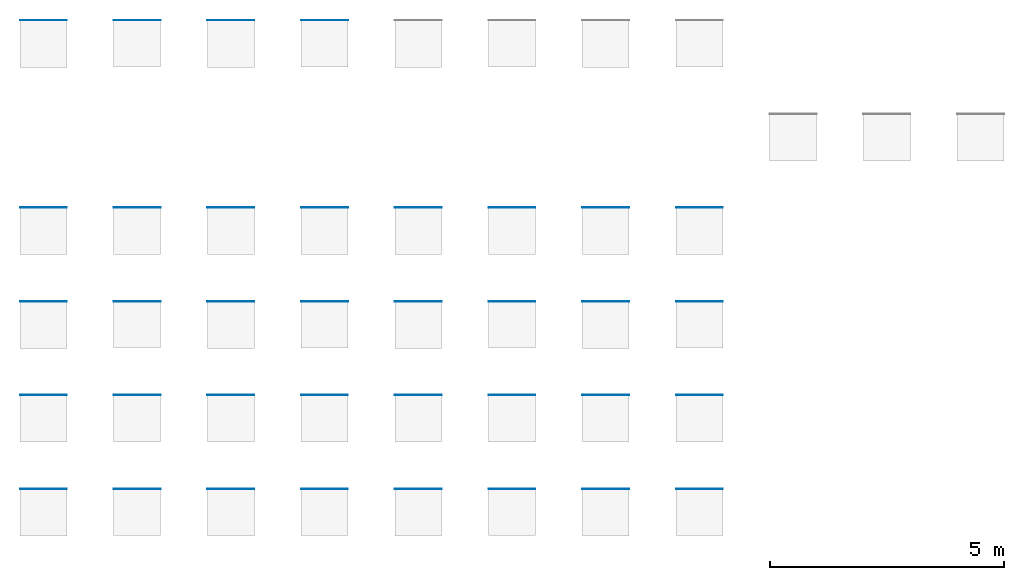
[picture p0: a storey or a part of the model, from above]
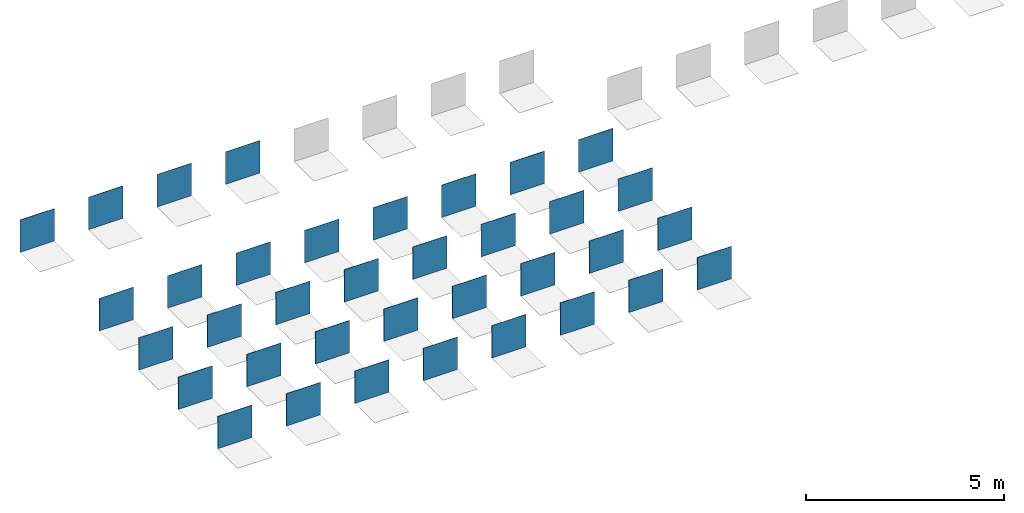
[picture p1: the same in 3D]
Properties of the parts of a building model (IFC2X3), part 1 of 7

# File
Description: ViewDefinition [CoordinationView_V2.0]
Time: 2025-06-20T12:25:42
Written by: The EXPRESS Data Manager Version 5.02.0100.07 : 28 Aug 2013
Made in: 21.1.90.15 - Exporter 21.1.90.15 - Alternate UI 21.1.90.15
Comment: STEP Physical File produced by: The EXPRESS Data Manager Version 5.02.0100.07 : 28 Aug 2013 * Module: EDMstepFileFactory/EDMstandAlone * Creation date: Fri Jun 20 12:25:42 2025 * Host: STB002 * Database: C:\Users\LARISS~1\AppData\Local\Temp\234e31d9-e186-458c-9206-d387dea7a233\df8ae8d7-8933-4d32-850e-2fcda2edac5a\ifc * Database version: 5507 * Database creation date: Fri Jun 20 12:25:40 2025 * Schema: IFC2X3 * Model: DataRepository.ifc * Model creation date: Fri Jun 20 12:25:40 2025 * Header model: DataRepository.ifc_HeaderModel * Header model creation date: Fri Jun 20 12:25:40 2025 * EDMuser: sdai-user * EDMgroup: sdai-group * License ID and type: 5605 : Permanent license. Expiry date: * EDMstepFileFactory options: 020000

# IfcSite, Default
RefLatitude: 42, 24, 53, 508911; RefLongitude: -71, -15, -29, -58837; RefElevation: 0 mm
Pset_ProductRequirements - Category: Project Information

# IfcBuilding
Pset_BuildingCommon - NumberOfStoreys: 1
Pset_ProductRequirements - Category: Project Information

# IfcBuildingStorey: Level:Level 1, Level 1
LongName: Level 1; Elevation: 0 mm
Pset_AirSideSystemInformation - Name: Level 1
Pset_ProductRequirements - Name: Level 1; Category: Levels

# IfcCovering: Floor:REVIGRÉS-LOCUS-BASE-29.5x29.5-SILK-QUILT GREEN (2)
In: Level 1
Type - PredefinedType: CLADDING; Material: REVIGRÉS-LOCUS-BASE-30X30-SILK-QUILT GREEN 8.5 mm
Type - Pset_CoveringCommon - Reference: 312G12V661; Material: Grés porcelânico
Type - Pset_ElementShading - Roughness: 304.8 mm
Type - Pset_ManufacturerTypeInformation - Manufacturer: REVIGRÉS
Type - Pset_ProductRequirements - Category: Floors
Type - Pset_QuantityTakeOff - Reference: 312G12V661
Type - IFC.REVIGRÉS-Dados do fabricante-Floor Covering - FabricanteURL: https://www.revigres.pt/; ReferenciaModelo: Locus; NumeroGlobalDeItemComercial: 312G12V661; Acabamento: SILK; Material: Grés porcelânico; IdentificadorDoOperadorEconomico: 501840856; UrlFabricanteArtigo: https://www.revigres.pt/colecoes/locus; PaisOrigem: Portugal
Type - IFC.REVIGRÉS-Dados de desempenho-Floor Covering - Rectilinearidade: ± 0.2% máx.± 0.8 mm; Ortogonalidade: ± 0.2% máx.± 1.5 mm; PlanaridadeDaSuperficie: ± 0.3% máx. ± 1.8 mm; QualidadeDaSuperficie: Cumpre; AbsorcaoDeAgua: < 0.05%; ModuloDeRuptura: > 45 N/mm²; ResistenciaAFlexao: > 2000 N; ResistenciaAAbrasaoProfunda: < 120 mm³; DilatacaoTermicaLinear: ≤ 8,0x10-6 °C-1; ResistenciaAoChoqueTermico: Resiste; DurabilidadeInterior: Cumpre; DurabilidadeResistenciaAoGeloDegelo: Resiste; ResistenciaAoEscorregamentoDIN51130: R9; ResistenciaAoEscorregamentoDIN51097: A; ResistenciaAoEscorregamentoENV51097: A; ResistenciaAoEscorregamentoENV12633: Class 1; ResistenciaAoEscorregamentoBS7976: -; ResistenciaAoEscorregamentoANSIA1371: ≥0,42; ResistenciaAoDeslizamentoENV12633: Class 1; ResistenciaAoDeslizamentoBS7976: -; ResistenciaAsManchas: Class 5; LibertacaoDeCadmio: 0; LibertacaoDeChumbo: 0
Type - IFC.REVIGRÉS-Dados de especificação-Floor Covering - VariacaoTonalidade: 3; NivelDeTrafego: 5; EPavimento: Sim; ERevestimento: Sim; EExterno: Sim
Type - IFC.REVIGRÉS-Dados geométricos-Floor Covering - AlturaNominal: 8.5 mm; ComprimentoNominal: 29.5 mm; LarguraNominal: 29.5 mm
Type - IFC.REVIGRÉS-Dados de sustentabilidade-Floor Covering - ItemEParcialmenteReciclado: 0; EnergiaTermicaExportada: 0; ItemENovo: Sim; ItemEReciclado: Não; VidaÚtilEsperada: 50; SubstanciasPerigosas: Não; PotencialDeEsgotamentoAbioticoDosRecursosFosseis: 203; PotencialDeEsgotamentoAbioticoDosRecursosNaoFosseisMineraisEMetais: 0.000701; PotencialDeAquecimentoGlobalBiogenico: -0.48; CombustiveisFosseisComPotencialDeAquecimentoGlobal: 13.9; PotencialDeAquecimentoGlobalUsoDoSoloEMudancaDeUsoDoSolo: 0.0246; PotencialDeEutrofizacaoFraccaoDeNutrientesQueAtingemOCompartimentoFinalDeAguaDoce: 0.000189; PotencialDeEutrofizacaoFraccaoDeNutrientesQueAtingemOCompartimentoFinalMarinho: 0.0122; EnergiaRecuperada: 0.00739; ConsumoDeAguaDoce: 0.113; UtilizacaoLiquidaDeAguaDoce: 0.113; ResiduosPerigososEliminados: 0.00221; ResiduosNaoPerigososEliminados: 1.83; MassaTotalDeResiduosRadioactivosEliminados: 0.000394; EnergiaElectricaExportada: 1.55; MateriaisParaRecuperacaoDeEnergia: 0.00739; MateriaisParaReciclagem: 0.0253; UnidadeEPD: 1 m²
Type - IFC.REVIGRÉS-Dados gerais-Floor Covering - Nome: REVIGRÉS-LOCUS-BASE-29.5x29.5-SILK-QUILT GREEN; TipoProduto: Prensado a seco: grupo BIa UGL | Grés porcelânico técnico; NumeroDeRegistoDAP: EPD-REV-20240006-CCC1-EN; ReferenciaDAP: -; UrlDOP: -
Classification: C3010 (Uniformat)
Pset_CoveringCommon - TotalThickness: 8.5 mm
IFC.REVIGRÉS-Dados do fabricante-Floor Covering - Type: Floor: REVIGRÉS-LOCUS-BASE-29.5x29.5-SILK-QUILT GREEN
IFC.REVIGRÉS-Dados de desempenho-Floor Covering - Type: Floor: REVIGRÉS-LOCUS-BASE-29.5x29.5-SILK-QUILT GREEN
IFC.REVIGRÉS-Dados de especificação-Floor Covering - Type: Floor: REVIGRÉS-LOCUS-BASE-29.5x29.5-SILK-QUILT GREEN
IFC.REVIGRÉS-Dados geométricos-Floor Covering - Type: Floor: REVIGRÉS-LOCUS-BASE-29.5x29.5-SILK-QUILT GREEN
IFC.REVIGRÉS-Dados de sustentabilidade-Floor Covering - Type: Floor: REVIGRÉS-LOCUS-BASE-29.5x29.5-SILK-QUILT GREEN
Name (Floor:REVIGRÉS-LOCUS-BASE-29.5x29.5-SILK-QUILT GREEN:...)
40861
40868

# IfcCovering: Floor:REVIGRÉS-LOCUS-BASE-29.5x29.5-SILK-QUILT GRIS, Floor:REVIGRÉS-LOCUS-BASE-29.5x29.5-SILK-QUILT GRIS:40875
In: Level 1
Type - PredefinedType: CLADDING; Material: REVIGRÉS-LOCUS-BASE-30X30-SILK-QUILT GRIS 8.5 mm
Type - Pset_CoveringCommon - Reference: 312G12V651; Material: Grés porcelânico
Type - Pset_ElementShading - Roughness: 304.8 mm
Type - Pset_ManufacturerTypeInformation - Manufacturer: REVIGRÉS
Type - Pset_ProductRequirements - Category: Floors
Type - Pset_QuantityTakeOff - Reference: 312G12V651
Type - IFC.REVIGRÉS-Dados do fabricante-Floor Covering - FabricanteURL: https://www.revigres.pt/; ReferenciaModelo: Locus; NumeroGlobalDeItemComercial: 312G12V651; Acabamento: SILK; Material: Grés porcelânico; IdentificadorDoOperadorEconomico: 501840856; UrlFabricanteArtigo: https://www.revigres.pt/colecoes/locus; PaisOrigem: Portugal
Type - IFC.REVIGRÉS-Dados de desempenho-Floor Covering - Rectilinearidade: ± 0.2% máx.± 0.8 mm; Ortogonalidade: ± 0.2% máx.± 1.5 mm; PlanaridadeDaSuperficie: ± 0.3% máx. ± 1.8 mm; QualidadeDaSuperficie: Cumpre; AbsorcaoDeAgua: < 0.05%; ModuloDeRuptura: > 45 N/mm²; ResistenciaAFlexao: > 2000 N; ResistenciaAAbrasaoProfunda: < 120 mm³; DilatacaoTermicaLinear: ≤ 8,0x10-6 °C-1; ResistenciaAoChoqueTermico: Resiste; DurabilidadeInterior: Cumpre; DurabilidadeResistenciaAoGeloDegelo: Resiste; ResistenciaAoEscorregamentoDIN51130: R9; ResistenciaAoEscorregamentoDIN51097: A; ResistenciaAoEscorregamentoENV51097: A; ResistenciaAoEscorregamentoENV12633: Class 1; ResistenciaAoEscorregamentoBS7976: -; ResistenciaAoEscorregamentoANSIA1371: ≥0,42; ResistenciaAoDeslizamentoENV12633: Class 1; ResistenciaAoDeslizamentoBS7976: -; ResistenciaAsManchas: Class 5; LibertacaoDeCadmio: 0; LibertacaoDeChumbo: 0
Type - IFC.REVIGRÉS-Dados de especificação-Floor Covering - VariacaoTonalidade: 3; NivelDeTrafego: 5; EPavimento: Sim; ERevestimento: Sim; EExterno: Sim
Type - IFC.REVIGRÉS-Dados geométricos-Floor Covering - AlturaNominal: 8.5 mm; ComprimentoNominal: 29.5 mm; LarguraNominal: 29.5 mm
Type - IFC.REVIGRÉS-Dados de sustentabilidade-Floor Covering - EnergiaTermicaExportada: 0; ItemENovo: Sim; ItemEParcialmenteReciclado: 0.23; ItemEReciclado: Sim; VidaÚtilEsperada: 50; SubstanciasPerigosas: Não; PotencialDeEsgotamentoAbioticoDosRecursosFosseis: 203; PotencialDeEsgotamentoAbioticoDosRecursosNaoFosseisMineraisEMetais: 0.000701; PotencialDeAquecimentoGlobalBiogenico: -0.48; CombustiveisFosseisComPotencialDeAquecimentoGlobal: 13.9; PotencialDeAquecimentoGlobalUsoDoSoloEMudancaDeUsoDoSolo: 0.0246; PotencialDeEutrofizacaoFraccaoDeNutrientesQueAtingemOCompartimentoFinalDeAguaDoce: 0.000189; PotencialDeEutrofizacaoFraccaoDeNutrientesQueAtingemOCompartimentoFinalMarinho: 0.0122; EnergiaRecuperada: 0.00739; ConsumoDeAguaDoce: 0.113; UtilizacaoLiquidaDeAguaDoce: 0.113; ResiduosPerigososEliminados: 0.00221; ResiduosNaoPerigososEliminados: 1.83; MassaTotalDeResiduosRadioactivosEliminados: 0.000394; EnergiaElectricaExportada: 1.55; MateriaisParaRecuperacaoDeEnergia: 0.00739; MateriaisParaReciclagem: 0.0253; UnidadeEPD: 1 m²
Type - IFC.REVIGRÉS-Dados gerais-Floor Covering - Nome: REVIGRÉS-LOCUS-BASE-29.5x29.5-SILK-QUILT GRIS; TipoProduto: Prensado a seco: grupo BIa UGL | Grés porcelânico técnico; NumeroDeRegistoDAP: EPD-REV-20240006-CCC1-EN; ReferenciaDAP: -; UrlDOP: -
Classification: C3010 (Uniformat)
Pset_CoveringCommon - TotalThickness: 8.5 mm
IFC.REVIGRÉS-Dados do fabricante-Floor Covering - Type: Floor: REVIGRÉS-LOCUS-BASE-29.5x29.5-SILK-QUILT GRIS
IFC.REVIGRÉS-Dados de desempenho-Floor Covering - Type: Floor: REVIGRÉS-LOCUS-BASE-29.5x29.5-SILK-QUILT GRIS
IFC.REVIGRÉS-Dados de especificação-Floor Covering - Type: Floor: REVIGRÉS-LOCUS-BASE-29.5x29.5-SILK-QUILT GRIS
IFC.REVIGRÉS-Dados geométricos-Floor Covering - Type: Floor: REVIGRÉS-LOCUS-BASE-29.5x29.5-SILK-QUILT GRIS
IFC.REVIGRÉS-Dados de sustentabilidade-Floor Covering - Type: Floor: REVIGRÉS-LOCUS-BASE-29.5x29.5-SILK-QUILT GRIS

# IfcCovering: Floor:REVIGRÉS-LOCUS-BASE-29.5x29.5-SOFT GRIP-QUILT BONE, Floor:REVIGRÉS-LOCUS-BASE-29.5x29.5-SOFT GRIP-QUILT BONE:40825
In: Level 1
Type - PredefinedType: CLADDING; Material: REVIGRÉS-LOCUS-BASE-30X30-SOFT GRIP-QUILT BONE 8.5 mm
Type - Pset_CoveringCommon - Reference: 312F12V641; Material: Grés porcelânico
Type - Pset_ElementShading - Roughness: 304.8 mm
Type - Pset_ManufacturerTypeInformation - Manufacturer: REVIGRÉS
Type - Pset_ProductRequirements - Category: Floors
Type - Pset_QuantityTakeOff - Reference: 312F12V641
Type - IFC.REVIGRÉS-Dados do fabricante-Floor Covering - FabricanteURL: https://www.revigres.pt/; ReferenciaModelo: Locus; NumeroGlobalDeItemComercial: 312F12V641; Acabamento: SOFT; Material: Grés porcelânico; IdentificadorDoOperadorEconomico: 501840856; UrlFabricanteArtigo: https://www.revigres.pt/colecoes/locus; PaisOrigem: Portugal
Type - IFC.REVIGRÉS-Dados de desempenho-Floor Covering - Rectilinearidade: ± 0.2% máx ± 1.0 mm; Ortogonalidade: ± 0.2% máx.± 1.5 mm; PlanaridadeDaSuperficie: ± 0.3% máx. ± 1.8 mm; QualidadeDaSuperficie: Cumpre; AbsorcaoDeAgua: < 0.05%; ModuloDeRuptura: > 45 N/mm²; ResistenciaAFlexao: > 2000 N; ResistenciaAAbrasaoProfunda: < 120 mm³; DilatacaoTermicaLinear: ≤ 8,0x10-6 °C-1; ResistenciaAoChoqueTermico: Resiste; DurabilidadeInterior: Cumpre; DurabilidadeResistenciaAoGeloDegelo: Resiste; ResistenciaAoEscorregamentoDIN51130: R11; ResistenciaAoEscorregamentoDIN51097: A; ResistenciaAoEscorregamentoENV51097: A; ResistenciaAoEscorregamentoENV12633: Class 2; ResistenciaAoEscorregamentoBS7976: > 36; ResistenciaAoEscorregamentoANSIA1371: ≥0,42; ResistenciaAoDeslizamentoENV12633: Class 2; ResistenciaAoDeslizamentoBS7976: > 36; ResistenciaAsManchas: Class 5; LibertacaoDeCadmio: 0; LibertacaoDeChumbo: 0
Type - IFC.REVIGRÉS-Dados de especificação-Floor Covering - VariacaoTonalidade: 3; NivelDeTrafego: 5; EPavimento: Sim; ERevestimento: Sim; EExterno: Sim
Type - IFC.REVIGRÉS-Dados geométricos-Floor Covering - AlturaNominal: 8.5 mm; ComprimentoNominal: 29.5 mm; LarguraNominal: 29.5 mm
Type - IFC.REVIGRÉS-Dados de sustentabilidade-Floor Covering - ItemEParcialmenteReciclado: 0; EnergiaTermicaExportada: 0; ItemENovo: Sim; ItemEReciclado: Não; VidaÚtilEsperada: 50; SubstanciasPerigosas: Não; PotencialDeEsgotamentoAbioticoDosRecursosFosseis: 203; PotencialDeEsgotamentoAbioticoDosRecursosNaoFosseisMineraisEMetais: 0.000701; PotencialDeAquecimentoGlobalBiogenico: -0.48; CombustiveisFosseisComPotencialDeAquecimentoGlobal: 13.9; PotencialDeAquecimentoGlobalUsoDoSoloEMudancaDeUsoDoSolo: 0.0246; PotencialDeEutrofizacaoFraccaoDeNutrientesQueAtingemOCompartimentoFinalDeAguaDoce: 0.000189; PotencialDeEutrofizacaoFraccaoDeNutrientesQueAtingemOCompartimentoFinalMarinho: 0.0122; EnergiaRecuperada: 0.00739; ConsumoDeAguaDoce: 0.113; UtilizacaoLiquidaDeAguaDoce: 0.113; ResiduosPerigososEliminados: 0.00221; ResiduosNaoPerigososEliminados: 1.83; MassaTotalDeResiduosRadioactivosEliminados: 0.000394; EnergiaElectricaExportada: 1.55; MateriaisParaRecuperacaoDeEnergia: 0.00739; MateriaisParaReciclagem: 0.0253; UnidadeEPD: 1 m²
Type - IFC.REVIGRÉS-Dados gerais-Floor Covering - Nome: REVIGRÉS-LOCUS-BASE-29.5x29.5-SOFT GRIP-QUILT BONE; TipoProduto: Prensado a seco: grupo BIa UGL | Grés porcelânico técnico; NumeroDeRegistoDAP: EPD-REV-20240006-CCC1-EN; ReferenciaDAP: -; UrlDOP: -
Classification: C3010 (Uniformat)
Pset_CoveringCommon - TotalThickness: 8.5 mm
IFC.REVIGRÉS-Dados do fabricante-Floor Covering - Type: Floor: REVIGRÉS-LOCUS-BASE-29.5x29.5-SOFT GRIP-QUILT BONE
IFC.REVIGRÉS-Dados de desempenho-Floor Covering - Type: Floor: REVIGRÉS-LOCUS-BASE-29.5x29.5-SOFT GRIP-QUILT BONE
IFC.REVIGRÉS-Dados de especificação-Floor Covering - Type: Floor: REVIGRÉS-LOCUS-BASE-29.5x29.5-SOFT GRIP-QUILT BONE
IFC.REVIGRÉS-Dados geométricos-Floor Covering - Type: Floor: REVIGRÉS-LOCUS-BASE-29.5x29.5-SOFT GRIP-QUILT BONE
IFC.REVIGRÉS-Dados de sustentabilidade-Floor Covering - Type: Floor: REVIGRÉS-LOCUS-BASE-29.5x29.5-SOFT GRIP-QUILT BONE

# IfcCovering: Floor:REVIGRÉS-LOCUS-BASE-29.5x29.5-SOFT GRIP-QUILT GREEN, Floor:REVIGRÉS-LOCUS-BASE-29.5x29.5-SOFT GRIP-QUILT GREEN:40833
In: Level 1
Type - PredefinedType: CLADDING; Material: REVIGRÉS-LOCUS-BASE-30X30-SOFT GRIP-QUILT GREEN 8.5 mm
Type - Pset_CoveringCommon - Reference: 312F12V661; Material: Grés porcelânico
Type - Pset_ElementShading - Roughness: 304.8 mm
Type - Pset_ManufacturerTypeInformation - Manufacturer: REVIGRÉS
Type - Pset_ProductRequirements - Category: Floors
Type - Pset_QuantityTakeOff - Reference: 312F12V661
Type - IFC.REVIGRÉS-Dados do fabricante-Floor Covering - FabricanteURL: https://www.revigres.pt/; ReferenciaModelo: Locus; NumeroGlobalDeItemComercial: 312F12V661; Acabamento: SOFT; Material: Grés porcelânico; IdentificadorDoOperadorEconomico: 501840856; UrlFabricanteArtigo: https://www.revigres.pt/colecoes/locus; PaisOrigem: Portugal
Type - IFC.REVIGRÉS-Dados de desempenho-Floor Covering - Rectilinearidade: ± 0.2% máx ± 1.0 mm; Ortogonalidade: ± 0.2% máx.± 1.5 mm; PlanaridadeDaSuperficie: ± 0.3% máx. ± 1.8 mm; QualidadeDaSuperficie: Cumpre; AbsorcaoDeAgua: < 0.05%; ModuloDeRuptura: > 45 N/mm²; ResistenciaAFlexao: > 2000 N; ResistenciaAAbrasaoProfunda: < 120 mm³; DilatacaoTermicaLinear: ≤ 8,0x10-6 °C-1; ResistenciaAoChoqueTermico: Resiste; DurabilidadeInterior: Cumpre; DurabilidadeResistenciaAoGeloDegelo: Resiste; ResistenciaAoEscorregamentoDIN51130: R11; ResistenciaAoEscorregamentoDIN51097: A; ResistenciaAoEscorregamentoENV51097: A; ResistenciaAoEscorregamentoENV12633: Class 2; ResistenciaAoEscorregamentoBS7976: > 36; ResistenciaAoEscorregamentoANSIA1371: ≥0,42; ResistenciaAoDeslizamentoENV12633: Class 2; ResistenciaAoDeslizamentoBS7976: > 36; ResistenciaAsManchas: Class 5; LibertacaoDeCadmio: 0; LibertacaoDeChumbo: 0
Type - IFC.REVIGRÉS-Dados de especificação-Floor Covering - VariacaoTonalidade: 3; NivelDeTrafego: 5; EPavimento: Sim; ERevestimento: Sim; EExterno: Sim
Type - IFC.REVIGRÉS-Dados geométricos-Floor Covering - AlturaNominal: 8.5 mm; ComprimentoNominal: 29.5 mm; LarguraNominal: 29.5 mm
Type - IFC.REVIGRÉS-Dados de sustentabilidade-Floor Covering - ItemEParcialmenteReciclado: 0; EnergiaTermicaExportada: 0; ItemENovo: Sim; ItemEReciclado: Não; VidaÚtilEsperada: 50; SubstanciasPerigosas: Não; PotencialDeEsgotamentoAbioticoDosRecursosFosseis: 203; PotencialDeEsgotamentoAbioticoDosRecursosNaoFosseisMineraisEMetais: 0.000701; PotencialDeAquecimentoGlobalBiogenico: -0.48; CombustiveisFosseisComPotencialDeAquecimentoGlobal: 13.9; PotencialDeAquecimentoGlobalUsoDoSoloEMudancaDeUsoDoSolo: 0.0246; PotencialDeEutrofizacaoFraccaoDeNutrientesQueAtingemOCompartimentoFinalDeAguaDoce: 0.000189; PotencialDeEutrofizacaoFraccaoDeNutrientesQueAtingemOCompartimentoFinalMarinho: 0.0122; EnergiaRecuperada: 0.00739; ConsumoDeAguaDoce: 0.113; UtilizacaoLiquidaDeAguaDoce: 0.113; ResiduosPerigososEliminados: 0.00221; ResiduosNaoPerigososEliminados: 1.83; MassaTotalDeResiduosRadioactivosEliminados: 0.000394; EnergiaElectricaExportada: 1.55; MateriaisParaRecuperacaoDeEnergia: 0.00739; MateriaisParaReciclagem: 0.0253; UnidadeEPD: 1 m²
Type - IFC.REVIGRÉS-Dados gerais-Floor Covering - Nome: REVIGRÉS-LOCUS-BASE-29.5x29.5-SOFT GRIP-QUILT GREEN; TipoProduto: Prensado a seco: grupo BIa UGL | Grés porcelânico técnico; NumeroDeRegistoDAP: EPD-REV-20240006-CCC1-EN; ReferenciaDAP: -; UrlDOP: -
Classification: C3010 (Uniformat)
Pset_CoveringCommon - TotalThickness: 8.5 mm
IFC.REVIGRÉS-Dados do fabricante-Floor Covering - Type: Floor: REVIGRÉS-LOCUS-BASE-29.5x29.5-SOFT GRIP-QUILT GREEN
IFC.REVIGRÉS-Dados de desempenho-Floor Covering - Type: Floor: REVIGRÉS-LOCUS-BASE-29.5x29.5-SOFT GRIP-QUILT GREEN
IFC.REVIGRÉS-Dados de especificação-Floor Covering - Type: Floor: REVIGRÉS-LOCUS-BASE-29.5x29.5-SOFT GRIP-QUILT GREEN
IFC.REVIGRÉS-Dados geométricos-Floor Covering - Type: Floor: REVIGRÉS-LOCUS-BASE-29.5x29.5-SOFT GRIP-QUILT GREEN
IFC.REVIGRÉS-Dados de sustentabilidade-Floor Covering - Type: Floor: REVIGRÉS-LOCUS-BASE-29.5x29.5-SOFT GRIP-QUILT GREEN

# IfcCovering: Floor:REVIGRÉS-LOCUS-BASE-29.5x29.5-SOFT GRIP-QUILT GRIS, Floor:REVIGRÉS-LOCUS-BASE-29.5x29.5-SOFT GRIP-QUILT GRIS:40841
In: Level 1
Type - PredefinedType: CLADDING; Material: REVIGRÉS-LOCUS-BASE-30X30-SOFT GRIP-QUILT GRIS 8.5 mm
Type - Pset_CoveringCommon - Reference: 312F12V651; Material: Grés porcelânico
Type - Pset_ElementShading - Roughness: 304.8 mm
Type - Pset_ManufacturerTypeInformation - Manufacturer: REVIGRÉS
Type - Pset_ProductRequirements - Category: Floors
Type - Pset_QuantityTakeOff - Reference: 312F12V651
Type - IFC.REVIGRÉS-Dados do fabricante-Floor Covering - FabricanteURL: https://www.revigres.pt/; ReferenciaModelo: Locus; NumeroGlobalDeItemComercial: 312F12V651; Acabamento: SOFT; Material: Grés porcelânico; IdentificadorDoOperadorEconomico: 501840856; UrlFabricanteArtigo: https://www.revigres.pt/colecoes/locus; PaisOrigem: Portugal
Type - IFC.REVIGRÉS-Dados de desempenho-Floor Covering - Rectilinearidade: ± 0.2% máx ± 1.0 mm; Ortogonalidade: ± 0.2% máx.± 1.5 mm; PlanaridadeDaSuperficie: ± 0.3% máx. ± 1.8 mm; QualidadeDaSuperficie: Cumpre; AbsorcaoDeAgua: < 0.05%; ModuloDeRuptura: > 45 N/mm²; ResistenciaAFlexao: > 2000 N; ResistenciaAAbrasaoProfunda: < 120 mm³; DilatacaoTermicaLinear: ≤ 8,0x10-6 °C-1; ResistenciaAoChoqueTermico: Resiste; DurabilidadeInterior: Cumpre; DurabilidadeResistenciaAoGeloDegelo: Resiste; ResistenciaAoEscorregamentoDIN51130: R11; ResistenciaAoEscorregamentoDIN51097: A; ResistenciaAoEscorregamentoENV51097: A; ResistenciaAoEscorregamentoENV12633: Class 2; ResistenciaAoEscorregamentoBS7976: > 36; ResistenciaAoEscorregamentoANSIA1371: ≥0,42; ResistenciaAoDeslizamentoENV12633: Class 2; ResistenciaAoDeslizamentoBS7976: > 36; ResistenciaAsManchas: Class 5; LibertacaoDeCadmio: 0; LibertacaoDeChumbo: 0
Type - IFC.REVIGRÉS-Dados de especificação-Floor Covering - VariacaoTonalidade: 3; NivelDeTrafego: 5; EPavimento: Sim; ERevestimento: Sim; EExterno: Sim
Type - IFC.REVIGRÉS-Dados geométricos-Floor Covering - AlturaNominal: 8.5 mm; ComprimentoNominal: 29.5 mm; LarguraNominal: 29.5 mm
Type - IFC.REVIGRÉS-Dados de sustentabilidade-Floor Covering - EnergiaTermicaExportada: 0; ItemENovo: Sim; ItemEParcialmenteReciclado: 0.23; ItemEReciclado: Sim; VidaÚtilEsperada: 50; SubstanciasPerigosas: Não; PotencialDeEsgotamentoAbioticoDosRecursosFosseis: 203; PotencialDeEsgotamentoAbioticoDosRecursosNaoFosseisMineraisEMetais: 0.000701; PotencialDeAquecimentoGlobalBiogenico: -0.48; CombustiveisFosseisComPotencialDeAquecimentoGlobal: 13.9; PotencialDeAquecimentoGlobalUsoDoSoloEMudancaDeUsoDoSolo: 0.0246; PotencialDeEutrofizacaoFraccaoDeNutrientesQueAtingemOCompartimentoFinalDeAguaDoce: 0.000189; PotencialDeEutrofizacaoFraccaoDeNutrientesQueAtingemOCompartimentoFinalMarinho: 0.0122; EnergiaRecuperada: 0.00739; ConsumoDeAguaDoce: 0.113; UtilizacaoLiquidaDeAguaDoce: 0.113; ResiduosPerigososEliminados: 0.00221; ResiduosNaoPerigososEliminados: 1.83; MassaTotalDeResiduosRadioactivosEliminados: 0.000394; EnergiaElectricaExportada: 1.55; MateriaisParaRecuperacaoDeEnergia: 0.00739; MateriaisParaReciclagem: 0.0253; UnidadeEPD: 1 m²
Type - IFC.REVIGRÉS-Dados gerais-Floor Covering - Nome: REVIGRÉS-LOCUS-BASE-29.5x29.5-SOFT GRIP-QUILT GRIS; TipoProduto: Prensado a seco: grupo BIa UGL | Grés porcelânico técnico; NumeroDeRegistoDAP: EPD-REV-20240006-CCC1-EN; ReferenciaDAP: -; UrlDOP: -
Classification: C3010 (Uniformat)
Pset_CoveringCommon - TotalThickness: 8.5 mm
IFC.REVIGRÉS-Dados do fabricante-Floor Covering - Type: Floor: REVIGRÉS-LOCUS-BASE-29.5x29.5-SOFT GRIP-QUILT GRIS
IFC.REVIGRÉS-Dados de desempenho-Floor Covering - Type: Floor: REVIGRÉS-LOCUS-BASE-29.5x29.5-SOFT GRIP-QUILT GRIS
IFC.REVIGRÉS-Dados de especificação-Floor Covering - Type: Floor: REVIGRÉS-LOCUS-BASE-29.5x29.5-SOFT GRIP-QUILT GRIS
IFC.REVIGRÉS-Dados geométricos-Floor Covering - Type: Floor: REVIGRÉS-LOCUS-BASE-29.5x29.5-SOFT GRIP-QUILT GRIS
IFC.REVIGRÉS-Dados de sustentabilidade-Floor Covering - Type: Floor: REVIGRÉS-LOCUS-BASE-29.5x29.5-SOFT GRIP-QUILT GRIS

# IfcCovering: Floor:REVIGRÉS-LOCUS-BASE-29.5x59.2-SILK-ALLOY, Floor:REVIGRÉS-LOCUS-BASE-29.5x59.2-SILK-ALLOY:36071
In: Level 1
Type - PredefinedType: CLADDING; Material: REVIGRÉS-LOCUS-BASE-30x60-SILK-ALLOY 8.5 mm
Type - Pset_CoveringCommon - Reference: 312G21V671; Material: Grés porcelânico
Type - Pset_ElementShading - Roughness: 304.8 mm
Type - Pset_ManufacturerTypeInformation - Manufacturer: REVIGRÉS
Type - Pset_ProductRequirements - Category: Floors
Type - Pset_QuantityTakeOff - Reference: 312G21V671
Type - IFC.REVIGRÉS-Dados do fabricante-Floor Covering - FabricanteURL: https://www.revigres.pt/; ReferenciaModelo: Locus; NumeroGlobalDeItemComercial: 312G21V691; Acabamento: SILK; Material: Grés porcelânico; IdentificadorDoOperadorEconomico: 501840856; UrlFabricanteArtigo: https://www.revigres.pt/colecoes/locus; PaisOrigem: Portugal
Type - IFC.REVIGRÉS-Dados de desempenho-Floor Covering - Rectilinearidade: ± 0.2% máx.± 0.8 mm; Ortogonalidade: ± 0.2% máx.± 1.5 mm; PlanaridadeDaSuperficie: ± 0.3% máx. ± 1.8 mm; QualidadeDaSuperficie: Cumpre; AbsorcaoDeAgua: < 0.05%; ModuloDeRuptura: > 45 N/mm²; ResistenciaAFlexao: > 2000 N; ResistenciaAAbrasaoProfunda: < 120 mm³; DilatacaoTermicaLinear: ≤ 8,0x10-6 °C-1; ResistenciaAoChoqueTermico: Resiste; DurabilidadeInterior: Cumpre; DurabilidadeResistenciaAoGeloDegelo: Resiste; ResistenciaAoEscorregamentoDIN51130: R9; ResistenciaAoEscorregamentoDIN51097: A; ResistenciaAoEscorregamentoENV51097: A; ResistenciaAoEscorregamentoENV12633: Class 1; ResistenciaAoEscorregamentoBS7976: -; ResistenciaAoEscorregamentoANSIA1371: ≥0,42; ResistenciaAoDeslizamentoENV12633: Class 1; ResistenciaAoDeslizamentoBS7976: -; ResistenciaAsManchas: Class 5; LibertacaoDeCadmio: 0; LibertacaoDeChumbo: 0
Type - IFC.REVIGRÉS-Dados de especificação-Floor Covering - VariacaoTonalidade: 3; NivelDeTrafego: 5; EPavimento: Sim; ERevestimento: Sim; EExterno: Sim
Type - IFC.REVIGRÉS-Dados geométricos-Floor Covering - AlturaNominal: 8.5 mm; ComprimentoNominal: 29.5 mm; LarguraNominal: 59.2 mm
Type - IFC.REVIGRÉS-Dados de sustentabilidade-Floor Covering - EnergiaTermicaExportada: 0; ItemENovo: Sim; ItemEParcialmenteReciclado: 0.23; ItemEReciclado: Sim; VidaÚtilEsperada: 50; SubstanciasPerigosas: Não; PotencialDeEsgotamentoAbioticoDosRecursosFosseis: 203; PotencialDeEsgotamentoAbioticoDosRecursosNaoFosseisMineraisEMetais: 0.000701; PotencialDeAquecimentoGlobalBiogenico: -0.48; CombustiveisFosseisComPotencialDeAquecimentoGlobal: 13.9; PotencialDeAquecimentoGlobalUsoDoSoloEMudancaDeUsoDoSolo: 0.0246; PotencialDeEutrofizacaoFraccaoDeNutrientesQueAtingemOCompartimentoFinalDeAguaDoce: 0.000189; PotencialDeEutrofizacaoFraccaoDeNutrientesQueAtingemOCompartimentoFinalMarinho: 0.0122; EnergiaRecuperada: 0.00739; ConsumoDeAguaDoce: 0.113; UtilizacaoLiquidaDeAguaDoce: 0.113; ResiduosPerigososEliminados: 0.00221; ResiduosNaoPerigososEliminados: 1.83; MassaTotalDeResiduosRadioactivosEliminados: 0.000394; EnergiaElectricaExportada: 1.55; MateriaisParaRecuperacaoDeEnergia: 0.00739; MateriaisParaReciclagem: 0.0253; UnidadeEPD: 1 m²
Type - IFC.REVIGRÉS-Dados gerais-Floor Covering - Nome: REVIGRÉS-LOCUS-BASE-29.5x59.2-SILK-GRIS; TipoProduto: Prensado a seco: grupo BIa UGL | Grés porcelânico técnico; NumeroDeRegistoDAP: EPD-REV-20240006-CCC1-EN; ReferenciaDAP: -; UrlDOP: -
Classification: C3010 (Uniformat)
Pset_CoveringCommon - TotalThickness: 8.5 mm
IFC.REVIGRÉS-Dados do fabricante-Floor Covering - Type: Floor: REVIGRÉS-LOCUS-BASE-29.5x59.2-SILK-ALLOY
IFC.REVIGRÉS-Dados de desempenho-Floor Covering - Type: Floor: REVIGRÉS-LOCUS-BASE-29.5x59.2-SILK-ALLOY
IFC.REVIGRÉS-Dados de especificação-Floor Covering - Type: Floor: REVIGRÉS-LOCUS-BASE-29.5x59.2-SILK-ALLOY
IFC.REVIGRÉS-Dados geométricos-Floor Covering - Type: Floor: REVIGRÉS-LOCUS-BASE-29.5x59.2-SILK-ALLOY
IFC.REVIGRÉS-Dados de sustentabilidade-Floor Covering - Type: Floor: REVIGRÉS-LOCUS-BASE-29.5x59.2-SILK-ALLOY

# IfcCovering: Floor:REVIGRÉS-LOCUS-BASE-29.5x59.2-SILK-BONE, Floor:REVIGRÉS-LOCUS-BASE-29.5x59.2-SILK-BONE:36651
In: Level 1
Type - PredefinedType: CLADDING; Material: REVIGRÉS-LOCUS-BASE-30x60-SILK-BONE 8.5 mm
Type - Pset_CoveringCommon - Reference: 312G21V681; Material: Grés porcelânico
Type - Pset_ElementShading - Roughness: 304.8 mm
Type - Pset_ManufacturerTypeInformation - Manufacturer: REVIGRÉS
Type - Pset_ProductRequirements - Category: Floors
Type - Pset_QuantityTakeOff - Reference: 312G21V681
Type - IFC.REVIGRÉS-Dados do fabricante-Floor Covering - FabricanteURL: https://www.revigres.pt/; ReferenciaModelo: Locus; NumeroGlobalDeItemComercial: 312G21V701; Acabamento: SILK; Material: Grés porcelânico; IdentificadorDoOperadorEconomico: 501840856; UrlFabricanteArtigo: https://www.revigres.pt/colecoes/locus; PaisOrigem: Portugal
Type - IFC.REVIGRÉS-Dados de desempenho-Floor Covering - Rectilinearidade: ± 0.2% máx.± 0.8 mm; Ortogonalidade: ± 0.2% máx.± 1.5 mm; PlanaridadeDaSuperficie: ± 0.3% máx. ± 1.8 mm; QualidadeDaSuperficie: Cumpre; AbsorcaoDeAgua: < 0.05%; ModuloDeRuptura: > 45 N/mm²; ResistenciaAFlexao: > 2000 N; ResistenciaAAbrasaoProfunda: < 120 mm³; DilatacaoTermicaLinear: ≤ 8,0x10-6 °C-1; ResistenciaAoChoqueTermico: Resiste; DurabilidadeInterior: Cumpre; DurabilidadeResistenciaAoGeloDegelo: Resiste; ResistenciaAoEscorregamentoDIN51130: R9; ResistenciaAoEscorregamentoDIN51097: A; ResistenciaAoEscorregamentoENV51097: A; ResistenciaAoEscorregamentoENV12633: Class 1; ResistenciaAoEscorregamentoBS7976: -; ResistenciaAoEscorregamentoANSIA1371: ≥0,42; ResistenciaAoDeslizamentoENV12633: Class 1; ResistenciaAoDeslizamentoBS7976: -; ResistenciaAsManchas: Class 5; LibertacaoDeCadmio: 0; LibertacaoDeChumbo: 0
Type - IFC.REVIGRÉS-Dados de especificação-Floor Covering - VariacaoTonalidade: 3; NivelDeTrafego: 5; EPavimento: Sim; ERevestimento: Sim; EExterno: Sim
Type - IFC.REVIGRÉS-Dados geométricos-Floor Covering - AlturaNominal: 8.5 mm; ComprimentoNominal: 29.5 mm; LarguraNominal: 59.2 mm
Type - IFC.REVIGRÉS-Dados de sustentabilidade-Floor Covering - EnergiaTermicaExportada: 0; ItemENovo: Sim; ItemEParcialmenteReciclado: 0.29; ItemEReciclado: Sim; VidaÚtilEsperada: 50; SubstanciasPerigosas: Não; PotencialDeEsgotamentoAbioticoDosRecursosFosseis: 203; PotencialDeEsgotamentoAbioticoDosRecursosNaoFosseisMineraisEMetais: 0.000701; PotencialDeAquecimentoGlobalBiogenico: -0.48; CombustiveisFosseisComPotencialDeAquecimentoGlobal: 13.9; PotencialDeAquecimentoGlobalUsoDoSoloEMudancaDeUsoDoSolo: 0.0246; PotencialDeEutrofizacaoFraccaoDeNutrientesQueAtingemOCompartimentoFinalDeAguaDoce: 0.000189; PotencialDeEutrofizacaoFraccaoDeNutrientesQueAtingemOCompartimentoFinalMarinho: 0.0122; EnergiaRecuperada: 0.00739; ConsumoDeAguaDoce: 0.113; UtilizacaoLiquidaDeAguaDoce: 0.113; ResiduosPerigososEliminados: 0.00221; ResiduosNaoPerigososEliminados: 1.83; MassaTotalDeResiduosRadioactivosEliminados: 0.000394; EnergiaElectricaExportada: 1.55; MateriaisParaRecuperacaoDeEnergia: 0.00739; MateriaisParaReciclagem: 0.0253; UnidadeEPD: 1 m²
Type - IFC.REVIGRÉS-Dados gerais-Floor Covering - Nome: REVIGRÉS-LOCUS-BASE-29.5x59.2-SILK-SMOG; TipoProduto: Prensado a seco: grupo BIa UGL | Grés porcelânico técnico; NumeroDeRegistoDAP: EPD-REV-20240006-CCC1-EN; ReferenciaDAP: -; UrlDOP: -
Classification: C3010 (Uniformat)
Pset_CoveringCommon - TotalThickness: 8.5 mm
IFC.REVIGRÉS-Dados do fabricante-Floor Covering - Type: Floor: REVIGRÉS-LOCUS-BASE-29.5x59.2-SILK-BONE
IFC.REVIGRÉS-Dados de desempenho-Floor Covering - Type: Floor: REVIGRÉS-LOCUS-BASE-29.5x59.2-SILK-BONE
IFC.REVIGRÉS-Dados de especificação-Floor Covering - Type: Floor: REVIGRÉS-LOCUS-BASE-29.5x59.2-SILK-BONE
IFC.REVIGRÉS-Dados geométricos-Floor Covering - Type: Floor: REVIGRÉS-LOCUS-BASE-29.5x59.2-SILK-BONE
IFC.REVIGRÉS-Dados de sustentabilidade-Floor Covering - Type: Floor: REVIGRÉS-LOCUS-BASE-29.5x59.2-SILK-BONE

# IfcCovering: Floor:REVIGRÉS-LOCUS-BASE-29.5x59.2-SILK-GRIS, Floor:REVIGRÉS-LOCUS-BASE-29.5x59.2-SILK-GRIS:37324
In: Level 1
Type - PredefinedType: CLADDING; Material: REVIGRÉS-LOCUS-BASE-30x60-SILK-GRIS 8.5 mm
Type - Pset_CoveringCommon - Reference: 312G21V691; Material: Grés porcelânico
Type - Pset_ElementShading - Roughness: 304.8 mm
Type - Pset_ManufacturerTypeInformation - Manufacturer: REVIGRÉS
Type - Pset_ProductRequirements - Category: Floors
Type - Pset_QuantityTakeOff - Reference: 312G21V691
Type - IFC.REVIGRÉS-Dados do fabricante-Floor Covering - FabricanteURL: https://www.revigres.pt/; ReferenciaModelo: Locus; NumeroGlobalDeItemComercial: 312F21V671; Acabamento: SOFT; Material: Grés porcelânico; IdentificadorDoOperadorEconomico: 501840856; UrlFabricanteArtigo: https://www.revigres.pt/colecoes/locus; PaisOrigem: Portugal
Type - IFC.REVIGRÉS-Dados de desempenho-Floor Covering - Rectilinearidade: ± 0.2% máx ± 1.0 mm; Ortogonalidade: ± 0.2% máx.± 1.5 mm; PlanaridadeDaSuperficie: ± 0.3% máx. ± 1.8 mm; QualidadeDaSuperficie: Cumpre; AbsorcaoDeAgua: < 0.05%; ModuloDeRuptura: > 45 N/mm²; ResistenciaAFlexao: > 2000 N; ResistenciaAAbrasaoProfunda: < 120 mm³; DilatacaoTermicaLinear: ≤ 8,0x10-6 °C-1; ResistenciaAoChoqueTermico: Resiste; DurabilidadeInterior: Cumpre; DurabilidadeResistenciaAoGeloDegelo: Resiste; ResistenciaAoEscorregamentoDIN51130: R11; ResistenciaAoEscorregamentoDIN51097: A; ResistenciaAoEscorregamentoENV51097: A; ResistenciaAoEscorregamentoENV12633: Class 2; ResistenciaAoEscorregamentoBS7976: > 36; ResistenciaAoEscorregamentoANSIA1371: ≥0,42; ResistenciaAoDeslizamentoENV12633: Class 2; ResistenciaAoDeslizamentoBS7976: > 36; ResistenciaAsManchas: Class 5; LibertacaoDeCadmio: 0; LibertacaoDeChumbo: 0
Type - IFC.REVIGRÉS-Dados de especificação-Floor Covering - VariacaoTonalidade: 3; NivelDeTrafego: 5; EPavimento: Sim; ERevestimento: Sim; EExterno: Sim
Type - IFC.REVIGRÉS-Dados geométricos-Floor Covering - AlturaNominal: 8.5 mm; ComprimentoNominal: 29.5 mm; LarguraNominal: 59.2 mm
Type - IFC.REVIGRÉS-Dados de sustentabilidade-Floor Covering - ItemEParcialmenteReciclado: 0; EnergiaTermicaExportada: 0; ItemENovo: Sim; ItemEReciclado: Não; VidaÚtilEsperada: 50; SubstanciasPerigosas: Não; PotencialDeEsgotamentoAbioticoDosRecursosFosseis: 203; PotencialDeEsgotamentoAbioticoDosRecursosNaoFosseisMineraisEMetais: 0.000701; PotencialDeAquecimentoGlobalBiogenico: -0.48; CombustiveisFosseisComPotencialDeAquecimentoGlobal: 13.9; PotencialDeAquecimentoGlobalUsoDoSoloEMudancaDeUsoDoSolo: 0.0246; PotencialDeEutrofizacaoFraccaoDeNutrientesQueAtingemOCompartimentoFinalDeAguaDoce: 0.000189; PotencialDeEutrofizacaoFraccaoDeNutrientesQueAtingemOCompartimentoFinalMarinho: 0.0122; EnergiaRecuperada: 0.00739; ConsumoDeAguaDoce: 0.113; UtilizacaoLiquidaDeAguaDoce: 0.113; ResiduosPerigososEliminados: 0.00221; ResiduosNaoPerigososEliminados: 1.83; MassaTotalDeResiduosRadioactivosEliminados: 0.000394; EnergiaElectricaExportada: 1.55; MateriaisParaRecuperacaoDeEnergia: 0.00739; MateriaisParaReciclagem: 0.0253; UnidadeEPD: 1 m²
Type - IFC.REVIGRÉS-Dados gerais-Floor Covering - Nome: REVIGRÉS-LOCUS-BASE-29.5x59.2-SOFT GRIP-ALLOY; TipoProduto: Prensado a seco: grupo BIa UGL | Grés porcelânico técnico; NumeroDeRegistoDAP: EPD-REV-20240006-CCC1-EN; ReferenciaDAP: -; UrlDOP: -
Classification: C3010 (Uniformat)
Pset_CoveringCommon - TotalThickness: 8.5 mm
IFC.REVIGRÉS-Dados do fabricante-Floor Covering - Type: Floor: REVIGRÉS-LOCUS-BASE-29.5x59.2-SILK-GRIS
IFC.REVIGRÉS-Dados de desempenho-Floor Covering - Type: Floor: REVIGRÉS-LOCUS-BASE-29.5x59.2-SILK-GRIS
IFC.REVIGRÉS-Dados de especificação-Floor Covering - Type: Floor: REVIGRÉS-LOCUS-BASE-29.5x59.2-SILK-GRIS
IFC.REVIGRÉS-Dados geométricos-Floor Covering - Type: Floor: REVIGRÉS-LOCUS-BASE-29.5x59.2-SILK-GRIS
IFC.REVIGRÉS-Dados de sustentabilidade-Floor Covering - Type: Floor: REVIGRÉS-LOCUS-BASE-29.5x59.2-SILK-GRIS

# IfcCovering: Floor:REVIGRÉS-LOCUS-BASE-29.5x59.2-SILK-SMOG, Floor:REVIGRÉS-LOCUS-BASE-29.5x59.2-SILK-SMOG:37839
In: Level 1
Type - PredefinedType: CLADDING; Material: REVIGRÉS-LOCUS-BASE-30x60-SILK-SMOG 8.5 mm
Type - Pset_CoveringCommon - Reference: 312G21V701; Material: Grés porcelânico
Type - Pset_ElementShading - Roughness: 304.8 mm
Type - Pset_ManufacturerTypeInformation - Manufacturer: REVIGRÉS
Type - Pset_ProductRequirements - Category: Floors
Type - Pset_QuantityTakeOff - Reference: 312G21V701
Type - IFC.REVIGRÉS-Dados do fabricante-Floor Covering - FabricanteURL: https://www.revigres.pt/; ReferenciaModelo: Locus; NumeroGlobalDeItemComercial: 312F21V681; Acabamento: SOFT; Material: Grés porcelânico; IdentificadorDoOperadorEconomico: 501840856; UrlFabricanteArtigo: https://www.revigres.pt/colecoes/locus; PaisOrigem: Portugal
Type - IFC.REVIGRÉS-Dados de desempenho-Floor Covering - Rectilinearidade: ± 0.2% máx ± 1.0 mm; Ortogonalidade: ± 0.2% máx.± 1.5 mm; PlanaridadeDaSuperficie: ± 0.3% máx. ± 1.8 mm; QualidadeDaSuperficie: Cumpre; AbsorcaoDeAgua: < 0.05%; ModuloDeRuptura: > 45 N/mm²; ResistenciaAFlexao: > 2000 N; ResistenciaAAbrasaoProfunda: < 120 mm³; DilatacaoTermicaLinear: ≤ 8,0x10-6 °C-1; ResistenciaAoChoqueTermico: Resiste; DurabilidadeInterior: Cumpre; DurabilidadeResistenciaAoGeloDegelo: Resiste; ResistenciaAoEscorregamentoDIN51130: R11; ResistenciaAoEscorregamentoDIN51097: A; ResistenciaAoEscorregamentoENV51097: A; ResistenciaAoEscorregamentoENV12633: Class 2; ResistenciaAoEscorregamentoBS7976: > 36; ResistenciaAoEscorregamentoANSIA1371: ≥0,42; ResistenciaAoDeslizamentoENV12633: Class 2; ResistenciaAoDeslizamentoBS7976: > 36; ResistenciaAsManchas: Class 5; LibertacaoDeCadmio: 0; LibertacaoDeChumbo: 0
Type - IFC.REVIGRÉS-Dados de especificação-Floor Covering - VariacaoTonalidade: 3; NivelDeTrafego: 5; EPavimento: Sim; ERevestimento: Sim; EExterno: Sim
Type - IFC.REVIGRÉS-Dados geométricos-Floor Covering - AlturaNominal: 8.5 mm; ComprimentoNominal: 29.5 mm; LarguraNominal: 59.2 mm
Type - IFC.REVIGRÉS-Dados de sustentabilidade-Floor Covering - ItemEParcialmenteReciclado: 0; EnergiaTermicaExportada: 0; ItemENovo: Sim; ItemEReciclado: Não; VidaÚtilEsperada: 50; SubstanciasPerigosas: Não; PotencialDeEsgotamentoAbioticoDosRecursosFosseis: 203; PotencialDeEsgotamentoAbioticoDosRecursosNaoFosseisMineraisEMetais: 0.000701; PotencialDeAquecimentoGlobalBiogenico: -0.48; CombustiveisFosseisComPotencialDeAquecimentoGlobal: 13.9; PotencialDeAquecimentoGlobalUsoDoSoloEMudancaDeUsoDoSolo: 0.0246; PotencialDeEutrofizacaoFraccaoDeNutrientesQueAtingemOCompartimentoFinalDeAguaDoce: 0.000189; PotencialDeEutrofizacaoFraccaoDeNutrientesQueAtingemOCompartimentoFinalMarinho: 0.0122; EnergiaRecuperada: 0.00739; ConsumoDeAguaDoce: 0.113; UtilizacaoLiquidaDeAguaDoce: 0.113; ResiduosPerigososEliminados: 0.00221; ResiduosNaoPerigososEliminados: 1.83; MassaTotalDeResiduosRadioactivosEliminados: 0.000394; EnergiaElectricaExportada: 1.55; MateriaisParaRecuperacaoDeEnergia: 0.00739; MateriaisParaReciclagem: 0.0253; UnidadeEPD: 1 m²
Type - IFC.REVIGRÉS-Dados gerais-Floor Covering - Nome: REVIGRÉS-LOCUS-BASE-29.5x59.2-SOFT GRIP-BONE; TipoProduto: Prensado a seco: grupo BIa UGL | Grés porcelânico técnico; NumeroDeRegistoDAP: EPD-REV-20240006-CCC1-EN; ReferenciaDAP: -; UrlDOP: -
Classification: C3010 (Uniformat)
Pset_CoveringCommon - TotalThickness: 8.5 mm
IFC.REVIGRÉS-Dados do fabricante-Floor Covering - Type: Floor: REVIGRÉS-LOCUS-BASE-29.5x59.2-SILK-SMOG
IFC.REVIGRÉS-Dados de desempenho-Floor Covering - Type: Floor: REVIGRÉS-LOCUS-BASE-29.5x59.2-SILK-SMOG
IFC.REVIGRÉS-Dados de especificação-Floor Covering - Type: Floor: REVIGRÉS-LOCUS-BASE-29.5x59.2-SILK-SMOG
IFC.REVIGRÉS-Dados geométricos-Floor Covering - Type: Floor: REVIGRÉS-LOCUS-BASE-29.5x59.2-SILK-SMOG
IFC.REVIGRÉS-Dados de sustentabilidade-Floor Covering - Type: Floor: REVIGRÉS-LOCUS-BASE-29.5x59.2-SILK-SMOG

# IfcCovering: Floor:REVIGRÉS-LOCUS-BASE-29.5x59.2-SOFT GRIP-ALLOY, Floor:REVIGRÉS-LOCUS-BASE-29.5x59.2-SOFT GRIP-ALLOY:36062
In: Level 1
Type - PredefinedType: CLADDING; Material: REVIGRÉS-LOCUS-BASE-30x60-SOFT GRIP-ALLOY 8.5 mm
Type - Pset_CoveringCommon - Reference: 312F21V671; Material: Grés porcelânico
Type - Pset_ElementShading - Roughness: 304.8 mm
Type - Pset_ManufacturerTypeInformation - Manufacturer: REVIGRÉS
Type - Pset_ProductRequirements - Category: Floors
Type - Pset_QuantityTakeOff - Reference: 312F21V671
Type - IFC.REVIGRÉS-Dados do fabricante-Floor Covering - FabricanteURL: https://www.revigres.pt/; ReferenciaModelo: Locus; NumeroGlobalDeItemComercial: 312F21V691; Acabamento: SOFT; Material: Grés porcelânico; IdentificadorDoOperadorEconomico: 501840856; UrlFabricanteArtigo: https://www.revigres.pt/colecoes/locus; PaisOrigem: Portugal
Type - IFC.REVIGRÉS-Dados de desempenho-Floor Covering - Rectilinearidade: ± 0.2% máx ± 1.0 mm; Ortogonalidade: ± 0.2% máx.± 1.5 mm; PlanaridadeDaSuperficie: ± 0.3% máx. ± 1.8 mm; QualidadeDaSuperficie: Cumpre; AbsorcaoDeAgua: < 0.05%; ModuloDeRuptura: > 45 N/mm²; ResistenciaAFlexao: > 2000 N; ResistenciaAAbrasaoProfunda: < 120 mm³; DilatacaoTermicaLinear: ≤ 8,0x10-6 °C-1; ResistenciaAoChoqueTermico: Resiste; DurabilidadeInterior: Cumpre; DurabilidadeResistenciaAoGeloDegelo: Resiste; ResistenciaAoEscorregamentoDIN51130: R11; ResistenciaAoEscorregamentoDIN51097: A; ResistenciaAoEscorregamentoENV51097: A; ResistenciaAoEscorregamentoENV12633: Class 2; ResistenciaAoEscorregamentoBS7976: > 36; ResistenciaAoEscorregamentoANSIA1371: ≥0,42; ResistenciaAoDeslizamentoENV12633: Class 2; ResistenciaAoDeslizamentoBS7976: > 36; ResistenciaAsManchas: Class 5; LibertacaoDeCadmio: 0; LibertacaoDeChumbo: 0
Type - IFC.REVIGRÉS-Dados de especificação-Floor Covering - VariacaoTonalidade: 3; NivelDeTrafego: 5; EPavimento: Sim; ERevestimento: Sim; EExterno: Sim
Type - IFC.REVIGRÉS-Dados geométricos-Floor Covering - AlturaNominal: 8.5 mm; ComprimentoNominal: 29.5 mm; LarguraNominal: 59.2 mm
Type - IFC.REVIGRÉS-Dados de sustentabilidade-Floor Covering - EnergiaTermicaExportada: 0; ItemENovo: Sim; ItemEParcialmenteReciclado: 0.23; ItemEReciclado: Sim; VidaÚtilEsperada: 50; SubstanciasPerigosas: Não; PotencialDeEsgotamentoAbioticoDosRecursosFosseis: 203; PotencialDeEsgotamentoAbioticoDosRecursosNaoFosseisMineraisEMetais: 0.000701; PotencialDeAquecimentoGlobalBiogenico: -0.48; CombustiveisFosseisComPotencialDeAquecimentoGlobal: 13.9; PotencialDeAquecimentoGlobalUsoDoSoloEMudancaDeUsoDoSolo: 0.0246; PotencialDeEutrofizacaoFraccaoDeNutrientesQueAtingemOCompartimentoFinalDeAguaDoce: 0.000189; PotencialDeEutrofizacaoFraccaoDeNutrientesQueAtingemOCompartimentoFinalMarinho: 0.0122; EnergiaRecuperada: 0.00739; ConsumoDeAguaDoce: 0.113; UtilizacaoLiquidaDeAguaDoce: 0.113; ResiduosPerigososEliminados: 0.00221; ResiduosNaoPerigososEliminados: 1.83; MassaTotalDeResiduosRadioactivosEliminados: 0.000394; EnergiaElectricaExportada: 1.55; MateriaisParaRecuperacaoDeEnergia: 0.00739; MateriaisParaReciclagem: 0.0253; UnidadeEPD: 1 m²
Type - IFC.REVIGRÉS-Dados gerais-Floor Covering - Nome: REVIGRÉS-LOCUS-BASE-29.5x59.2-SOFT GRIP-GRIS; TipoProduto: Prensado a seco: grupo BIa UGL | Grés porcelânico técnico; NumeroDeRegistoDAP: EPD-REV-20240006-CCC1-EN; ReferenciaDAP: -; UrlDOP: -
Classification: C3010 (Uniformat)
Pset_CoveringCommon - TotalThickness: 8.5 mm
IFC.REVIGRÉS-Dados do fabricante-Floor Covering - Type: Floor: REVIGRÉS-LOCUS-BASE-29.5x59.2-SOFT GRIP-ALLOY
IFC.REVIGRÉS-Dados de desempenho-Floor Covering - Type: Floor: REVIGRÉS-LOCUS-BASE-29.5x59.2-SOFT GRIP-ALLOY
IFC.REVIGRÉS-Dados de especificação-Floor Covering - Type: Floor: REVIGRÉS-LOCUS-BASE-29.5x59.2-SOFT GRIP-ALLOY
IFC.REVIGRÉS-Dados geométricos-Floor Covering - Type: Floor: REVIGRÉS-LOCUS-BASE-29.5x59.2-SOFT GRIP-ALLOY
IFC.REVIGRÉS-Dados de sustentabilidade-Floor Covering - Type: Floor: REVIGRÉS-LOCUS-BASE-29.5x59.2-SOFT GRIP-ALLOY

# IfcCovering: Floor:REVIGRÉS-LOCUS-BASE-29.5x59.2-SOFT GRIP-SMOG, Floor:REVIGRÉS-LOCUS-BASE-29.5x59.2-SOFT GRIP-SMOG:37831
In: Level 1
Type - PredefinedType: CLADDING; Material: REVIGRÉS-LOCUS-BASE-30x60-SOFT GRIP-SMOG 8.5 mm
Type - Pset_CoveringCommon - Reference: 312F21V701; Material: Grés porcelânico
Type - Pset_ElementShading - Roughness: 304.8 mm
Type - Pset_ManufacturerTypeInformation - Manufacturer: REVIGRÉS
Type - Pset_ProductRequirements - Category: Floors
Type - Pset_QuantityTakeOff - Reference: 312F21V701
Type - IFC.REVIGRÉS-Dados do fabricante-Floor Covering - FabricanteURL: https://www.revigres.pt/; ReferenciaModelo: Locus; NumeroGlobalDeItemComercial: 312F21V701; Acabamento: SOFT; Material: Grés porcelânico; IdentificadorDoOperadorEconomico: 501840856; UrlFabricanteArtigo: https://www.revigres.pt/colecoes/locus; PaisOrigem: Portugal
Type - IFC.REVIGRÉS-Dados de desempenho-Floor Covering - Rectilinearidade: ± 0.2% máx ± 1.0 mm; Ortogonalidade: ± 0.2% máx.± 1.5 mm; PlanaridadeDaSuperficie: ± 0.3% máx. ± 1.8 mm; QualidadeDaSuperficie: Cumpre; AbsorcaoDeAgua: < 0.05%; ModuloDeRuptura: > 45 N/mm²; ResistenciaAFlexao: > 2000 N; ResistenciaAAbrasaoProfunda: < 120 mm³; DilatacaoTermicaLinear: ≤ 8,0x10-6 °C-1; ResistenciaAoChoqueTermico: Resiste; DurabilidadeInterior: Cumpre; DurabilidadeResistenciaAoGeloDegelo: Resiste; ResistenciaAoEscorregamentoDIN51130: R11; ResistenciaAoEscorregamentoDIN51097: A; ResistenciaAoEscorregamentoENV51097: A; ResistenciaAoEscorregamentoENV12633: Class 2; ResistenciaAoEscorregamentoBS7976: > 36; ResistenciaAoEscorregamentoANSIA1371: ≥0,42; ResistenciaAoDeslizamentoENV12633: Class 2; ResistenciaAoDeslizamentoBS7976: > 36; ResistenciaAsManchas: Class 5; LibertacaoDeCadmio: 0; LibertacaoDeChumbo: 0
Type - IFC.REVIGRÉS-Dados de especificação-Floor Covering - VariacaoTonalidade: 3; NivelDeTrafego: 5; EPavimento: Sim; ERevestimento: Sim; EExterno: Sim
Type - IFC.REVIGRÉS-Dados geométricos-Floor Covering - AlturaNominal: 8.5 mm; ComprimentoNominal: 29.5 mm; LarguraNominal: 59.2 mm
Type - IFC.REVIGRÉS-Dados de sustentabilidade-Floor Covering - EnergiaTermicaExportada: 0; ItemENovo: Sim; ItemEParcialmenteReciclado: 0.29; ItemEReciclado: Sim; VidaÚtilEsperada: 50; SubstanciasPerigosas: Não; PotencialDeEsgotamentoAbioticoDosRecursosFosseis: 203; PotencialDeEsgotamentoAbioticoDosRecursosNaoFosseisMineraisEMetais: 0.000701; PotencialDeAquecimentoGlobalBiogenico: -0.48; CombustiveisFosseisComPotencialDeAquecimentoGlobal: 13.9; PotencialDeAquecimentoGlobalUsoDoSoloEMudancaDeUsoDoSolo: 0.0246; PotencialDeEutrofizacaoFraccaoDeNutrientesQueAtingemOCompartimentoFinalDeAguaDoce: 0.000189; PotencialDeEutrofizacaoFraccaoDeNutrientesQueAtingemOCompartimentoFinalMarinho: 0.0122; EnergiaRecuperada: 0.00739; ConsumoDeAguaDoce: 0.113; UtilizacaoLiquidaDeAguaDoce: 0.113; ResiduosPerigososEliminados: 0.00221; ResiduosNaoPerigososEliminados: 1.83; MassaTotalDeResiduosRadioactivosEliminados: 0.000394; EnergiaElectricaExportada: 1.55; MateriaisParaRecuperacaoDeEnergia: 0.00739; MateriaisParaReciclagem: 0.0253; UnidadeEPD: 1 m²
Type - IFC.REVIGRÉS-Dados gerais-Floor Covering - Nome: REVIGRÉS-LOCUS-BASE-29.5x59.2-SOFT GRIP-SMOG; TipoProduto: Prensado a seco: grupo BIa UGL | Grés porcelânico técnico; NumeroDeRegistoDAP: EPD-REV-20240006-CCC1-EN; ReferenciaDAP: -; UrlDOP: -
Classification: C3010 (Uniformat)
Pset_CoveringCommon - TotalThickness: 8.5 mm
IFC.REVIGRÉS-Dados do fabricante-Floor Covering - Type: Floor: REVIGRÉS-LOCUS-BASE-29.5x59.2-SOFT GRIP-SMOG
IFC.REVIGRÉS-Dados de desempenho-Floor Covering - Type: Floor: REVIGRÉS-LOCUS-BASE-29.5x59.2-SOFT GRIP-SMOG
IFC.REVIGRÉS-Dados de especificação-Floor Covering - Type: Floor: REVIGRÉS-LOCUS-BASE-29.5x59.2-SOFT GRIP-SMOG
IFC.REVIGRÉS-Dados geométricos-Floor Covering - Type: Floor: REVIGRÉS-LOCUS-BASE-29.5x59.2-SOFT GRIP-SMOG
IFC.REVIGRÉS-Dados de sustentabilidade-Floor Covering - Type: Floor: REVIGRÉS-LOCUS-BASE-29.5x59.2-SOFT GRIP-SMOG

# IfcCovering: Floor:REVIGRÉS-LOCUS-BASE-29.5x59.20-SOFT GRIP-BONE, Floor:REVIGRÉS-LOCUS-BASE-29.5x59.20-SOFT GRIP-BONE:36643
In: Level 1
Type - PredefinedType: CLADDING; Material: REVIGRÉS-LOCUS-BASE-30x60-SOFT GRIP-BONE 8.5 mm
Type - Pset_CoveringCommon - Reference: 312F21V681; Material: Grés porcelânico
Type - Pset_ElementShading - Roughness: 304.8 mm
Type - Pset_ManufacturerTypeInformation - Manufacturer: REVIGRÉS
Type - Pset_ProductRequirements - Category: Floors
Type - Pset_QuantityTakeOff - Reference: 312F21V681
Type - IFC.REVIGRÉS-Dados do fabricante-Floor Covering - FabricanteURL: https://www.revigres.pt/; ReferenciaModelo: Locus; NumeroGlobalDeItemComercial: 312G21V671; Acabamento: SILK; Material: Grés porcelânico; IdentificadorDoOperadorEconomico: 501840856; UrlFabricanteArtigo: https://www.revigres.pt/colecoes/locus; PaisOrigem: Portugal
Type - IFC.REVIGRÉS-Dados de desempenho-Floor Covering - Rectilinearidade: ± 0.2% máx.± 0.8 mm; Ortogonalidade: ± 0.2% máx.± 1.5 mm; PlanaridadeDaSuperficie: ± 0.3% máx. ± 1.8 mm; QualidadeDaSuperficie: Cumpre; AbsorcaoDeAgua: < 0.05%; ModuloDeRuptura: > 45 N/mm²; ResistenciaAFlexao: > 2000 N; ResistenciaAAbrasaoProfunda: < 120 mm³; DilatacaoTermicaLinear: ≤ 8,0x10-6 °C-1; ResistenciaAoChoqueTermico: Resiste; DurabilidadeInterior: Cumpre; DurabilidadeResistenciaAoGeloDegelo: Resiste; ResistenciaAoEscorregamentoDIN51130: R9; ResistenciaAoEscorregamentoDIN51097: A; ResistenciaAoEscorregamentoENV51097: A; ResistenciaAoEscorregamentoENV12633: Class 1; ResistenciaAoEscorregamentoBS7976: -; ResistenciaAoEscorregamentoANSIA1371: ≥0,42; ResistenciaAoDeslizamentoENV12633: Class 1; ResistenciaAoDeslizamentoBS7976: -; ResistenciaAsManchas: Class 5; LibertacaoDeCadmio: 0; LibertacaoDeChumbo: 0
Type - IFC.REVIGRÉS-Dados de especificação-Floor Covering - VariacaoTonalidade: 3; NivelDeTrafego: 5; EPavimento: Sim; ERevestimento: Sim; EExterno: Sim
Type - IFC.REVIGRÉS-Dados geométricos-Floor Covering - AlturaNominal: 8.5 mm; ComprimentoNominal: 29.5 mm; LarguraNominal: 59.2 mm
Type - IFC.REVIGRÉS-Dados de sustentabilidade-Floor Covering - ItemEParcialmenteReciclado: 0; EnergiaTermicaExportada: 0; ItemENovo: Sim; ItemEReciclado: Não; VidaÚtilEsperada: 50; SubstanciasPerigosas: Não; PotencialDeEsgotamentoAbioticoDosRecursosFosseis: 203; PotencialDeEsgotamentoAbioticoDosRecursosNaoFosseisMineraisEMetais: 0.000701; PotencialDeAquecimentoGlobalBiogenico: -0.48; CombustiveisFosseisComPotencialDeAquecimentoGlobal: 13.9; PotencialDeAquecimentoGlobalUsoDoSoloEMudancaDeUsoDoSolo: 0.0246; PotencialDeEutrofizacaoFraccaoDeNutrientesQueAtingemOCompartimentoFinalDeAguaDoce: 0.000189; PotencialDeEutrofizacaoFraccaoDeNutrientesQueAtingemOCompartimentoFinalMarinho: 0.0122; EnergiaRecuperada: 0.00739; ConsumoDeAguaDoce: 0.113; UtilizacaoLiquidaDeAguaDoce: 0.113; ResiduosPerigososEliminados: 0.00221; ResiduosNaoPerigososEliminados: 1.83; MassaTotalDeResiduosRadioactivosEliminados: 0.000394; EnergiaElectricaExportada: 1.55; MateriaisParaRecuperacaoDeEnergia: 0.00739; MateriaisParaReciclagem: 0.0253; UnidadeEPD: 1 m²
Type - IFC.REVIGRÉS-Dados gerais-Floor Covering - Nome: REVIGRÉS-LOCUS-BASE-29.5x59.2-SILK-ALLOY; TipoProduto: Prensado a seco: grupo BIa UGL | Grés porcelânico técnico; NumeroDeRegistoDAP: EPD-REV-20240006-CCC1-EN; ReferenciaDAP: -; UrlDOP: -
Classification: C3010 (Uniformat)
Pset_CoveringCommon - TotalThickness: 8.5 mm
IFC.REVIGRÉS-Dados do fabricante-Floor Covering - Type: Floor: REVIGRÉS-LOCUS-BASE-29.5x59.20-SOFT GRIP-BONE
IFC.REVIGRÉS-Dados de desempenho-Floor Covering - Type: Floor: REVIGRÉS-LOCUS-BASE-29.5x59.20-SOFT GRIP-BONE
IFC.REVIGRÉS-Dados de especificação-Floor Covering - Type: Floor: REVIGRÉS-LOCUS-BASE-29.5x59.20-SOFT GRIP-BONE
IFC.REVIGRÉS-Dados geométricos-Floor Covering - Type: Floor: REVIGRÉS-LOCUS-BASE-29.5x59.20-SOFT GRIP-BONE
IFC.REVIGRÉS-Dados de sustentabilidade-Floor Covering - Type: Floor: REVIGRÉS-LOCUS-BASE-29.5x59.20-SOFT GRIP-BONE

# IfcCovering: Floor:REVIGRÉS-LOCUS-BASE-29.5x59.20-SOFT GRIP-GRIS, Floor:REVIGRÉS-LOCUS-BASE-29.5x59.20-SOFT GRIP-GRIS:37316
In: Level 1
Type - PredefinedType: CLADDING; Material: REVIGRÉS-LOCUS-BASE-30x60-SOFT GRIP-GRIS 8.5 mm
Type - Pset_CoveringCommon - Reference: 312F21V691; Material: Grés porcelânico
Type - Pset_ElementShading - Roughness: 304.8 mm
Type - Pset_ManufacturerTypeInformation - Manufacturer: REVIGRÉS
Type - Pset_ProductRequirements - Category: Floors
Type - Pset_QuantityTakeOff - Reference: 312F21V691
Type - IFC.REVIGRÉS-Dados do fabricante-Floor Covering - FabricanteURL: https://www.revigres.pt/; ReferenciaModelo: Locus; NumeroGlobalDeItemComercial: 312G21V681; Acabamento: SILK; Material: Grés porcelânico; IdentificadorDoOperadorEconomico: 501840856; UrlFabricanteArtigo: https://www.revigres.pt/colecoes/locus; PaisOrigem: Portugal
Type - IFC.REVIGRÉS-Dados de desempenho-Floor Covering - Rectilinearidade: ± 0.2% máx.± 0.8 mm; Ortogonalidade: ± 0.2% máx.± 1.5 mm; PlanaridadeDaSuperficie: ± 0.3% máx. ± 1.8 mm; QualidadeDaSuperficie: Cumpre; AbsorcaoDeAgua: < 0.05%; ModuloDeRuptura: > 45 N/mm²; ResistenciaAFlexao: > 2000 N; ResistenciaAAbrasaoProfunda: < 120 mm³; DilatacaoTermicaLinear: ≤ 8,0x10-6 °C-1; ResistenciaAoChoqueTermico: Resiste; DurabilidadeInterior: Cumpre; DurabilidadeResistenciaAoGeloDegelo: Resiste; ResistenciaAoEscorregamentoDIN51130: R9; ResistenciaAoEscorregamentoDIN51097: A; ResistenciaAoEscorregamentoENV51097: A; ResistenciaAoEscorregamentoENV12633: Class 1; ResistenciaAoEscorregamentoBS7976: -; ResistenciaAoEscorregamentoANSIA1371: ≥0,42; ResistenciaAoDeslizamentoENV12633: Class 1; ResistenciaAoDeslizamentoBS7976: -; ResistenciaAsManchas: Class 5; LibertacaoDeCadmio: 0; LibertacaoDeChumbo: 0
Type - IFC.REVIGRÉS-Dados de especificação-Floor Covering - VariacaoTonalidade: 3; NivelDeTrafego: 5; EPavimento: Sim; ERevestimento: Sim; EExterno: Sim
Type - IFC.REVIGRÉS-Dados geométricos-Floor Covering - AlturaNominal: 8.5 mm; ComprimentoNominal: 29.5 mm; LarguraNominal: 59.2 mm
Type - IFC.REVIGRÉS-Dados de sustentabilidade-Floor Covering - ItemEParcialmenteReciclado: 0; EnergiaTermicaExportada: 0; ItemENovo: Sim; ItemEReciclado: Não; VidaÚtilEsperada: 50; SubstanciasPerigosas: Não; PotencialDeEsgotamentoAbioticoDosRecursosFosseis: 203; PotencialDeEsgotamentoAbioticoDosRecursosNaoFosseisMineraisEMetais: 0.000701; PotencialDeAquecimentoGlobalBiogenico: -0.48; CombustiveisFosseisComPotencialDeAquecimentoGlobal: 13.9; PotencialDeAquecimentoGlobalUsoDoSoloEMudancaDeUsoDoSolo: 0.0246; PotencialDeEutrofizacaoFraccaoDeNutrientesQueAtingemOCompartimentoFinalDeAguaDoce: 0.000189; PotencialDeEutrofizacaoFraccaoDeNutrientesQueAtingemOCompartimentoFinalMarinho: 0.0122; EnergiaRecuperada: 0.00739; ConsumoDeAguaDoce: 0.113; UtilizacaoLiquidaDeAguaDoce: 0.113; ResiduosPerigososEliminados: 0.00221; ResiduosNaoPerigososEliminados: 1.83; MassaTotalDeResiduosRadioactivosEliminados: 0.000394; EnergiaElectricaExportada: 1.55; MateriaisParaRecuperacaoDeEnergia: 0.00739; MateriaisParaReciclagem: 0.0253; UnidadeEPD: 1 m²
Type - IFC.REVIGRÉS-Dados gerais-Floor Covering - Nome: REVIGRÉS-LOCUS-BASE-29.5x59.2-SILK-BONE; TipoProduto: Prensado a seco: grupo BIa UGL | Grés porcelânico técnico; NumeroDeRegistoDAP: EPD-REV-20240006-CCC1-EN; ReferenciaDAP: -; UrlDOP: -
Classification: C3010 (Uniformat)
Pset_CoveringCommon - TotalThickness: 8.5 mm
IFC.REVIGRÉS-Dados do fabricante-Floor Covering - Type: Floor: REVIGRÉS-LOCUS-BASE-29.5x59.20-SOFT GRIP-GRIS
IFC.REVIGRÉS-Dados de desempenho-Floor Covering - Type: Floor: REVIGRÉS-LOCUS-BASE-29.5x59.20-SOFT GRIP-GRIS
IFC.REVIGRÉS-Dados de especificação-Floor Covering - Type: Floor: REVIGRÉS-LOCUS-BASE-29.5x59.20-SOFT GRIP-GRIS
IFC.REVIGRÉS-Dados geométricos-Floor Covering - Type: Floor: REVIGRÉS-LOCUS-BASE-29.5x59.20-SOFT GRIP-GRIS
IFC.REVIGRÉS-Dados de sustentabilidade-Floor Covering - Type: Floor: REVIGRÉS-LOCUS-BASE-29.5x59.20-SOFT GRIP-GRIS

# IfcCovering: Floor:REVIGRÉS-LOCUS-BASE-44.35x88.9-SILK-ALLOY, Floor:REVIGRÉS-LOCUS-BASE-44.35x88.9-SILK-ALLOY:36377
In: Level 1
Type - PredefinedType: CLADDING; Material: REVIGRÉS-LOCUS-BASE-45X90-SILK-ALLOY 10.5 mm
Type - Pset_CoveringCommon - Reference: 312GH8V671; Material: Grés porcelânico
Type - Pset_ElementShading - Roughness: 304.8 mm
Type - Pset_ManufacturerTypeInformation - Manufacturer: REVIGRÉS
Type - Pset_ProductRequirements - Category: Floors
Type - Pset_QuantityTakeOff - Reference: 312GH8V671
Type - IFC.REVIGRÉS-Dados do fabricante-Floor Covering - FabricanteURL: https://www.revigres.pt/; ReferenciaModelo: Locus; NumeroGlobalDeItemComercial: 312GH8V671; Acabamento: SILK; Material: Grés porcelânico; IdentificadorDoOperadorEconomico: 501840856; UrlFabricanteArtigo: https://www.revigres.pt/colecoes/locus; PaisOrigem: Portugal
Type - IFC.REVIGRÉS-Dados de desempenho-Floor Covering - Rectilinearidade: ± 0.2% máx.± 0.8 mm; Ortogonalidade: ± 0.2% máx.± 1.5 mm; PlanaridadeDaSuperficie: ± 0.3% máx. ± 1.8 mm; QualidadeDaSuperficie: Cumpre; AbsorcaoDeAgua: < 0.05%; ModuloDeRuptura: > 45 N/mm²; ResistenciaAFlexao: > 2000 N; ResistenciaAAbrasaoProfunda: < 120 mm³; DilatacaoTermicaLinear: ≤ 8,0x10-6 °C-1; ResistenciaAoChoqueTermico: Resiste; DurabilidadeInterior: Cumpre; DurabilidadeResistenciaAoGeloDegelo: Resiste; ResistenciaAoEscorregamentoDIN51130: R9; ResistenciaAoEscorregamentoDIN51097: A; ResistenciaAoEscorregamentoENV51097: A; ResistenciaAoEscorregamentoENV12633: Class 1; ResistenciaAoEscorregamentoBS7976: -; ResistenciaAoEscorregamentoANSIA1371: ≥0,42; ResistenciaAoDeslizamentoENV12633: Class 1; ResistenciaAoDeslizamentoBS7976: -; ResistenciaAsManchas: Class 5; LibertacaoDeCadmio: 0; LibertacaoDeChumbo: 0
Type - IFC.REVIGRÉS-Dados de especificação-Floor Covering - VariacaoTonalidade: 3; NivelDeTrafego: 5; EPavimento: Sim; ERevestimento: Sim; EExterno: Sim
Type - IFC.REVIGRÉS-Dados geométricos-Floor Covering - AlturaNominal: 10.5 mm; ComprimentoNominal: 44.35 mm; LarguraNominal: 88.9 mm
Type - IFC.REVIGRÉS-Dados de sustentabilidade-Floor Covering - ItemEParcialmenteReciclado: 0; EnergiaTermicaExportada: 0; ItemENovo: Sim; ItemEReciclado: Não; VidaÚtilEsperada: 50; SubstanciasPerigosas: Não; PotencialDeEsgotamentoAbioticoDosRecursosFosseis: 203; PotencialDeEsgotamentoAbioticoDosRecursosNaoFosseisMineraisEMetais: 0.000701; PotencialDeAquecimentoGlobalBiogenico: -0.48; CombustiveisFosseisComPotencialDeAquecimentoGlobal: 13.9; PotencialDeAquecimentoGlobalUsoDoSoloEMudancaDeUsoDoSolo: 0.0246; PotencialDeEutrofizacaoFraccaoDeNutrientesQueAtingemOCompartimentoFinalDeAguaDoce: 0.000189; PotencialDeEutrofizacaoFraccaoDeNutrientesQueAtingemOCompartimentoFinalMarinho: 0.0122; EnergiaRecuperada: 0.00739; ConsumoDeAguaDoce: 0.113; UtilizacaoLiquidaDeAguaDoce: 0.113; ResiduosPerigososEliminados: 0.00221; ResiduosNaoPerigososEliminados: 1.83; MassaTotalDeResiduosRadioactivosEliminados: 0.000394; EnergiaElectricaExportada: 1.55; MateriaisParaRecuperacaoDeEnergia: 0.00739; MateriaisParaReciclagem: 0.0253; UnidadeEPD: 1 m²
Type - IFC.REVIGRÉS-Dados gerais-Floor Covering - Nome: REVIGRÉS-LOCUS-BASE-44.35x88.9-SILK-ALLOY; TipoProduto: Prensado a seco: grupo BIa UGL | Grés porcelânico técnico; NumeroDeRegistoDAP: EPD-REV-20240006-CCC1-EN; ReferenciaDAP: -; UrlDOP: -
Classification: C3010 (Uniformat)
Pset_CoveringCommon - TotalThickness: 10.5 mm
IFC.REVIGRÉS-Dados do fabricante-Floor Covering - Type: Floor: REVIGRÉS-LOCUS-BASE-44.35x88.9-SILK-ALLOY
IFC.REVIGRÉS-Dados de desempenho-Floor Covering - Type: Floor: REVIGRÉS-LOCUS-BASE-44.35x88.9-SILK-ALLOY
IFC.REVIGRÉS-Dados de especificação-Floor Covering - Type: Floor: REVIGRÉS-LOCUS-BASE-44.35x88.9-SILK-ALLOY
IFC.REVIGRÉS-Dados geométricos-Floor Covering - Type: Floor: REVIGRÉS-LOCUS-BASE-44.35x88.9-SILK-ALLOY
IFC.REVIGRÉS-Dados de sustentabilidade-Floor Covering - Type: Floor: REVIGRÉS-LOCUS-BASE-44.35x88.9-SILK-ALLOY

# IfcCovering: Floor:REVIGRÉS-LOCUS-BASE-44.35x88.9-SILK-BONE, Floor:REVIGRÉS-LOCUS-BASE-44.35x88.9-SILK-BONE:36705
In: Level 1
Type - PredefinedType: CLADDING; Material: REVIGRÉS-LOCUS-BASE-45X90-SILK-BONE 10.5 mm
Type - Pset_CoveringCommon - Reference: 312GH8V681; Material: Grés porcelânico
Type - Pset_ElementShading - Roughness: 304.8 mm
Type - Pset_ManufacturerTypeInformation - Manufacturer: REVIGRÉS
Type - Pset_ProductRequirements - Category: Floors
Type - Pset_QuantityTakeOff - Reference: 312GH8V681
Type - IFC.REVIGRÉS-Dados do fabricante-Floor Covering - FabricanteURL: https://www.revigres.pt/; ReferenciaModelo: Locus; NumeroGlobalDeItemComercial: 312GH8V681; Acabamento: SILK; Material: Grés porcelânico; IdentificadorDoOperadorEconomico: 501840856; UrlFabricanteArtigo: https://www.revigres.pt/colecoes/locus; PaisOrigem: Portugal
Type - IFC.REVIGRÉS-Dados de desempenho-Floor Covering - Rectilinearidade: ± 0.2% máx.± 0.8 mm; Ortogonalidade: ± 0.2% máx.± 1.5 mm; PlanaridadeDaSuperficie: ± 0.3% máx. ± 1.8 mm; QualidadeDaSuperficie: Cumpre; AbsorcaoDeAgua: < 0.05%; ModuloDeRuptura: > 45 N/mm²; ResistenciaAFlexao: > 2000 N; ResistenciaAAbrasaoProfunda: < 120 mm³; DilatacaoTermicaLinear: ≤ 8,0x10-6 °C-1; ResistenciaAoChoqueTermico: Resiste; DurabilidadeInterior: Cumpre; DurabilidadeResistenciaAoGeloDegelo: Resiste; ResistenciaAoEscorregamentoDIN51130: R9; ResistenciaAoEscorregamentoDIN51097: A; ResistenciaAoEscorregamentoENV51097: A; ResistenciaAoEscorregamentoENV12633: Class 1; ResistenciaAoEscorregamentoBS7976: -; ResistenciaAoEscorregamentoANSIA1371: ≥0,42; ResistenciaAoDeslizamentoENV12633: Class 1; ResistenciaAoDeslizamentoBS7976: -; ResistenciaAsManchas: Class 5; LibertacaoDeCadmio: 0; LibertacaoDeChumbo: 0
Type - IFC.REVIGRÉS-Dados de especificação-Floor Covering - VariacaoTonalidade: 3; NivelDeTrafego: 5; EPavimento: Sim; ERevestimento: Sim; EExterno: Sim
Type - IFC.REVIGRÉS-Dados geométricos-Floor Covering - AlturaNominal: 10.5 mm; ComprimentoNominal: 44.35 mm; LarguraNominal: 88.9 mm
Type - IFC.REVIGRÉS-Dados de sustentabilidade-Floor Covering - ItemEParcialmenteReciclado: 0; EnergiaTermicaExportada: 0; ItemENovo: Sim; ItemEReciclado: Não; VidaÚtilEsperada: 50; SubstanciasPerigosas: Não; PotencialDeEsgotamentoAbioticoDosRecursosFosseis: 203; PotencialDeEsgotamentoAbioticoDosRecursosNaoFosseisMineraisEMetais: 0.000701; PotencialDeAquecimentoGlobalBiogenico: -0.48; CombustiveisFosseisComPotencialDeAquecimentoGlobal: 13.9; PotencialDeAquecimentoGlobalUsoDoSoloEMudancaDeUsoDoSolo: 0.0246; PotencialDeEutrofizacaoFraccaoDeNutrientesQueAtingemOCompartimentoFinalDeAguaDoce: 0.000189; PotencialDeEutrofizacaoFraccaoDeNutrientesQueAtingemOCompartimentoFinalMarinho: 0.0122; EnergiaRecuperada: 0.00739; ConsumoDeAguaDoce: 0.113; UtilizacaoLiquidaDeAguaDoce: 0.113; ResiduosPerigososEliminados: 0.00221; ResiduosNaoPerigososEliminados: 1.83; MassaTotalDeResiduosRadioactivosEliminados: 0.000394; EnergiaElectricaExportada: 1.55; MateriaisParaRecuperacaoDeEnergia: 0.00739; MateriaisParaReciclagem: 0.0253; UnidadeEPD: 1 m²
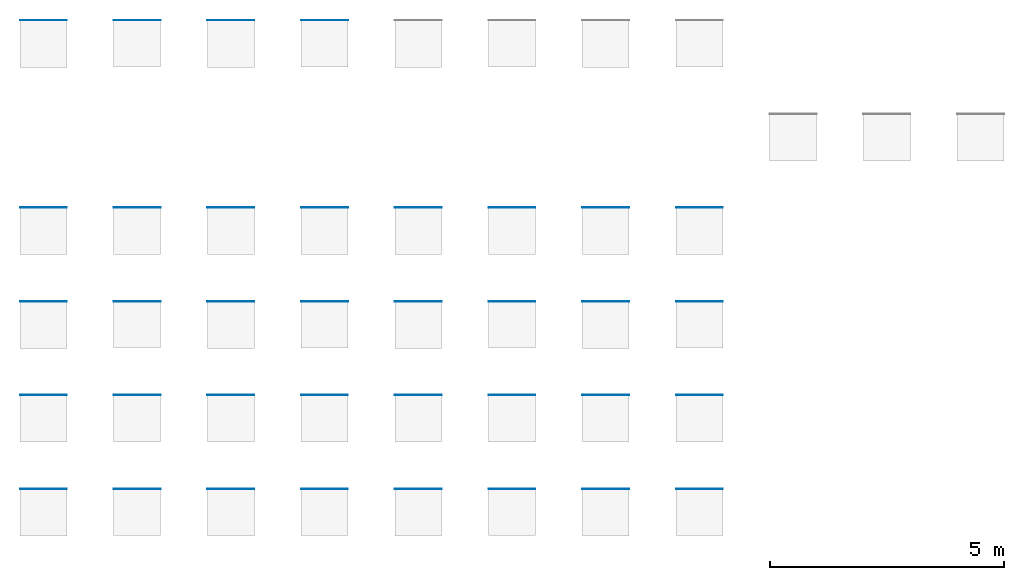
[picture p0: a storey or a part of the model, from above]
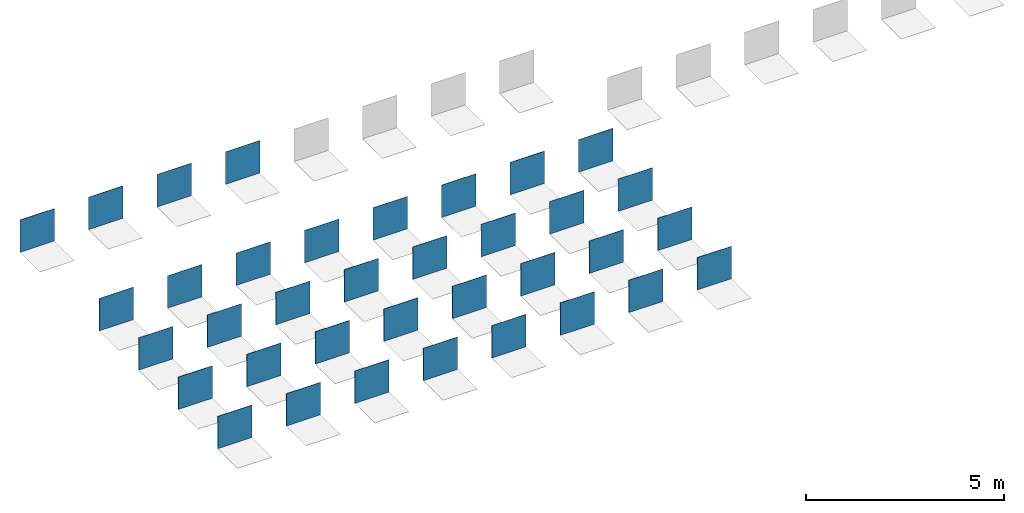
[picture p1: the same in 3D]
Properties of the parts of a building model (IFC2X3), part 2 of 7

# IfcCovering: Floor:REVIGRÉS-LOCUS-BASE-44.35x88.9-SILK-BONE, Floor:REVIGRÉS-LOCUS-BASE-44.35x88.9-SILK-BONE:36705
Type - IFC.REVIGRÉS-Dados gerais-Floor Covering - Nome: REVIGRÉS-LOCUS-BASE-44.35x88.9-SILK-BONE; TipoProduto: Prensado a seco: grupo BIa UGL | Grés porcelânico técnico; NumeroDeRegistoDAP: EPD-REV-20240006-CCC1-EN; ReferenciaDAP: -; UrlDOP: -
Classification: C3010 (Uniformat)
Pset_CoveringCommon - TotalThickness: 10.5 mm
IFC.REVIGRÉS-Dados do fabricante-Floor Covering - Type: Floor: REVIGRÉS-LOCUS-BASE-44.35x88.9-SILK-BONE
IFC.REVIGRÉS-Dados de desempenho-Floor Covering - Type: Floor: REVIGRÉS-LOCUS-BASE-44.35x88.9-SILK-BONE
IFC.REVIGRÉS-Dados de especificação-Floor Covering - Type: Floor: REVIGRÉS-LOCUS-BASE-44.35x88.9-SILK-BONE
IFC.REVIGRÉS-Dados geométricos-Floor Covering - Type: Floor: REVIGRÉS-LOCUS-BASE-44.35x88.9-SILK-BONE
IFC.REVIGRÉS-Dados de sustentabilidade-Floor Covering - Type: Floor: REVIGRÉS-LOCUS-BASE-44.35x88.9-SILK-BONE

# IfcCovering: Floor:REVIGRÉS-LOCUS-BASE-44.35x88.9-SILK-GRIS, Floor:REVIGRÉS-LOCUS-BASE-44.35x88.9-SILK-GRIS:37372
In: Level 1
Type - PredefinedType: CLADDING; Material: REVIGRÉS-LOCUS-BASE-45X90-SILK-GRIS 10.5 mm
Type - Pset_CoveringCommon - Reference: 312GH8V691; Material: Grés porcelânico
Type - Pset_ElementShading - Roughness: 304.8 mm
Type - Pset_ManufacturerTypeInformation - Manufacturer: REVIGRÉS
Type - Pset_ProductRequirements - Category: Floors
Type - Pset_QuantityTakeOff - Reference: 312GH8V691
Type - IFC.REVIGRÉS-Dados do fabricante-Floor Covering - FabricanteURL: https://www.revigres.pt/; ReferenciaModelo: Locus; NumeroGlobalDeItemComercial: 312GH8V691; Acabamento: SILK; Material: Grés porcelânico; IdentificadorDoOperadorEconomico: 501840856; UrlFabricanteArtigo: https://www.revigres.pt/colecoes/locus; PaisOrigem: Portugal
Type - IFC.REVIGRÉS-Dados de desempenho-Floor Covering - Rectilinearidade: ± 0.2% máx.± 0.8 mm; Ortogonalidade: ± 0.2% máx.± 1.5 mm; PlanaridadeDaSuperficie: ± 0.3% máx. ± 1.8 mm; QualidadeDaSuperficie: Cumpre; AbsorcaoDeAgua: < 0.05%; ModuloDeRuptura: > 45 N/mm²; ResistenciaAFlexao: > 2000 N; ResistenciaAAbrasaoProfunda: < 120 mm³; DilatacaoTermicaLinear: ≤ 8,0x10-6 °C-1; ResistenciaAoChoqueTermico: Resiste; DurabilidadeInterior: Cumpre; DurabilidadeResistenciaAoGeloDegelo: Resiste; ResistenciaAoEscorregamentoDIN51130: R9; ResistenciaAoEscorregamentoDIN51097: A; ResistenciaAoEscorregamentoENV51097: A; ResistenciaAoEscorregamentoENV12633: Class 1; ResistenciaAoEscorregamentoBS7976: -; ResistenciaAoEscorregamentoANSIA1371: ≥0,42; ResistenciaAoDeslizamentoENV12633: Class 1; ResistenciaAoDeslizamentoBS7976: -; ResistenciaAsManchas: Class 5; LibertacaoDeCadmio: 0; LibertacaoDeChumbo: 0
Type - IFC.REVIGRÉS-Dados de especificação-Floor Covering - VariacaoTonalidade: 3; NivelDeTrafego: 5; EPavimento: Sim; ERevestimento: Sim; EExterno: Sim
Type - IFC.REVIGRÉS-Dados geométricos-Floor Covering - AlturaNominal: 10.5 mm; ComprimentoNominal: 44.35 mm; LarguraNominal: 88.9 mm
Type - IFC.REVIGRÉS-Dados de sustentabilidade-Floor Covering - EnergiaTermicaExportada: 0; ItemENovo: Sim; ItemEParcialmenteReciclado: 0.23; ItemEReciclado: Sim; VidaÚtilEsperada: 50; SubstanciasPerigosas: Não; PotencialDeEsgotamentoAbioticoDosRecursosFosseis: 203; PotencialDeEsgotamentoAbioticoDosRecursosNaoFosseisMineraisEMetais: 0.000701; PotencialDeAquecimentoGlobalBiogenico: -0.48; CombustiveisFosseisComPotencialDeAquecimentoGlobal: 13.9; PotencialDeAquecimentoGlobalUsoDoSoloEMudancaDeUsoDoSolo: 0.0246; PotencialDeEutrofizacaoFraccaoDeNutrientesQueAtingemOCompartimentoFinalDeAguaDoce: 0.000189; PotencialDeEutrofizacaoFraccaoDeNutrientesQueAtingemOCompartimentoFinalMarinho: 0.0122; EnergiaRecuperada: 0.00739; ConsumoDeAguaDoce: 0.113; UtilizacaoLiquidaDeAguaDoce: 0.113; ResiduosPerigososEliminados: 0.00221; ResiduosNaoPerigososEliminados: 1.83; MassaTotalDeResiduosRadioactivosEliminados: 0.000394; EnergiaElectricaExportada: 1.55; MateriaisParaRecuperacaoDeEnergia: 0.00739; MateriaisParaReciclagem: 0.0253; UnidadeEPD: 1 m²
Type - IFC.REVIGRÉS-Dados gerais-Floor Covering - Nome: REVIGRÉS-LOCUS-BASE-44.35x88.9-SILK-GRIS; TipoProduto: Prensado a seco: grupo BIa UGL | Grés porcelânico técnico; NumeroDeRegistoDAP: EPD-REV-20240006-CCC1-EN; ReferenciaDAP: -; UrlDOP: -
Classification: C3010 (Uniformat)
Pset_CoveringCommon - TotalThickness: 10.5 mm
IFC.REVIGRÉS-Dados do fabricante-Floor Covering - Type: Floor: REVIGRÉS-LOCUS-BASE-44.35x88.9-SILK-GRIS
IFC.REVIGRÉS-Dados de desempenho-Floor Covering - Type: Floor: REVIGRÉS-LOCUS-BASE-44.35x88.9-SILK-GRIS
IFC.REVIGRÉS-Dados de especificação-Floor Covering - Type: Floor: REVIGRÉS-LOCUS-BASE-44.35x88.9-SILK-GRIS
IFC.REVIGRÉS-Dados geométricos-Floor Covering - Type: Floor: REVIGRÉS-LOCUS-BASE-44.35x88.9-SILK-GRIS
IFC.REVIGRÉS-Dados de sustentabilidade-Floor Covering - Type: Floor: REVIGRÉS-LOCUS-BASE-44.35x88.9-SILK-GRIS

# IfcCovering: Floor:REVIGRÉS-LOCUS-BASE-44.35x88.9-SILK-SMOG, Floor:REVIGRÉS-LOCUS-BASE-44.35x88.9-SILK-SMOG:37887
In: Level 1
Type - PredefinedType: CLADDING; Material: REVIGRÉS-LOCUS-BASE-45X90-SILK-SMOG 10.5 mm
Type - Pset_CoveringCommon - Reference: 312GH8V701; Material: Grés porcelânico
Type - Pset_ElementShading - Roughness: 304.8 mm
Type - Pset_ManufacturerTypeInformation - Manufacturer: REVIGRÉS
Type - Pset_ProductRequirements - Category: Floors
Type - Pset_QuantityTakeOff - Reference: 312GH8V701
Type - IFC.REVIGRÉS-Dados do fabricante-Floor Covering - FabricanteURL: https://www.revigres.pt/; ReferenciaModelo: Locus; NumeroGlobalDeItemComercial: 312GH8V701; Acabamento: SILK; Material: Grés porcelânico; IdentificadorDoOperadorEconomico: 501840856; UrlFabricanteArtigo: https://www.revigres.pt/colecoes/locus; PaisOrigem: Portugal
Type - IFC.REVIGRÉS-Dados de desempenho-Floor Covering - Rectilinearidade: ± 0.2% máx.± 0.8 mm; Ortogonalidade: ± 0.2% máx.± 1.5 mm; PlanaridadeDaSuperficie: ± 0.3% máx. ± 1.8 mm; QualidadeDaSuperficie: Cumpre; AbsorcaoDeAgua: < 0.05%; ModuloDeRuptura: > 45 N/mm²; ResistenciaAFlexao: > 2000 N; ResistenciaAAbrasaoProfunda: < 120 mm³; DilatacaoTermicaLinear: ≤ 8,0x10-6 °C-1; ResistenciaAoChoqueTermico: Resiste; DurabilidadeInterior: Cumpre; DurabilidadeResistenciaAoGeloDegelo: Resiste; ResistenciaAoEscorregamentoDIN51130: R9; ResistenciaAoEscorregamentoDIN51097: A; ResistenciaAoEscorregamentoENV51097: A; ResistenciaAoEscorregamentoENV12633: Class 1; ResistenciaAoEscorregamentoBS7976: -; ResistenciaAoEscorregamentoANSIA1371: ≥0,42; ResistenciaAoDeslizamentoENV12633: Class 1; ResistenciaAoDeslizamentoBS7976: -; ResistenciaAsManchas: Class 5; LibertacaoDeCadmio: 0; LibertacaoDeChumbo: 0
Type - IFC.REVIGRÉS-Dados de especificação-Floor Covering - VariacaoTonalidade: 3; NivelDeTrafego: 5; EPavimento: Sim; ERevestimento: Sim; EExterno: Sim
Type - IFC.REVIGRÉS-Dados geométricos-Floor Covering - AlturaNominal: 10.5 mm; ComprimentoNominal: 44.35 mm; LarguraNominal: 88.9 mm
Type - IFC.REVIGRÉS-Dados de sustentabilidade-Floor Covering - EnergiaTermicaExportada: 0; ItemENovo: Sim; ItemEParcialmenteReciclado: 0.29; ItemEReciclado: Sim; VidaÚtilEsperada: 50; SubstanciasPerigosas: Não; PotencialDeEsgotamentoAbioticoDosRecursosFosseis: 203; PotencialDeEsgotamentoAbioticoDosRecursosNaoFosseisMineraisEMetais: 0.000701; PotencialDeAquecimentoGlobalBiogenico: -0.48; CombustiveisFosseisComPotencialDeAquecimentoGlobal: 13.9; PotencialDeAquecimentoGlobalUsoDoSoloEMudancaDeUsoDoSolo: 0.0246; PotencialDeEutrofizacaoFraccaoDeNutrientesQueAtingemOCompartimentoFinalDeAguaDoce: 0.000189; PotencialDeEutrofizacaoFraccaoDeNutrientesQueAtingemOCompartimentoFinalMarinho: 0.0122; EnergiaRecuperada: 0.00739; ConsumoDeAguaDoce: 0.113; UtilizacaoLiquidaDeAguaDoce: 0.113; ResiduosPerigososEliminados: 0.00221; ResiduosNaoPerigososEliminados: 1.83; MassaTotalDeResiduosRadioactivosEliminados: 0.000394; EnergiaElectricaExportada: 1.55; MateriaisParaRecuperacaoDeEnergia: 0.00739; MateriaisParaReciclagem: 0.0253; UnidadeEPD: 1 m²
Type - IFC.REVIGRÉS-Dados gerais-Floor Covering - Nome: REVIGRÉS-LOCUS-BASE-44.35x88.9-SILK-SMOG; TipoProduto: Prensado a seco: grupo BIa UGL | Grés porcelânico técnico; NumeroDeRegistoDAP: EPD-REV-20240006-CCC1-EN; ReferenciaDAP: -; UrlDOP: -
Classification: C3010 (Uniformat)
Pset_CoveringCommon - TotalThickness: 10.5 mm
IFC.REVIGRÉS-Dados do fabricante-Floor Covering - Type: Floor: REVIGRÉS-LOCUS-BASE-44.35x88.9-SILK-SMOG
IFC.REVIGRÉS-Dados de desempenho-Floor Covering - Type: Floor: REVIGRÉS-LOCUS-BASE-44.35x88.9-SILK-SMOG
IFC.REVIGRÉS-Dados de especificação-Floor Covering - Type: Floor: REVIGRÉS-LOCUS-BASE-44.35x88.9-SILK-SMOG
IFC.REVIGRÉS-Dados geométricos-Floor Covering - Type: Floor: REVIGRÉS-LOCUS-BASE-44.35x88.9-SILK-SMOG
IFC.REVIGRÉS-Dados de sustentabilidade-Floor Covering - Type: Floor: REVIGRÉS-LOCUS-BASE-44.35x88.9-SILK-SMOG

# IfcCovering: Floor:REVIGRÉS-LOCUS-BASE-44.35x88.9-SOFT GRIP-ALLOY, Floor:REVIGRÉS-LOCUS-BASE-44.35x88.9-SOFT GRIP-ALLOY:36369
In: Level 1
Type - PredefinedType: CLADDING; Material: REVIGRÉS-LOCUS-BASE-45X90-SOFT GRIP-ALLOY 10.5 mm
Type - Pset_CoveringCommon - Reference: 312FH8V671; Material: Grés porcelânico
Type - Pset_ElementShading - Roughness: 304.8 mm
Type - Pset_ManufacturerTypeInformation - Manufacturer: REVIGRÉS
Type - Pset_ProductRequirements - Category: Floors
Type - Pset_QuantityTakeOff - Reference: 312FH8V671
Type - IFC.REVIGRÉS-Dados do fabricante-Floor Covering - FabricanteURL: https://www.revigres.pt/; ReferenciaModelo: Locus; NumeroGlobalDeItemComercial: 312FH8V671; Acabamento: SOFT; Material: Grés porcelânico; IdentificadorDoOperadorEconomico: 501840856; UrlFabricanteArtigo: https://www.revigres.pt/colecoes/locus; PaisOrigem: Portugal
Type - IFC.REVIGRÉS-Dados de desempenho-Floor Covering - Rectilinearidade: ± 0.2% máx ± 1.0 mm; Ortogonalidade: ± 0.2% máx.± 1.5 mm; PlanaridadeDaSuperficie: ± 0.3% máx. ± 1.8 mm; QualidadeDaSuperficie: Cumpre; AbsorcaoDeAgua: < 0.05%; ModuloDeRuptura: > 45 N/mm²; ResistenciaAFlexao: > 3500 N; ResistenciaAAbrasaoProfunda: < 120 mm³; DilatacaoTermicaLinear: ≤ 8,0x10-6 °C-1; ResistenciaAoChoqueTermico: Resiste; DurabilidadeInterior: Cumpre; DurabilidadeResistenciaAoGeloDegelo: Resiste; ResistenciaAoEscorregamentoDIN51130: R11; ResistenciaAoEscorregamentoDIN51097: A; ResistenciaAoEscorregamentoENV51097: A; ResistenciaAoEscorregamentoENV12633: Class 2; ResistenciaAoEscorregamentoBS7976: > 36; ResistenciaAoEscorregamentoANSIA1371: ≥0,42; ResistenciaAoDeslizamentoENV12633: Class 2; ResistenciaAoDeslizamentoBS7976: > 36; ResistenciaAsManchas: Class 5; LibertacaoDeCadmio: 0; LibertacaoDeChumbo: 0
Type - IFC.REVIGRÉS-Dados de especificação-Floor Covering - VariacaoTonalidade: 3; NivelDeTrafego: 5; EPavimento: Sim; ERevestimento: Sim; EExterno: Sim
Type - IFC.REVIGRÉS-Dados geométricos-Floor Covering - AlturaNominal: 10.5 mm; ComprimentoNominal: 44.35 mm; LarguraNominal: 88.9 mm
Type - IFC.REVIGRÉS-Dados de sustentabilidade-Floor Covering - ItemEParcialmenteReciclado: 0; EnergiaTermicaExportada: 0; ItemENovo: Sim; ItemEReciclado: Não; VidaÚtilEsperada: 50; SubstanciasPerigosas: Não; PotencialDeEsgotamentoAbioticoDosRecursosFosseis: 203; PotencialDeEsgotamentoAbioticoDosRecursosNaoFosseisMineraisEMetais: 0.000701; PotencialDeAquecimentoGlobalBiogenico: -0.48; CombustiveisFosseisComPotencialDeAquecimentoGlobal: 13.9; PotencialDeAquecimentoGlobalUsoDoSoloEMudancaDeUsoDoSolo: 0.0246; PotencialDeEutrofizacaoFraccaoDeNutrientesQueAtingemOCompartimentoFinalDeAguaDoce: 0.000189; PotencialDeEutrofizacaoFraccaoDeNutrientesQueAtingemOCompartimentoFinalMarinho: 0.0122; EnergiaRecuperada: 0.00739; ConsumoDeAguaDoce: 0.113; UtilizacaoLiquidaDeAguaDoce: 0.113; ResiduosPerigososEliminados: 0.00221; ResiduosNaoPerigososEliminados: 1.83; MassaTotalDeResiduosRadioactivosEliminados: 0.000394; EnergiaElectricaExportada: 1.55; MateriaisParaRecuperacaoDeEnergia: 0.00739; MateriaisParaReciclagem: 0.0253; UnidadeEPD: 1 m²
Type - IFC.REVIGRÉS-Dados gerais-Floor Covering - Nome: REVIGRÉS-LOCUS-BASE-44.35x88.9-SOFT GRIP-ALLOY; TipoProduto: Prensado a seco: grupo BIa UGL | Grés porcelânico técnico; NumeroDeRegistoDAP: EPD-REV-20240006-CCC1-EN; ReferenciaDAP: -; UrlDOP: -
Classification: C3010 (Uniformat)
Pset_CoveringCommon - TotalThickness: 10.5 mm
IFC.REVIGRÉS-Dados do fabricante-Floor Covering - Type: Floor: REVIGRÉS-LOCUS-BASE-44.35x88.9-SOFT GRIP-ALLOY
IFC.REVIGRÉS-Dados de desempenho-Floor Covering - Type: Floor: REVIGRÉS-LOCUS-BASE-44.35x88.9-SOFT GRIP-ALLOY
IFC.REVIGRÉS-Dados de especificação-Floor Covering - Type: Floor: REVIGRÉS-LOCUS-BASE-44.35x88.9-SOFT GRIP-ALLOY
IFC.REVIGRÉS-Dados geométricos-Floor Covering - Type: Floor: REVIGRÉS-LOCUS-BASE-44.35x88.9-SOFT GRIP-ALLOY
IFC.REVIGRÉS-Dados de sustentabilidade-Floor Covering - Type: Floor: REVIGRÉS-LOCUS-BASE-44.35x88.9-SOFT GRIP-ALLOY

# IfcCovering: Floor:REVIGRÉS-LOCUS-BASE-44.35x88.9-SOFT GRIP-BONE, Floor:REVIGRÉS-LOCUS-BASE-44.35x88.9-SOFT GRIP-BONE:36697
In: Level 1
Type - PredefinedType: CLADDING; Material: REVIGRÉS-LOCUS-BASE-45X90-SOFT GRIP-BONE 10.5 mm
Type - Pset_CoveringCommon - Reference: 312FH8V681; Material: Grés porcelânico
Type - Pset_ElementShading - Roughness: 304.8 mm
Type - Pset_ManufacturerTypeInformation - Manufacturer: REVIGRÉS
Type - Pset_ProductRequirements - Category: Floors
Type - Pset_QuantityTakeOff - Reference: 312FH8V681
Type - IFC.REVIGRÉS-Dados do fabricante-Floor Covering - FabricanteURL: https://www.revigres.pt/; ReferenciaModelo: Locus; NumeroGlobalDeItemComercial: 312FH8V681; Acabamento: SOFT; Material: Grés porcelânico; IdentificadorDoOperadorEconomico: 501840856; UrlFabricanteArtigo: https://www.revigres.pt/colecoes/locus; PaisOrigem: Portugal
Type - IFC.REVIGRÉS-Dados de desempenho-Floor Covering - Rectilinearidade: ± 0.2% máx ± 1.0 mm; Ortogonalidade: ± 0.2% máx.± 1.5 mm; PlanaridadeDaSuperficie: ± 0.3% máx. ± 1.8 mm; QualidadeDaSuperficie: Cumpre; AbsorcaoDeAgua: < 0.05%; ModuloDeRuptura: > 45 N/mm²; ResistenciaAFlexao: > 3500 N; ResistenciaAAbrasaoProfunda: < 120 mm³; DilatacaoTermicaLinear: ≤ 8,0x10-6 °C-1; ResistenciaAoChoqueTermico: Resiste; DurabilidadeInterior: Cumpre; DurabilidadeResistenciaAoGeloDegelo: Resiste; ResistenciaAoEscorregamentoDIN51130: R11; ResistenciaAoEscorregamentoDIN51097: A; ResistenciaAoEscorregamentoENV51097: A; ResistenciaAoEscorregamentoENV12633: Class 2; ResistenciaAoEscorregamentoBS7976: > 36; ResistenciaAoEscorregamentoANSIA1371: ≥0,42; ResistenciaAoDeslizamentoENV12633: Class 2; ResistenciaAoDeslizamentoBS7976: > 36; ResistenciaAsManchas: Class 5; LibertacaoDeCadmio: 0; LibertacaoDeChumbo: 0
Type - IFC.REVIGRÉS-Dados de especificação-Floor Covering - VariacaoTonalidade: 3; NivelDeTrafego: 5; EPavimento: Sim; ERevestimento: Sim; EExterno: Sim
Type - IFC.REVIGRÉS-Dados geométricos-Floor Covering - AlturaNominal: 10.5 mm; ComprimentoNominal: 44.35 mm; LarguraNominal: 88.9 mm
Type - IFC.REVIGRÉS-Dados de sustentabilidade-Floor Covering - ItemEParcialmenteReciclado: 0; EnergiaTermicaExportada: 0; ItemENovo: Sim; ItemEReciclado: Não; VidaÚtilEsperada: 50; SubstanciasPerigosas: Não; PotencialDeEsgotamentoAbioticoDosRecursosFosseis: 203; PotencialDeEsgotamentoAbioticoDosRecursosNaoFosseisMineraisEMetais: 0.000701; PotencialDeAquecimentoGlobalBiogenico: -0.48; CombustiveisFosseisComPotencialDeAquecimentoGlobal: 13.9; PotencialDeAquecimentoGlobalUsoDoSoloEMudancaDeUsoDoSolo: 0.0246; PotencialDeEutrofizacaoFraccaoDeNutrientesQueAtingemOCompartimentoFinalDeAguaDoce: 0.000189; PotencialDeEutrofizacaoFraccaoDeNutrientesQueAtingemOCompartimentoFinalMarinho: 0.0122; EnergiaRecuperada: 0.00739; ConsumoDeAguaDoce: 0.113; UtilizacaoLiquidaDeAguaDoce: 0.113; ResiduosPerigososEliminados: 0.00221; ResiduosNaoPerigososEliminados: 1.83; MassaTotalDeResiduosRadioactivosEliminados: 0.000394; EnergiaElectricaExportada: 1.55; MateriaisParaRecuperacaoDeEnergia: 0.00739; MateriaisParaReciclagem: 0.0253; UnidadeEPD: 1 m²
Type - IFC.REVIGRÉS-Dados gerais-Floor Covering - Nome: REVIGRÉS-LOCUS-BASE-44.35x88.9-SOFT GRIP-BONE; TipoProduto: Prensado a seco: grupo BIa UGL | Grés porcelânico técnico; NumeroDeRegistoDAP: EPD-REV-20240006-CCC1-EN; ReferenciaDAP: -; UrlDOP: -
Classification: C3010 (Uniformat)
Pset_CoveringCommon - TotalThickness: 10.5 mm
IFC.REVIGRÉS-Dados do fabricante-Floor Covering - Type: Floor: REVIGRÉS-LOCUS-BASE-44.35x88.9-SOFT GRIP-BONE
IFC.REVIGRÉS-Dados de desempenho-Floor Covering - Type: Floor: REVIGRÉS-LOCUS-BASE-44.35x88.9-SOFT GRIP-BONE
IFC.REVIGRÉS-Dados de especificação-Floor Covering - Type: Floor: REVIGRÉS-LOCUS-BASE-44.35x88.9-SOFT GRIP-BONE
IFC.REVIGRÉS-Dados geométricos-Floor Covering - Type: Floor: REVIGRÉS-LOCUS-BASE-44.35x88.9-SOFT GRIP-BONE
IFC.REVIGRÉS-Dados de sustentabilidade-Floor Covering - Type: Floor: REVIGRÉS-LOCUS-BASE-44.35x88.9-SOFT GRIP-BONE

# IfcCovering: Floor:REVIGRÉS-LOCUS-BASE-44.35x88.9-SOFT GRIP-GRIS, Floor:REVIGRÉS-LOCUS-BASE-44.35x88.9-SOFT GRIP-GRIS:37364
In: Level 1
Type - PredefinedType: CLADDING; Material: REVIGRÉS-LOCUS-BASE-45X90-SOFT GRIP-GRIS 10.5 mm
Type - Pset_CoveringCommon - Reference: 312FH8V691; Material: Grés porcelânico
Type - Pset_ElementShading - Roughness: 304.8 mm
Type - Pset_ManufacturerTypeInformation - Manufacturer: REVIGRÉS
Type - Pset_ProductRequirements - Category: Floors
Type - Pset_QuantityTakeOff - Reference: 312FH8V691
Type - IFC.REVIGRÉS-Dados do fabricante-Floor Covering - FabricanteURL: https://www.revigres.pt/; ReferenciaModelo: Locus; NumeroGlobalDeItemComercial: 312FH8V691; Acabamento: SOFT; Material: Grés porcelânico; IdentificadorDoOperadorEconomico: 501840856; UrlFabricanteArtigo: https://www.revigres.pt/colecoes/locus; PaisOrigem: Portugal
Type - IFC.REVIGRÉS-Dados de desempenho-Floor Covering - Rectilinearidade: ± 0.2% máx ± 1.0 mm; Ortogonalidade: ± 0.2% máx.± 1.5 mm; PlanaridadeDaSuperficie: ± 0.3% máx. ± 1.8 mm; QualidadeDaSuperficie: Cumpre; AbsorcaoDeAgua: < 0.05%; ModuloDeRuptura: > 45 N/mm²; ResistenciaAFlexao: > 3500 N; ResistenciaAAbrasaoProfunda: < 120 mm³; DilatacaoTermicaLinear: ≤ 8,0x10-6 °C-1; ResistenciaAoChoqueTermico: Resiste; DurabilidadeInterior: Cumpre; DurabilidadeResistenciaAoGeloDegelo: Resiste; ResistenciaAoEscorregamentoDIN51130: R11; ResistenciaAoEscorregamentoDIN51097: A; ResistenciaAoEscorregamentoENV51097: A; ResistenciaAoEscorregamentoENV12633: Class 2; ResistenciaAoEscorregamentoBS7976: > 36; ResistenciaAoEscorregamentoANSIA1371: ≥0,42; ResistenciaAoDeslizamentoENV12633: Class 2; ResistenciaAoDeslizamentoBS7976: > 36; ResistenciaAsManchas: Class 5; LibertacaoDeCadmio: 0; LibertacaoDeChumbo: 0
Type - IFC.REVIGRÉS-Dados de especificação-Floor Covering - VariacaoTonalidade: 3; NivelDeTrafego: 5; EPavimento: Sim; ERevestimento: Sim; EExterno: Sim
Type - IFC.REVIGRÉS-Dados geométricos-Floor Covering - AlturaNominal: 10.5 mm; ComprimentoNominal: 44.35 mm; LarguraNominal: 88.9 mm
Type - IFC.REVIGRÉS-Dados de sustentabilidade-Floor Covering - EnergiaTermicaExportada: 0; ItemENovo: Sim; ItemEParcialmenteReciclado: 0.23; ItemEReciclado: Sim; VidaÚtilEsperada: 50; SubstanciasPerigosas: Não; PotencialDeEsgotamentoAbioticoDosRecursosFosseis: 203; PotencialDeEsgotamentoAbioticoDosRecursosNaoFosseisMineraisEMetais: 0.000701; PotencialDeAquecimentoGlobalBiogenico: -0.48; CombustiveisFosseisComPotencialDeAquecimentoGlobal: 13.9; PotencialDeAquecimentoGlobalUsoDoSoloEMudancaDeUsoDoSolo: 0.0246; PotencialDeEutrofizacaoFraccaoDeNutrientesQueAtingemOCompartimentoFinalDeAguaDoce: 0.000189; PotencialDeEutrofizacaoFraccaoDeNutrientesQueAtingemOCompartimentoFinalMarinho: 0.0122; EnergiaRecuperada: 0.00739; ConsumoDeAguaDoce: 0.113; UtilizacaoLiquidaDeAguaDoce: 0.113; ResiduosPerigososEliminados: 0.00221; ResiduosNaoPerigososEliminados: 1.83; MassaTotalDeResiduosRadioactivosEliminados: 0.000394; EnergiaElectricaExportada: 1.55; MateriaisParaRecuperacaoDeEnergia: 0.00739; MateriaisParaReciclagem: 0.0253; UnidadeEPD: 1 m²
Type - IFC.REVIGRÉS-Dados gerais-Floor Covering - Nome: REVIGRÉS-LOCUS-BASE-44.35x88.9-SOFT GRIP-GRIS; TipoProduto: Prensado a seco: grupo BIa UGL | Grés porcelânico técnico; NumeroDeRegistoDAP: EPD-REV-20240006-CCC1-EN; ReferenciaDAP: -; UrlDOP: -
Classification: C3010 (Uniformat)
Pset_CoveringCommon - TotalThickness: 10.5 mm
IFC.REVIGRÉS-Dados do fabricante-Floor Covering - Type: Floor: REVIGRÉS-LOCUS-BASE-44.35x88.9-SOFT GRIP-GRIS
IFC.REVIGRÉS-Dados de desempenho-Floor Covering - Type: Floor: REVIGRÉS-LOCUS-BASE-44.35x88.9-SOFT GRIP-GRIS
IFC.REVIGRÉS-Dados de especificação-Floor Covering - Type: Floor: REVIGRÉS-LOCUS-BASE-44.35x88.9-SOFT GRIP-GRIS
IFC.REVIGRÉS-Dados geométricos-Floor Covering - Type: Floor: REVIGRÉS-LOCUS-BASE-44.35x88.9-SOFT GRIP-GRIS
IFC.REVIGRÉS-Dados de sustentabilidade-Floor Covering - Type: Floor: REVIGRÉS-LOCUS-BASE-44.35x88.9-SOFT GRIP-GRIS

# IfcCovering: Floor:REVIGRÉS-LOCUS-BASE-44.35x88.9-SOFT GRIP-SMOG, Floor:REVIGRÉS-LOCUS-BASE-44.35x88.9-SOFT GRIP-SMOG:37879
In: Level 1
Type - PredefinedType: CLADDING; Material: REVIGRÉS-LOCUS-BASE-45X90-SOFT GRIP-SMOG 10.5 mm
Type - Pset_CoveringCommon - Reference: 312FH8V701; Material: Grés porcelânico
Type - Pset_ElementShading - Roughness: 304.8 mm
Type - Pset_ManufacturerTypeInformation - Manufacturer: REVIGRÉS
Type - Pset_ProductRequirements - Category: Floors
Type - Pset_QuantityTakeOff - Reference: 312FH8V701
Type - IFC.REVIGRÉS-Dados do fabricante-Floor Covering - FabricanteURL: https://www.revigres.pt/; ReferenciaModelo: Locus; NumeroGlobalDeItemComercial: 312FH8V701; Acabamento: SOFT; Material: Grés porcelânico; IdentificadorDoOperadorEconomico: 501840856; UrlFabricanteArtigo: https://www.revigres.pt/colecoes/locus; PaisOrigem: Portugal
Type - IFC.REVIGRÉS-Dados de desempenho-Floor Covering - Rectilinearidade: ± 0.2% máx ± 1.0 mm; Ortogonalidade: ± 0.2% máx.± 1.5 mm; PlanaridadeDaSuperficie: ± 0.3% máx. ± 1.8 mm; QualidadeDaSuperficie: Cumpre; AbsorcaoDeAgua: < 0.05%; ModuloDeRuptura: > 45 N/mm²; ResistenciaAFlexao: > 3500 N; ResistenciaAAbrasaoProfunda: < 120 mm³; DilatacaoTermicaLinear: ≤ 8,0x10-6 °C-1; ResistenciaAoChoqueTermico: Resiste; DurabilidadeInterior: Cumpre; DurabilidadeResistenciaAoGeloDegelo: Resiste; ResistenciaAoEscorregamentoDIN51130: R11; ResistenciaAoEscorregamentoDIN51097: A; ResistenciaAoEscorregamentoENV51097: A; ResistenciaAoEscorregamentoENV12633: Class 2; ResistenciaAoEscorregamentoBS7976: > 36; ResistenciaAoEscorregamentoANSIA1371: ≥0,42; ResistenciaAoDeslizamentoENV12633: Class 2; ResistenciaAoDeslizamentoBS7976: > 36; ResistenciaAsManchas: Class 5; LibertacaoDeCadmio: 0; LibertacaoDeChumbo: 0
Type - IFC.REVIGRÉS-Dados de especificação-Floor Covering - VariacaoTonalidade: 3; NivelDeTrafego: 5; EPavimento: Sim; ERevestimento: Sim; EExterno: Sim
Type - IFC.REVIGRÉS-Dados geométricos-Floor Covering - AlturaNominal: 10.5 mm; ComprimentoNominal: 44.35 mm; LarguraNominal: 88.9 mm
Type - IFC.REVIGRÉS-Dados de sustentabilidade-Floor Covering - EnergiaTermicaExportada: 0; ItemENovo: Sim; ItemEParcialmenteReciclado: 0.29; ItemEReciclado: Sim; VidaÚtilEsperada: 50; SubstanciasPerigosas: Não; PotencialDeEsgotamentoAbioticoDosRecursosFosseis: 203; PotencialDeEsgotamentoAbioticoDosRecursosNaoFosseisMineraisEMetais: 0.000701; PotencialDeAquecimentoGlobalBiogenico: -0.48; CombustiveisFosseisComPotencialDeAquecimentoGlobal: 13.9; PotencialDeAquecimentoGlobalUsoDoSoloEMudancaDeUsoDoSolo: 0.0246; PotencialDeEutrofizacaoFraccaoDeNutrientesQueAtingemOCompartimentoFinalDeAguaDoce: 0.000189; PotencialDeEutrofizacaoFraccaoDeNutrientesQueAtingemOCompartimentoFinalMarinho: 0.0122; EnergiaRecuperada: 0.00739; ConsumoDeAguaDoce: 0.113; UtilizacaoLiquidaDeAguaDoce: 0.113; ResiduosPerigososEliminados: 0.00221; ResiduosNaoPerigososEliminados: 1.83; MassaTotalDeResiduosRadioactivosEliminados: 0.000394; EnergiaElectricaExportada: 1.55; MateriaisParaRecuperacaoDeEnergia: 0.00739; MateriaisParaReciclagem: 0.0253; UnidadeEPD: 1 m²
Type - IFC.REVIGRÉS-Dados gerais-Floor Covering - Nome: REVIGRÉS-LOCUS-BASE-44.35x88.9-SOFT GRIP-SMOG; TipoProduto: Prensado a seco: grupo BIa UGL | Grés porcelânico técnico; NumeroDeRegistoDAP: EPD-REV-20240006-CCC1-EN; ReferenciaDAP: -; UrlDOP: -
Classification: C3010 (Uniformat)
Pset_CoveringCommon - TotalThickness: 10.5 mm
IFC.REVIGRÉS-Dados do fabricante-Floor Covering - Type: Floor: REVIGRÉS-LOCUS-BASE-44.35x88.9-SOFT GRIP-SMOG
IFC.REVIGRÉS-Dados de desempenho-Floor Covering - Type: Floor: REVIGRÉS-LOCUS-BASE-44.35x88.9-SOFT GRIP-SMOG
IFC.REVIGRÉS-Dados de especificação-Floor Covering - Type: Floor: REVIGRÉS-LOCUS-BASE-44.35x88.9-SOFT GRIP-SMOG
IFC.REVIGRÉS-Dados geométricos-Floor Covering - Type: Floor: REVIGRÉS-LOCUS-BASE-44.35x88.9-SOFT GRIP-SMOG
IFC.REVIGRÉS-Dados de sustentabilidade-Floor Covering - Type: Floor: REVIGRÉS-LOCUS-BASE-44.35x88.9-SOFT GRIP-SMOG

# IfcCovering: Floor:REVIGRÉS-LOCUS-BASE-59.2x59.2-SILK-ALLOY, Floor:REVIGRÉS-LOCUS-BASE-59.2x59.2-SILK-ALLOY:36226
In: Level 1
Type - PredefinedType: CLADDING; Material: REVIGRÉS-LOCUS-BASE-60x60-SILK-ALLOY 8.5 mm
Type - Pset_CoveringCommon - Reference: 312G13V671; Material: Grés porcelânico
Type - Pset_ElementShading - Roughness: 304.8 mm
Type - Pset_ManufacturerTypeInformation - Manufacturer: REVIGRÉS
Type - Pset_ProductRequirements - Category: Floors
Type - Pset_QuantityTakeOff - Reference: 312G13V671
Type - IFC.REVIGRÉS-Dados do fabricante-Floor Covering - FabricanteURL: https://www.revigres.pt/; ReferenciaModelo: Locus; NumeroGlobalDeItemComercial: 312G13V671; Acabamento: SILK; Material: Grés porcelânico; IdentificadorDoOperadorEconomico: 501840856; UrlFabricanteArtigo: https://www.revigres.pt/colecoes/locus; PaisOrigem: Portugal
Type - IFC.REVIGRÉS-Dados de desempenho-Floor Covering - Rectilinearidade: ± 0.2% máx.± 0.8 mm; Ortogonalidade: ± 0.2% máx.± 1.5 mm; PlanaridadeDaSuperficie: ± 0.3% máx. ± 1.8 mm; QualidadeDaSuperficie: Cumpre; AbsorcaoDeAgua: < 0.05%; ModuloDeRuptura: > 45 N/mm²; ResistenciaAFlexao: > 2000 N; ResistenciaAAbrasaoProfunda: < 120 mm³; DilatacaoTermicaLinear: ≤ 8,0x10-6 °C-1; ResistenciaAoChoqueTermico: Resiste; DurabilidadeInterior: Cumpre; DurabilidadeResistenciaAoGeloDegelo: Resiste; ResistenciaAoEscorregamentoDIN51130: R9; ResistenciaAoEscorregamentoDIN51097: A; ResistenciaAoEscorregamentoENV51097: A; ResistenciaAoEscorregamentoENV12633: Class 1; ResistenciaAoEscorregamentoBS7976: -; ResistenciaAoEscorregamentoANSIA1371: ≥0,42; ResistenciaAoDeslizamentoENV12633: Class 1; ResistenciaAoDeslizamentoBS7976: -; ResistenciaAsManchas: Class 5; LibertacaoDeCadmio: 0; LibertacaoDeChumbo: 0
Type - IFC.REVIGRÉS-Dados de especificação-Floor Covering - VariacaoTonalidade: 3; NivelDeTrafego: 5; EPavimento: Sim; ERevestimento: Sim; EExterno: Sim
Type - IFC.REVIGRÉS-Dados geométricos-Floor Covering - AlturaNominal: 8.5 mm; ComprimentoNominal: 59.2 mm; LarguraNominal: 59.2 mm
Type - IFC.REVIGRÉS-Dados de sustentabilidade-Floor Covering - ItemEParcialmenteReciclado: 0; EnergiaTermicaExportada: 0; ItemENovo: Sim; ItemEReciclado: Não; VidaÚtilEsperada: 50; SubstanciasPerigosas: Não; PotencialDeEsgotamentoAbioticoDosRecursosFosseis: 203; PotencialDeEsgotamentoAbioticoDosRecursosNaoFosseisMineraisEMetais: 0.000701; PotencialDeAquecimentoGlobalBiogenico: -0.48; CombustiveisFosseisComPotencialDeAquecimentoGlobal: 13.9; PotencialDeAquecimentoGlobalUsoDoSoloEMudancaDeUsoDoSolo: 0.0246; PotencialDeEutrofizacaoFraccaoDeNutrientesQueAtingemOCompartimentoFinalDeAguaDoce: 0.000189; PotencialDeEutrofizacaoFraccaoDeNutrientesQueAtingemOCompartimentoFinalMarinho: 0.0122; EnergiaRecuperada: 0.00739; ConsumoDeAguaDoce: 0.113; UtilizacaoLiquidaDeAguaDoce: 0.113; ResiduosPerigososEliminados: 0.00221; ResiduosNaoPerigososEliminados: 1.83; MassaTotalDeResiduosRadioactivosEliminados: 0.000394; EnergiaElectricaExportada: 1.55; MateriaisParaRecuperacaoDeEnergia: 0.00739; MateriaisParaReciclagem: 0.0253; UnidadeEPD: 1 m²
Type - IFC.REVIGRÉS-Dados gerais-Floor Covering - Nome: REVIGRÉS-LOCUS-BASE-59.2x59.2-SILK-ALLOY; TipoProduto: Prensado a seco: grupo BIa UGL | Grés porcelânico técnico; NumeroDeRegistoDAP: EPD-REV-20240006-CCC1-EN; ReferenciaDAP: -; UrlDOP: -
Classification: C3010 (Uniformat)
Pset_CoveringCommon - TotalThickness: 8.5 mm
IFC.REVIGRÉS-Dados do fabricante-Floor Covering - Type: Floor: REVIGRÉS-LOCUS-BASE-59.2x59.2-SILK-ALLOY
IFC.REVIGRÉS-Dados de desempenho-Floor Covering - Type: Floor: REVIGRÉS-LOCUS-BASE-59.2x59.2-SILK-ALLOY
IFC.REVIGRÉS-Dados de especificação-Floor Covering - Type: Floor: REVIGRÉS-LOCUS-BASE-59.2x59.2-SILK-ALLOY
IFC.REVIGRÉS-Dados geométricos-Floor Covering - Type: Floor: REVIGRÉS-LOCUS-BASE-59.2x59.2-SILK-ALLOY
IFC.REVIGRÉS-Dados de sustentabilidade-Floor Covering - Type: Floor: REVIGRÉS-LOCUS-BASE-59.2x59.2-SILK-ALLOY

# IfcCovering: Floor:REVIGRÉS-LOCUS-BASE-59.2x59.2-SILK-BONE, Floor:REVIGRÉS-LOCUS-BASE-59.2x59.2-SILK-BONE:36678
In: Level 1
Type - PredefinedType: CLADDING; Material: REVIGRÉS-LOCUS-BASE-60x60-SILK-BONE 8.5 mm
Type - Pset_CoveringCommon - Reference: 312G13V681; Material: Grés porcelânico
Type - Pset_ElementShading - Roughness: 304.8 mm
Type - Pset_ManufacturerTypeInformation - Manufacturer: REVIGRÉS
Type - Pset_ProductRequirements - Category: Floors
Type - Pset_QuantityTakeOff - Reference: 312G13V681
Type - IFC.REVIGRÉS-Dados do fabricante-Floor Covering - FabricanteURL: https://www.revigres.pt/; ReferenciaModelo: Locus; NumeroGlobalDeItemComercial: 312G13V681; Acabamento: SILK; Material: Grés porcelânico; IdentificadorDoOperadorEconomico: 501840856; UrlFabricanteArtigo: https://www.revigres.pt/colecoes/locus; PaisOrigem: Portugal
Type - IFC.REVIGRÉS-Dados de desempenho-Floor Covering - Rectilinearidade: ± 0.2% máx.± 0.8 mm; Ortogonalidade: ± 0.2% máx.± 1.5 mm; PlanaridadeDaSuperficie: ± 0.3% máx. ± 1.8 mm; QualidadeDaSuperficie: Cumpre; AbsorcaoDeAgua: < 0.05%; ModuloDeRuptura: > 45 N/mm²; ResistenciaAFlexao: > 2000 N; ResistenciaAAbrasaoProfunda: < 120 mm³; DilatacaoTermicaLinear: ≤ 8,0x10-6 °C-1; ResistenciaAoChoqueTermico: Resiste; DurabilidadeInterior: Cumpre; DurabilidadeResistenciaAoGeloDegelo: Resiste; ResistenciaAoEscorregamentoDIN51130: R9; ResistenciaAoEscorregamentoDIN51097: A; ResistenciaAoEscorregamentoENV51097: A; ResistenciaAoEscorregamentoENV12633: Class 1; ResistenciaAoEscorregamentoBS7976: -; ResistenciaAoEscorregamentoANSIA1371: ≥0,42; ResistenciaAoDeslizamentoENV12633: Class 1; ResistenciaAoDeslizamentoBS7976: -; ResistenciaAsManchas: Class 5; LibertacaoDeCadmio: 0; LibertacaoDeChumbo: 0
Type - IFC.REVIGRÉS-Dados de especificação-Floor Covering - VariacaoTonalidade: 3; NivelDeTrafego: 5; EPavimento: Sim; ERevestimento: Sim; EExterno: Sim
Type - IFC.REVIGRÉS-Dados geométricos-Floor Covering - AlturaNominal: 8.5 mm; ComprimentoNominal: 59.2 mm; LarguraNominal: 59.2 mm
Type - IFC.REVIGRÉS-Dados de sustentabilidade-Floor Covering - ItemEParcialmenteReciclado: 0; EnergiaTermicaExportada: 0; ItemENovo: Sim; ItemEReciclado: Não; VidaÚtilEsperada: 50; SubstanciasPerigosas: Não; PotencialDeEsgotamentoAbioticoDosRecursosFosseis: 203; PotencialDeEsgotamentoAbioticoDosRecursosNaoFosseisMineraisEMetais: 0.000701; PotencialDeAquecimentoGlobalBiogenico: -0.48; CombustiveisFosseisComPotencialDeAquecimentoGlobal: 13.9; PotencialDeAquecimentoGlobalUsoDoSoloEMudancaDeUsoDoSolo: 0.0246; PotencialDeEutrofizacaoFraccaoDeNutrientesQueAtingemOCompartimentoFinalDeAguaDoce: 0.000189; PotencialDeEutrofizacaoFraccaoDeNutrientesQueAtingemOCompartimentoFinalMarinho: 0.0122; EnergiaRecuperada: 0.00739; ConsumoDeAguaDoce: 0.113; UtilizacaoLiquidaDeAguaDoce: 0.113; ResiduosPerigososEliminados: 0.00221; ResiduosNaoPerigososEliminados: 1.83; MassaTotalDeResiduosRadioactivosEliminados: 0.000394; EnergiaElectricaExportada: 1.55; MateriaisParaRecuperacaoDeEnergia: 0.00739; MateriaisParaReciclagem: 0.0253; UnidadeEPD: 1 m²
Type - IFC.REVIGRÉS-Dados gerais-Floor Covering - Nome: REVIGRÉS-LOCUS-BASE-59.2x59.2-SILK-BONE; TipoProduto: Prensado a seco: grupo BIa UGL | Grés porcelânico técnico; NumeroDeRegistoDAP: EPD-REV-20240006-CCC1-EN; ReferenciaDAP: -; UrlDOP: -
Classification: C3010 (Uniformat)
Pset_CoveringCommon - TotalThickness: 8.5 mm
IFC.REVIGRÉS-Dados do fabricante-Floor Covering - Type: Floor: REVIGRÉS-LOCUS-BASE-59.2x59.2-SILK-BONE
IFC.REVIGRÉS-Dados de desempenho-Floor Covering - Type: Floor: REVIGRÉS-LOCUS-BASE-59.2x59.2-SILK-BONE
IFC.REVIGRÉS-Dados de especificação-Floor Covering - Type: Floor: REVIGRÉS-LOCUS-BASE-59.2x59.2-SILK-BONE
IFC.REVIGRÉS-Dados geométricos-Floor Covering - Type: Floor: REVIGRÉS-LOCUS-BASE-59.2x59.2-SILK-BONE
IFC.REVIGRÉS-Dados de sustentabilidade-Floor Covering - Type: Floor: REVIGRÉS-LOCUS-BASE-59.2x59.2-SILK-BONE

# IfcCovering: Floor:REVIGRÉS-LOCUS-BASE-59.2x59.2-SILK-GRIS, Floor:REVIGRÉS-LOCUS-BASE-59.2x59.2-SILK-GRIS:37348
In: Level 1
Type - PredefinedType: CLADDING; Material: REVIGRÉS-LOCUS-BASE-60x60-SILK-GRIS 8.5 mm
Type - Pset_CoveringCommon - Reference: 312G13V691; Material: Grés porcelânico
Type - Pset_ElementShading - Roughness: 304.8 mm
Type - Pset_ManufacturerTypeInformation - Manufacturer: REVIGRÉS
Type - Pset_ProductRequirements - Category: Floors
Type - Pset_QuantityTakeOff - Reference: 312G13V691
Type - IFC.REVIGRÉS-Dados do fabricante-Floor Covering - FabricanteURL: https://www.revigres.pt/; ReferenciaModelo: Locus; NumeroGlobalDeItemComercial: 312G13V691; Acabamento: SILK; Material: Grés porcelânico; IdentificadorDoOperadorEconomico: 501840856; UrlFabricanteArtigo: https://www.revigres.pt/colecoes/locus; PaisOrigem: Portugal
Type - IFC.REVIGRÉS-Dados de desempenho-Floor Covering - Rectilinearidade: ± 0.2% máx.± 0.8 mm; Ortogonalidade: ± 0.2% máx.± 1.5 mm; PlanaridadeDaSuperficie: ± 0.3% máx. ± 1.8 mm; QualidadeDaSuperficie: Cumpre; AbsorcaoDeAgua: < 0.05%; ModuloDeRuptura: > 45 N/mm²; ResistenciaAFlexao: > 2000 N; ResistenciaAAbrasaoProfunda: < 120 mm³; DilatacaoTermicaLinear: ≤ 8,0x10-6 °C-1; ResistenciaAoChoqueTermico: Resiste; DurabilidadeInterior: Cumpre; DurabilidadeResistenciaAoGeloDegelo: Resiste; ResistenciaAoEscorregamentoDIN51130: R9; ResistenciaAoEscorregamentoDIN51097: A; ResistenciaAoEscorregamentoENV51097: A; ResistenciaAoEscorregamentoENV12633: Class 1; ResistenciaAoEscorregamentoBS7976: -; ResistenciaAoEscorregamentoANSIA1371: ≥0,42; ResistenciaAoDeslizamentoENV12633: Class 1; ResistenciaAoDeslizamentoBS7976: -; ResistenciaAsManchas: Class 5; LibertacaoDeCadmio: 0; LibertacaoDeChumbo: 0
Type - IFC.REVIGRÉS-Dados de especificação-Floor Covering - VariacaoTonalidade: 3; NivelDeTrafego: 5; EPavimento: Sim; ERevestimento: Sim; EExterno: Sim
Type - IFC.REVIGRÉS-Dados geométricos-Floor Covering - AlturaNominal: 8.5 mm; ComprimentoNominal: 59.2 mm; LarguraNominal: 59.2 mm
Type - IFC.REVIGRÉS-Dados de sustentabilidade-Floor Covering - EnergiaTermicaExportada: 0; ItemENovo: Sim; ItemEParcialmenteReciclado: 0.23; ItemEReciclado: Sim; VidaÚtilEsperada: 50; SubstanciasPerigosas: Não; PotencialDeEsgotamentoAbioticoDosRecursosFosseis: 203; PotencialDeEsgotamentoAbioticoDosRecursosNaoFosseisMineraisEMetais: 0.000701; PotencialDeAquecimentoGlobalBiogenico: -0.48; CombustiveisFosseisComPotencialDeAquecimentoGlobal: 13.9; PotencialDeAquecimentoGlobalUsoDoSoloEMudancaDeUsoDoSolo: 0.0246; PotencialDeEutrofizacaoFraccaoDeNutrientesQueAtingemOCompartimentoFinalDeAguaDoce: 0.000189; PotencialDeEutrofizacaoFraccaoDeNutrientesQueAtingemOCompartimentoFinalMarinho: 0.0122; EnergiaRecuperada: 0.00739; ConsumoDeAguaDoce: 0.113; UtilizacaoLiquidaDeAguaDoce: 0.113; ResiduosPerigososEliminados: 0.00221; ResiduosNaoPerigososEliminados: 1.83; MassaTotalDeResiduosRadioactivosEliminados: 0.000394; EnergiaElectricaExportada: 1.55; MateriaisParaRecuperacaoDeEnergia: 0.00739; MateriaisParaReciclagem: 0.0253; UnidadeEPD: 1 m²
Type - IFC.REVIGRÉS-Dados gerais-Floor Covering - Nome: REVIGRÉS-LOCUS-BASE-59.2x59.2-SILK-GRIS; TipoProduto: Prensado a seco: grupo BIa UGL | Grés porcelânico técnico; NumeroDeRegistoDAP: EPD-REV-20240006-CCC1-EN; ReferenciaDAP: -; UrlDOP: -
Classification: C3010 (Uniformat)
Pset_CoveringCommon - TotalThickness: 8.5 mm
IFC.REVIGRÉS-Dados do fabricante-Floor Covering - Type: Floor: REVIGRÉS-LOCUS-BASE-59.2x59.2-SILK-GRIS
IFC.REVIGRÉS-Dados de desempenho-Floor Covering - Type: Floor: REVIGRÉS-LOCUS-BASE-59.2x59.2-SILK-GRIS
IFC.REVIGRÉS-Dados de especificação-Floor Covering - Type: Floor: REVIGRÉS-LOCUS-BASE-59.2x59.2-SILK-GRIS
IFC.REVIGRÉS-Dados geométricos-Floor Covering - Type: Floor: REVIGRÉS-LOCUS-BASE-59.2x59.2-SILK-GRIS
IFC.REVIGRÉS-Dados de sustentabilidade-Floor Covering - Type: Floor: REVIGRÉS-LOCUS-BASE-59.2x59.2-SILK-GRIS

# IfcCovering: Floor:REVIGRÉS-LOCUS-BASE-59.2x59.2-SILK-SMOG, Floor:REVIGRÉS-LOCUS-BASE-59.2x59.2-SILK-SMOG:37863
In: Level 1
Type - PredefinedType: CLADDING; Material: REVIGRÉS-LOCUS-BASE-60x60-SILK-SMOG 8.5 mm
Type - Pset_CoveringCommon - Reference: 312G13V701; Material: Grés porcelânico
Type - Pset_ElementShading - Roughness: 304.8 mm
Type - Pset_ManufacturerTypeInformation - Manufacturer: REVIGRÉS
Type - Pset_ProductRequirements - Category: Floors
Type - Pset_QuantityTakeOff - Reference: 312G13V701
Type - IFC.REVIGRÉS-Dados do fabricante-Floor Covering - FabricanteURL: https://www.revigres.pt/; ReferenciaModelo: Locus; NumeroGlobalDeItemComercial: 312G13V701; Acabamento: SILK; Material: Grés porcelânico; IdentificadorDoOperadorEconomico: 501840856; UrlFabricanteArtigo: https://www.revigres.pt/colecoes/locus; PaisOrigem: Portugal
Type - IFC.REVIGRÉS-Dados de desempenho-Floor Covering - Rectilinearidade: ± 0.2% máx.± 0.8 mm; Ortogonalidade: ± 0.2% máx.± 1.5 mm; PlanaridadeDaSuperficie: ± 0.3% máx. ± 1.8 mm; QualidadeDaSuperficie: Cumpre; AbsorcaoDeAgua: < 0.05%; ModuloDeRuptura: > 45 N/mm²; ResistenciaAFlexao: > 2000 N; ResistenciaAAbrasaoProfunda: < 120 mm³; DilatacaoTermicaLinear: ≤ 8,0x10-6 °C-1; ResistenciaAoChoqueTermico: Resiste; DurabilidadeInterior: Cumpre; DurabilidadeResistenciaAoGeloDegelo: Resiste; ResistenciaAoEscorregamentoDIN51130: R9; ResistenciaAoEscorregamentoDIN51097: A; ResistenciaAoEscorregamentoENV51097: A; ResistenciaAoEscorregamentoENV12633: Class 1; ResistenciaAoEscorregamentoBS7976: -; ResistenciaAoEscorregamentoANSIA1371: ≥0,42; ResistenciaAoDeslizamentoENV12633: Class 1; ResistenciaAoDeslizamentoBS7976: -; ResistenciaAsManchas: Class 5; LibertacaoDeCadmio: 0; LibertacaoDeChumbo: 0
Type - IFC.REVIGRÉS-Dados de especificação-Floor Covering - VariacaoTonalidade: 3; NivelDeTrafego: 5; EPavimento: Sim; ERevestimento: Sim; EExterno: Sim
Type - IFC.REVIGRÉS-Dados geométricos-Floor Covering - AlturaNominal: 8.5 mm; ComprimentoNominal: 59.2 mm; LarguraNominal: 59.2 mm
Type - IFC.REVIGRÉS-Dados de sustentabilidade-Floor Covering - EnergiaTermicaExportada: 0; ItemENovo: Sim; ItemEParcialmenteReciclado: 0.29; ItemEReciclado: Sim; VidaÚtilEsperada: 50; SubstanciasPerigosas: Não; PotencialDeEsgotamentoAbioticoDosRecursosFosseis: 203; PotencialDeEsgotamentoAbioticoDosRecursosNaoFosseisMineraisEMetais: 0.000701; PotencialDeAquecimentoGlobalBiogenico: -0.48; CombustiveisFosseisComPotencialDeAquecimentoGlobal: 13.9; PotencialDeAquecimentoGlobalUsoDoSoloEMudancaDeUsoDoSolo: 0.0246; PotencialDeEutrofizacaoFraccaoDeNutrientesQueAtingemOCompartimentoFinalDeAguaDoce: 0.000189; PotencialDeEutrofizacaoFraccaoDeNutrientesQueAtingemOCompartimentoFinalMarinho: 0.0122; EnergiaRecuperada: 0.00739; ConsumoDeAguaDoce: 0.113; UtilizacaoLiquidaDeAguaDoce: 0.113; ResiduosPerigososEliminados: 0.00221; ResiduosNaoPerigososEliminados: 1.83; MassaTotalDeResiduosRadioactivosEliminados: 0.000394; EnergiaElectricaExportada: 1.55; MateriaisParaRecuperacaoDeEnergia: 0.00739; MateriaisParaReciclagem: 0.0253; UnidadeEPD: 1 m²
Type - IFC.REVIGRÉS-Dados gerais-Floor Covering - Nome: REVIGRÉS-LOCUS-BASE-59.2x59.2-SILK-SMOG; TipoProduto: Prensado a seco: grupo BIa UGL | Grés porcelânico técnico; NumeroDeRegistoDAP: EPD-REV-20240006-CCC1-EN; ReferenciaDAP: -; UrlDOP: -
Classification: C3010 (Uniformat)
Pset_CoveringCommon - TotalThickness: 8.5 mm
IFC.REVIGRÉS-Dados do fabricante-Floor Covering - Type: Floor: REVIGRÉS-LOCUS-BASE-59.2x59.2-SILK-SMOG
IFC.REVIGRÉS-Dados de desempenho-Floor Covering - Type: Floor: REVIGRÉS-LOCUS-BASE-59.2x59.2-SILK-SMOG
IFC.REVIGRÉS-Dados de especificação-Floor Covering - Type: Floor: REVIGRÉS-LOCUS-BASE-59.2x59.2-SILK-SMOG
IFC.REVIGRÉS-Dados geométricos-Floor Covering - Type: Floor: REVIGRÉS-LOCUS-BASE-59.2x59.2-SILK-SMOG
IFC.REVIGRÉS-Dados de sustentabilidade-Floor Covering - Type: Floor: REVIGRÉS-LOCUS-BASE-59.2x59.2-SILK-SMOG

# IfcCovering: Floor:REVIGRÉS-LOCUS-BASE-59.2x59.2-SOFT GRIP-ALLOY, Floor:REVIGRÉS-LOCUS-BASE-59.2x59.2-SOFT GRIP-ALLOY:36218
In: Level 1
Type - PredefinedType: CLADDING; Material: REVIGRÉS-LOCUS-BASE-60x60-SOFT GRIP-ALLOY 8.5 mm
Type - Pset_CoveringCommon - Reference: 312F13V671; Material: Grés porcelânico
Type - Pset_ElementShading - Roughness: 304.8 mm
Type - Pset_ManufacturerTypeInformation - Manufacturer: REVIGRÉS
Type - Pset_ProductRequirements - Category: Floors
Type - Pset_QuantityTakeOff - Reference: 312F13V671
Type - IFC.REVIGRÉS-Dados do fabricante-Floor Covering - FabricanteURL: https://www.revigres.pt/; ReferenciaModelo: Locus; NumeroGlobalDeItemComercial: 312F13V671; Acabamento: SOFT; Material: Grés porcelânico; IdentificadorDoOperadorEconomico: 501840856; UrlFabricanteArtigo: https://www.revigres.pt/colecoes/locus; PaisOrigem: Portugal
Type - IFC.REVIGRÉS-Dados de desempenho-Floor Covering - Rectilinearidade: ± 0.2% máx ± 1.0 mm; Ortogonalidade: ± 0.2% máx.± 1.5 mm; PlanaridadeDaSuperficie: ± 0.3% máx. ± 1.8 mm; QualidadeDaSuperficie: Cumpre; AbsorcaoDeAgua: < 0.05%; ModuloDeRuptura: > 45 N/mm²; ResistenciaAFlexao: > 2000 N; ResistenciaAAbrasaoProfunda: < 120 mm³; DilatacaoTermicaLinear: ≤ 8,0x10-6 °C-1; ResistenciaAoChoqueTermico: Resiste; DurabilidadeInterior: Cumpre; DurabilidadeResistenciaAoGeloDegelo: Resiste; ResistenciaAoEscorregamentoDIN51130: R11; ResistenciaAoEscorregamentoDIN51097: A; ResistenciaAoEscorregamentoENV51097: A; ResistenciaAoEscorregamentoENV12633: Class 2; ResistenciaAoEscorregamentoBS7976: > 36; ResistenciaAoEscorregamentoANSIA1371: ≥0,42; ResistenciaAoDeslizamentoENV12633: Class 2; ResistenciaAoDeslizamentoBS7976: > 36; ResistenciaAsManchas: Class 5; LibertacaoDeCadmio: 0; LibertacaoDeChumbo: 0
Type - IFC.REVIGRÉS-Dados de especificação-Floor Covering - VariacaoTonalidade: 3; NivelDeTrafego: 5; EPavimento: Sim; ERevestimento: Sim; EExterno: Sim
Type - IFC.REVIGRÉS-Dados geométricos-Floor Covering - AlturaNominal: 8.5 mm; ComprimentoNominal: 59.2 mm; LarguraNominal: 59.2 mm
Type - IFC.REVIGRÉS-Dados de sustentabilidade-Floor Covering - ItemEParcialmenteReciclado: 0; EnergiaTermicaExportada: 0; ItemENovo: Sim; ItemEReciclado: Não; VidaÚtilEsperada: 50; SubstanciasPerigosas: Não; PotencialDeEsgotamentoAbioticoDosRecursosFosseis: 203; PotencialDeEsgotamentoAbioticoDosRecursosNaoFosseisMineraisEMetais: 0.000701; PotencialDeAquecimentoGlobalBiogenico: -0.48; CombustiveisFosseisComPotencialDeAquecimentoGlobal: 13.9; PotencialDeAquecimentoGlobalUsoDoSoloEMudancaDeUsoDoSolo: 0.0246; PotencialDeEutrofizacaoFraccaoDeNutrientesQueAtingemOCompartimentoFinalDeAguaDoce: 0.000189; PotencialDeEutrofizacaoFraccaoDeNutrientesQueAtingemOCompartimentoFinalMarinho: 0.0122; EnergiaRecuperada: 0.00739; ConsumoDeAguaDoce: 0.113; UtilizacaoLiquidaDeAguaDoce: 0.113; ResiduosPerigososEliminados: 0.00221; ResiduosNaoPerigososEliminados: 1.83; MassaTotalDeResiduosRadioactivosEliminados: 0.000394; EnergiaElectricaExportada: 1.55; MateriaisParaRecuperacaoDeEnergia: 0.00739; MateriaisParaReciclagem: 0.0253; UnidadeEPD: 1 m²
Type - IFC.REVIGRÉS-Dados gerais-Floor Covering - Nome: REVIGRÉS-LOCUS-BASE-59.2x59.2-SOFT GRIP-ALLOY; TipoProduto: Prensado a seco: grupo BIa UGL | Grés porcelânico técnico; NumeroDeRegistoDAP: EPD-REV-20240006-CCC1-EN; ReferenciaDAP: -; UrlDOP: -
Classification: C3010 (Uniformat)
Pset_CoveringCommon - TotalThickness: 8.5 mm
IFC.REVIGRÉS-Dados do fabricante-Floor Covering - Type: Floor: REVIGRÉS-LOCUS-BASE-59.2x59.2-SOFT GRIP-ALLOY
IFC.REVIGRÉS-Dados de desempenho-Floor Covering - Type: Floor: REVIGRÉS-LOCUS-BASE-59.2x59.2-SOFT GRIP-ALLOY
IFC.REVIGRÉS-Dados de especificação-Floor Covering - Type: Floor: REVIGRÉS-LOCUS-BASE-59.2x59.2-SOFT GRIP-ALLOY
IFC.REVIGRÉS-Dados geométricos-Floor Covering - Type: Floor: REVIGRÉS-LOCUS-BASE-59.2x59.2-SOFT GRIP-ALLOY
IFC.REVIGRÉS-Dados de sustentabilidade-Floor Covering - Type: Floor: REVIGRÉS-LOCUS-BASE-59.2x59.2-SOFT GRIP-ALLOY

# IfcCovering: Floor:REVIGRÉS-LOCUS-BASE-59.2x59.2-SOFT GRIP-BONE, Floor:REVIGRÉS-LOCUS-BASE-59.2x59.2-SOFT GRIP-BONE:36670
In: Level 1
Type - PredefinedType: CLADDING; Material: REVIGRÉS-LOCUS-BASE-60x60-SOFT GRIP-BONE 8.5 mm
Type - Pset_CoveringCommon - Reference: 312F13V681; Material: Grés porcelânico
Type - Pset_ElementShading - Roughness: 304.8 mm
Type - Pset_ManufacturerTypeInformation - Manufacturer: REVIGRÉS
Type - Pset_ProductRequirements - Category: Floors
Type - Pset_QuantityTakeOff - Reference: 312F13V681
Type - IFC.REVIGRÉS-Dados do fabricante-Floor Covering - FabricanteURL: https://www.revigres.pt/; ReferenciaModelo: Locus; NumeroGlobalDeItemComercial: 312F13V681; Acabamento: SOFT; Material: Grés porcelânico; IdentificadorDoOperadorEconomico: 501840856; UrlFabricanteArtigo: https://www.revigres.pt/colecoes/locus; PaisOrigem: Portugal
Type - IFC.REVIGRÉS-Dados de desempenho-Floor Covering - Rectilinearidade: ± 0.2% máx ± 1.0 mm; Ortogonalidade: ± 0.2% máx.± 1.5 mm; PlanaridadeDaSuperficie: ± 0.3% máx. ± 1.8 mm; QualidadeDaSuperficie: Cumpre; AbsorcaoDeAgua: < 0.05%; ModuloDeRuptura: > 45 N/mm²; ResistenciaAFlexao: > 2000 N; ResistenciaAAbrasaoProfunda: < 120 mm³; DilatacaoTermicaLinear: ≤ 8,0x10-6 °C-1; ResistenciaAoChoqueTermico: Resiste; DurabilidadeInterior: Cumpre; DurabilidadeResistenciaAoGeloDegelo: Resiste; ResistenciaAoEscorregamentoDIN51130: R11; ResistenciaAoEscorregamentoDIN51097: A; ResistenciaAoEscorregamentoENV51097: A; ResistenciaAoEscorregamentoENV12633: Class 2; ResistenciaAoEscorregamentoBS7976: > 36; ResistenciaAoEscorregamentoANSIA1371: ≥0,42; ResistenciaAoDeslizamentoENV12633: Class 2; ResistenciaAoDeslizamentoBS7976: > 36; ResistenciaAsManchas: Class 5; LibertacaoDeCadmio: 0; LibertacaoDeChumbo: 0
Type - IFC.REVIGRÉS-Dados de especificação-Floor Covering - VariacaoTonalidade: 3; NivelDeTrafego: 5; EPavimento: Sim; ERevestimento: Sim; EExterno: Sim
Type - IFC.REVIGRÉS-Dados geométricos-Floor Covering - AlturaNominal: 8.5 mm; ComprimentoNominal: 59.2 mm; LarguraNominal: 59.2 mm
Type - IFC.REVIGRÉS-Dados de sustentabilidade-Floor Covering - ItemEParcialmenteReciclado: 0; EnergiaTermicaExportada: 0; ItemENovo: Sim; ItemEReciclado: Não; VidaÚtilEsperada: 50; SubstanciasPerigosas: Não; PotencialDeEsgotamentoAbioticoDosRecursosFosseis: 203; PotencialDeEsgotamentoAbioticoDosRecursosNaoFosseisMineraisEMetais: 0.000701; PotencialDeAquecimentoGlobalBiogenico: -0.48; CombustiveisFosseisComPotencialDeAquecimentoGlobal: 13.9; PotencialDeAquecimentoGlobalUsoDoSoloEMudancaDeUsoDoSolo: 0.0246; PotencialDeEutrofizacaoFraccaoDeNutrientesQueAtingemOCompartimentoFinalDeAguaDoce: 0.000189; PotencialDeEutrofizacaoFraccaoDeNutrientesQueAtingemOCompartimentoFinalMarinho: 0.0122; EnergiaRecuperada: 0.00739; ConsumoDeAguaDoce: 0.113; UtilizacaoLiquidaDeAguaDoce: 0.113; ResiduosPerigososEliminados: 0.00221; ResiduosNaoPerigososEliminados: 1.83; MassaTotalDeResiduosRadioactivosEliminados: 0.000394; EnergiaElectricaExportada: 1.55; MateriaisParaRecuperacaoDeEnergia: 0.00739; MateriaisParaReciclagem: 0.0253; UnidadeEPD: 1 m²
Type - IFC.REVIGRÉS-Dados gerais-Floor Covering - Nome: REVIGRÉS-LOCUS-BASE-59.2x59.2-SOFT GRIP-BONE; TipoProduto: Prensado a seco: grupo BIa UGL | Grés porcelânico técnico; NumeroDeRegistoDAP: EPD-REV-20240006-CCC1-EN; ReferenciaDAP: -; UrlDOP: -
Classification: C3010 (Uniformat)
Pset_CoveringCommon - TotalThickness: 8.5 mm
IFC.REVIGRÉS-Dados do fabricante-Floor Covering - Type: Floor: REVIGRÉS-LOCUS-BASE-59.2x59.2-SOFT GRIP-BONE
IFC.REVIGRÉS-Dados de desempenho-Floor Covering - Type: Floor: REVIGRÉS-LOCUS-BASE-59.2x59.2-SOFT GRIP-BONE
IFC.REVIGRÉS-Dados de especificação-Floor Covering - Type: Floor: REVIGRÉS-LOCUS-BASE-59.2x59.2-SOFT GRIP-BONE
IFC.REVIGRÉS-Dados geométricos-Floor Covering - Type: Floor: REVIGRÉS-LOCUS-BASE-59.2x59.2-SOFT GRIP-BONE
IFC.REVIGRÉS-Dados de sustentabilidade-Floor Covering - Type: Floor: REVIGRÉS-LOCUS-BASE-59.2x59.2-SOFT GRIP-BONE

# IfcCovering: Floor:REVIGRÉS-LOCUS-BASE-59.2x59.2-SOFT GRIP-GRIS, Floor:REVIGRÉS-LOCUS-BASE-59.2x59.2-SOFT GRIP-GRIS:37340
In: Level 1
Type - PredefinedType: CLADDING; Material: REVIGRÉS-LOCUS-BASE-60x60-SOFT GRIP-GRIS 8.5 mm
Type - Pset_CoveringCommon - Reference: 312F13V691; Material: Grés porcelânico
Type - Pset_ElementShading - Roughness: 304.8 mm
Type - Pset_ManufacturerTypeInformation - Manufacturer: REVIGRÉS
Type - Pset_ProductRequirements - Category: Floors
Type - Pset_QuantityTakeOff - Reference: 312F13V691
Type - IFC.REVIGRÉS-Dados do fabricante-Floor Covering - FabricanteURL: https://www.revigres.pt/; ReferenciaModelo: Locus; NumeroGlobalDeItemComercial: 312F13V691; Acabamento: SOFT; Material: Grés porcelânico; IdentificadorDoOperadorEconomico: 501840856; UrlFabricanteArtigo: https://www.revigres.pt/colecoes/locus; PaisOrigem: Portugal
Type - IFC.REVIGRÉS-Dados de desempenho-Floor Covering - Rectilinearidade: ± 0.2% máx ± 1.0 mm; Ortogonalidade: ± 0.2% máx.± 1.5 mm; PlanaridadeDaSuperficie: ± 0.3% máx. ± 1.8 mm; QualidadeDaSuperficie: Cumpre; AbsorcaoDeAgua: < 0.05%; ModuloDeRuptura: > 45 N/mm²; ResistenciaAFlexao: > 2000 N; ResistenciaAAbrasaoProfunda: < 120 mm³; DilatacaoTermicaLinear: ≤ 8,0x10-6 °C-1; ResistenciaAoChoqueTermico: Resiste; DurabilidadeInterior: Cumpre; DurabilidadeResistenciaAoGeloDegelo: Resiste; ResistenciaAoEscorregamentoDIN51130: R11; ResistenciaAoEscorregamentoDIN51097: A; ResistenciaAoEscorregamentoENV51097: A; ResistenciaAoEscorregamentoENV12633: Class 2; ResistenciaAoEscorregamentoBS7976: > 36; ResistenciaAoEscorregamentoANSIA1371: ≥0,42; ResistenciaAoDeslizamentoENV12633: Class 2; ResistenciaAoDeslizamentoBS7976: > 36; ResistenciaAsManchas: Class 5; LibertacaoDeCadmio: 0; LibertacaoDeChumbo: 0
Type - IFC.REVIGRÉS-Dados de especificação-Floor Covering - VariacaoTonalidade: 3; NivelDeTrafego: 5; EPavimento: Sim; ERevestimento: Sim; EExterno: Sim
Type - IFC.REVIGRÉS-Dados geométricos-Floor Covering - AlturaNominal: 8.5 mm; ComprimentoNominal: 59.2 mm; LarguraNominal: 59.2 mm
Type - IFC.REVIGRÉS-Dados de sustentabilidade-Floor Covering - EnergiaTermicaExportada: 0; ItemENovo: Sim; ItemEParcialmenteReciclado: 0.23; ItemEReciclado: Sim; VidaÚtilEsperada: 50; SubstanciasPerigosas: Não; PotencialDeEsgotamentoAbioticoDosRecursosFosseis: 203; PotencialDeEsgotamentoAbioticoDosRecursosNaoFosseisMineraisEMetais: 0.000701; PotencialDeAquecimentoGlobalBiogenico: -0.48; CombustiveisFosseisComPotencialDeAquecimentoGlobal: 13.9; PotencialDeAquecimentoGlobalUsoDoSoloEMudancaDeUsoDoSolo: 0.0246; PotencialDeEutrofizacaoFraccaoDeNutrientesQueAtingemOCompartimentoFinalDeAguaDoce: 0.000189; PotencialDeEutrofizacaoFraccaoDeNutrientesQueAtingemOCompartimentoFinalMarinho: 0.0122; EnergiaRecuperada: 0.00739; ConsumoDeAguaDoce: 0.113; UtilizacaoLiquidaDeAguaDoce: 0.113; ResiduosPerigososEliminados: 0.00221; ResiduosNaoPerigososEliminados: 1.83; MassaTotalDeResiduosRadioactivosEliminados: 0.000394; EnergiaElectricaExportada: 1.55; MateriaisParaRecuperacaoDeEnergia: 0.00739; MateriaisParaReciclagem: 0.0253; UnidadeEPD: 1 m²
Type - IFC.REVIGRÉS-Dados gerais-Floor Covering - Nome: REVIGRÉS-LOCUS-BASE-59.2x59.2-SOFT GRIP-GRIS; TipoProduto: Prensado a seco: grupo BIa UGL | Grés porcelânico técnico; NumeroDeRegistoDAP: EPD-REV-20240006-CCC1-EN; ReferenciaDAP: -; UrlDOP: -
Classification: C3010 (Uniformat)
Pset_CoveringCommon - TotalThickness: 8.5 mm
IFC.REVIGRÉS-Dados do fabricante-Floor Covering - Type: Floor: REVIGRÉS-LOCUS-BASE-59.2x59.2-SOFT GRIP-GRIS
IFC.REVIGRÉS-Dados de desempenho-Floor Covering - Type: Floor: REVIGRÉS-LOCUS-BASE-59.2x59.2-SOFT GRIP-GRIS
IFC.REVIGRÉS-Dados de especificação-Floor Covering - Type: Floor: REVIGRÉS-LOCUS-BASE-59.2x59.2-SOFT GRIP-GRIS
IFC.REVIGRÉS-Dados geométricos-Floor Covering - Type: Floor: REVIGRÉS-LOCUS-BASE-59.2x59.2-SOFT GRIP-GRIS
IFC.REVIGRÉS-Dados de sustentabilidade-Floor Covering - Type: Floor: REVIGRÉS-LOCUS-BASE-59.2x59.2-SOFT GRIP-GRIS

# IfcCovering: Floor:REVIGRÉS-LOCUS-BASE-59.2x59.2-SOFT GRIP-SMOG, Floor:REVIGRÉS-LOCUS-BASE-59.2x59.2-SOFT GRIP-SMOG:37855
In: Level 1
Type - PredefinedType: CLADDING; Material: REVIGRÉS-LOCUS-BASE-60x60-SOFT GRIP-SMOG 8.5 mm
Type - Pset_CoveringCommon - Reference: 312F13V701; Material: Grés porcelânico
Type - Pset_ElementShading - Roughness: 304.8 mm
Type - Pset_ManufacturerTypeInformation - Manufacturer: REVIGRÉS
Type - Pset_ProductRequirements - Category: Floors
Type - Pset_QuantityTakeOff - Reference: 312F13V701
Type - IFC.REVIGRÉS-Dados do fabricante-Floor Covering - FabricanteURL: https://www.revigres.pt/; ReferenciaModelo: Locus; NumeroGlobalDeItemComercial: 312F13V701; Acabamento: SOFT; Material: Grés porcelânico; IdentificadorDoOperadorEconomico: 501840856; UrlFabricanteArtigo: https://www.revigres.pt/colecoes/locus; PaisOrigem: Portugal
Type - IFC.REVIGRÉS-Dados de desempenho-Floor Covering - Rectilinearidade: ± 0.2% máx ± 1.0 mm; Ortogonalidade: ± 0.2% máx.± 1.5 mm; PlanaridadeDaSuperficie: ± 0.3% máx. ± 1.8 mm; QualidadeDaSuperficie: Cumpre; AbsorcaoDeAgua: < 0.05%; ModuloDeRuptura: > 45 N/mm²; ResistenciaAFlexao: > 2000 N; ResistenciaAAbrasaoProfunda: < 120 mm³; DilatacaoTermicaLinear: ≤ 8,0x10-6 °C-1; ResistenciaAoChoqueTermico: Resiste; DurabilidadeInterior: Cumpre; DurabilidadeResistenciaAoGeloDegelo: Resiste; ResistenciaAoEscorregamentoDIN51130: R11; ResistenciaAoEscorregamentoDIN51097: A; ResistenciaAoEscorregamentoENV51097: A; ResistenciaAoEscorregamentoENV12633: Class 2; ResistenciaAoEscorregamentoBS7976: > 36; ResistenciaAoEscorregamentoANSIA1371: ≥0,42; ResistenciaAoDeslizamentoENV12633: Class 2; ResistenciaAoDeslizamentoBS7976: > 36; ResistenciaAsManchas: Class 5; LibertacaoDeCadmio: 0; LibertacaoDeChumbo: 0
Type - IFC.REVIGRÉS-Dados de especificação-Floor Covering - VariacaoTonalidade: 3; NivelDeTrafego: 5; EPavimento: Sim; ERevestimento: Sim; EExterno: Sim
Type - IFC.REVIGRÉS-Dados geométricos-Floor Covering - AlturaNominal: 8.5 mm; ComprimentoNominal: 59.2 mm; LarguraNominal: 59.2 mm
Type - IFC.REVIGRÉS-Dados de sustentabilidade-Floor Covering - EnergiaTermicaExportada: 0; ItemENovo: Sim; ItemEParcialmenteReciclado: 0.29; ItemEReciclado: Sim; VidaÚtilEsperada: 50; SubstanciasPerigosas: Não; PotencialDeEsgotamentoAbioticoDosRecursosFosseis: 203; PotencialDeEsgotamentoAbioticoDosRecursosNaoFosseisMineraisEMetais: 0.000701; PotencialDeAquecimentoGlobalBiogenico: -0.48; CombustiveisFosseisComPotencialDeAquecimentoGlobal: 13.9; PotencialDeAquecimentoGlobalUsoDoSoloEMudancaDeUsoDoSolo: 0.0246; PotencialDeEutrofizacaoFraccaoDeNutrientesQueAtingemOCompartimentoFinalDeAguaDoce: 0.000189; PotencialDeEutrofizacaoFraccaoDeNutrientesQueAtingemOCompartimentoFinalMarinho: 0.0122; EnergiaRecuperada: 0.00739; ConsumoDeAguaDoce: 0.113; UtilizacaoLiquidaDeAguaDoce: 0.113; ResiduosPerigososEliminados: 0.00221; ResiduosNaoPerigososEliminados: 1.83; MassaTotalDeResiduosRadioactivosEliminados: 0.000394; EnergiaElectricaExportada: 1.55; MateriaisParaRecuperacaoDeEnergia: 0.00739; MateriaisParaReciclagem: 0.0253; UnidadeEPD: 1 m²
Type - IFC.REVIGRÉS-Dados gerais-Floor Covering - Nome: REVIGRÉS-LOCUS-BASE-59.2x59.2-SOFT GRIP-SMOG; TipoProduto: Prensado a seco: grupo BIa UGL | Grés porcelânico técnico; NumeroDeRegistoDAP: EPD-REV-20240006-CCC1-EN; ReferenciaDAP: -; UrlDOP: -
Classification: C3010 (Uniformat)
Pset_CoveringCommon - TotalThickness: 8.5 mm
IFC.REVIGRÉS-Dados do fabricante-Floor Covering - Type: Floor: REVIGRÉS-LOCUS-BASE-59.2x59.2-SOFT GRIP-SMOG
IFC.REVIGRÉS-Dados de desempenho-Floor Covering - Type: Floor: REVIGRÉS-LOCUS-BASE-59.2x59.2-SOFT GRIP-SMOG
IFC.REVIGRÉS-Dados de especificação-Floor Covering - Type: Floor: REVIGRÉS-LOCUS-BASE-59.2x59.2-SOFT GRIP-SMOG
IFC.REVIGRÉS-Dados geométricos-Floor Covering - Type: Floor: REVIGRÉS-LOCUS-BASE-59.2x59.2-SOFT GRIP-SMOG
IFC.REVIGRÉS-Dados de sustentabilidade-Floor Covering - Type: Floor: REVIGRÉS-LOCUS-BASE-59.2x59.2-SOFT GRIP-SMOG

# IfcCovering: Floor:REVIGRÉS-LOCUS-BASE-88.9x88.9-SILK-ALLOY, Floor:REVIGRÉS-LOCUS-BASE-88.9x88.9-SILK-ALLOY:102538
In: Level 1
Type - PredefinedType: CLADDING; Material: REVIGRÉS-LOCUS-BASE-90x90-SILK-ALLOY 10.5 mm
Type - Pset_CoveringCommon - Reference: 312GK7V671; Material: Grés porcelânico
Type - Pset_ElementShading - Roughness: 304.8 mm
Type - Pset_ManufacturerTypeInformation - Manufacturer: REVIGRÉS
Type - Pset_ProductRequirements - Category: Floors
Type - Pset_QuantityTakeOff - Reference: 312GK7V671
Type - IFC.REVIGRÉS-Dados do fabricante-Floor Covering - FabricanteURL: https://www.revigres.pt/; ReferenciaModelo: Locus; NumeroGlobalDeItemComercial: 312GK7V691; Acabamento: SILK; Material: Grés porcelânico; IdentificadorDoOperadorEconomico: 501840856; UrlFabricanteArtigo: https://www.revigres.pt/colecoes/locus; PaisOrigem: Portugal
Type - IFC.REVIGRÉS-Dados de desempenho-Floor Covering - Rectilinearidade: ± 0.2% máx.± 0.8 mm; Ortogonalidade: ± 0.2% máx.± 1.5 mm; PlanaridadeDaSuperficie: ± 0.3% máx. ± 1.8 mm; QualidadeDaSuperficie: Cumpre; AbsorcaoDeAgua: < 0.05%; ModuloDeRuptura: > 45 N/mm²; ResistenciaAFlexao: > 2000 N; ResistenciaAAbrasaoProfunda: < 120 mm³; DilatacaoTermicaLinear: ≤ 8,0x10-6 °C-1; ResistenciaAoChoqueTermico: Resiste; DurabilidadeInterior: Cumpre; DurabilidadeResistenciaAoGeloDegelo: Resiste; ResistenciaAoEscorregamentoDIN51130: R9; ResistenciaAoEscorregamentoDIN51097: A; ResistenciaAoEscorregamentoENV51097: A; ResistenciaAoEscorregamentoENV12633: Class 1; ResistenciaAoEscorregamentoBS7976: -; ResistenciaAoEscorregamentoANSIA1371: ≥0,42; ResistenciaAoDeslizamentoENV12633: Class 1; ResistenciaAoDeslizamentoBS7976: -; ResistenciaAsManchas: Class 5; LibertacaoDeCadmio: 0; LibertacaoDeChumbo: 0
Type - IFC.REVIGRÉS-Dados de especificação-Floor Covering - VariacaoTonalidade: 3; NivelDeTrafego: 5; EPavimento: Sim; ERevestimento: Sim; EExterno: Sim
Type - IFC.REVIGRÉS-Dados geométricos-Floor Covering - AlturaNominal: 10.5 mm; ComprimentoNominal: 88.9 mm; LarguraNominal: 88.9 mm
Type - IFC.REVIGRÉS-Dados de sustentabilidade-Floor Covering - EnergiaTermicaExportada: 0; ItemENovo: Sim; ItemEParcialmenteReciclado: 0.23; ItemEReciclado: Sim; VidaÚtilEsperada: 50; SubstanciasPerigosas: Não; PotencialDeEsgotamentoAbioticoDosRecursosFosseis: 203; PotencialDeEsgotamentoAbioticoDosRecursosNaoFosseisMineraisEMetais: 0.000701; PotencialDeAquecimentoGlobalBiogenico: -0.48; CombustiveisFosseisComPotencialDeAquecimentoGlobal: 13.9; PotencialDeAquecimentoGlobalUsoDoSoloEMudancaDeUsoDoSolo: 0.0246; PotencialDeEutrofizacaoFraccaoDeNutrientesQueAtingemOCompartimentoFinalDeAguaDoce: 0.000189; PotencialDeEutrofizacaoFraccaoDeNutrientesQueAtingemOCompartimentoFinalMarinho: 0.0122; EnergiaRecuperada: 0.00739; ConsumoDeAguaDoce: 0.113; UtilizacaoLiquidaDeAguaDoce: 0.113; ResiduosPerigososEliminados: 0.00221; ResiduosNaoPerigososEliminados: 1.83; MassaTotalDeResiduosRadioactivosEliminados: 0.000394; EnergiaElectricaExportada: 1.55; MateriaisParaRecuperacaoDeEnergia: 0.00739; MateriaisParaReciclagem: 0.0253; UnidadeEPD: 1 m²
Type - IFC.REVIGRÉS-Dados gerais-Floor Covering - Nome: REVIGRÉS-LOCUS-BASE-88.9x88.9-SILK-GRIS; TipoProduto: Prensado a seco: grupo BIa UGL | Grés porcelânico técnico; NumeroDeRegistoDAP: EPD-REV-20240006-CCC1-EN; ReferenciaDAP: -; UrlDOP: -
Classification: C3010 (Uniformat)
Pset_CoveringCommon - TotalThickness: 10.5 mm
IFC.REVIGRÉS-Dados do fabricante-Floor Covering - Type: Floor: REVIGRÉS-LOCUS-BASE-88.9x88.9-SILK-ALLOY
IFC.REVIGRÉS-Dados de desempenho-Floor Covering - Type: Floor: REVIGRÉS-LOCUS-BASE-88.9x88.9-SILK-ALLOY
IFC.REVIGRÉS-Dados de especificação-Floor Covering - Type: Floor: REVIGRÉS-LOCUS-BASE-88.9x88.9-SILK-ALLOY
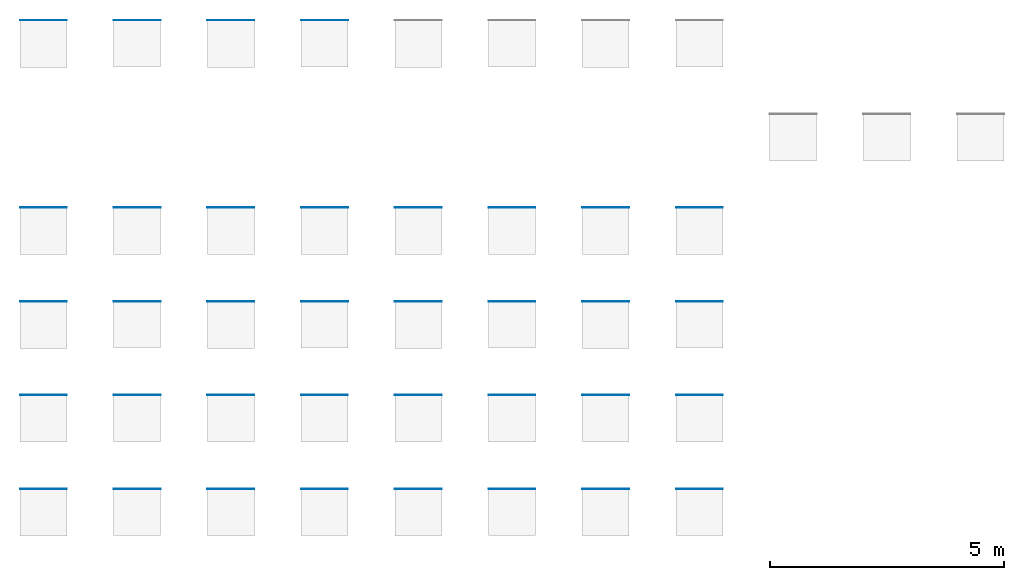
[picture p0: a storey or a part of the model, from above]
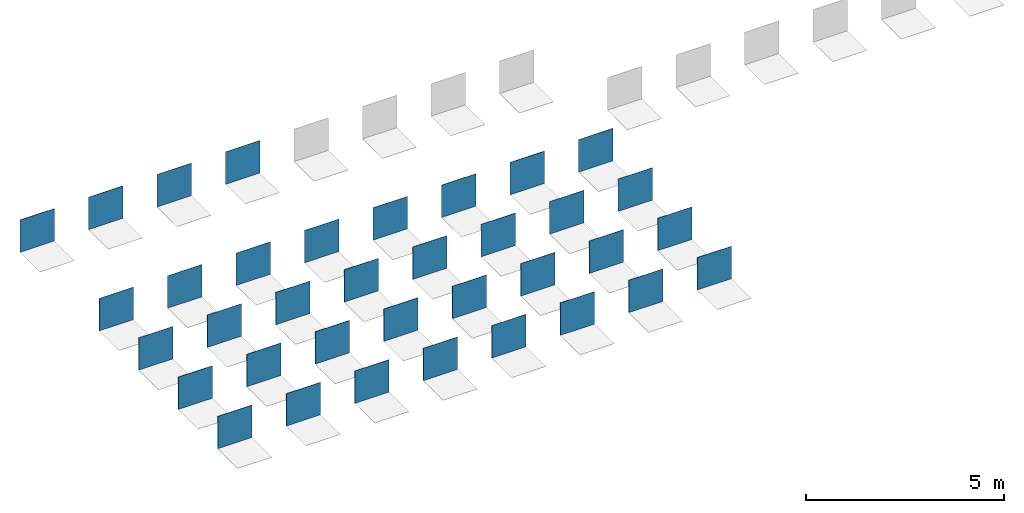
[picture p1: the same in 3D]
Properties of the parts of a building model (IFC2X3), part 4 of 7

# IfcWallStandardCase: Basic Wall:REVIGRÉS-LOCUS-BASE-29.5x29.5-SILK-QUILT BONE, Basic Wall:REVIGRÉS-LOCUS-BASE-29.5x29.5-SILK-QUILT BONE:40819
Type - IFC.REVIGRÉS-Dados do fabricante-Wall Covering - FabricanteURL: https://www.revigres.pt/; ReferenciaModelo: Locus; NumeroGlobalDeItemComercial: 312G12V641; Acabamento: SILK; Material: Grés porcelânico; IdentificadorDoOperadorEconomico: 501840856; UrlFabricanteArtigo: https://www.revigres.pt/colecoes/locus; PaisOrigem: Portugal
Type - IFC.REVIGRÉS-Dados de desempenho-Wall Covering - Rectilinearidade: ± 0.2% máx.± 0.8 mm; Ortogonalidade: ± 0.2% máx.± 1.5 mm; PlanaridadeDaSuperficie: ± 0.3% máx. ± 1.8 mm; QualidadeDaSuperficie: Cumpre; AbsorcaoDeAgua: < 0.05%; ModuloDeRuptura: > 45 N/mm²; ResistenciaAFlexao: > 2000 N; ResistenciaAAbrasaoProfunda: < 120 mm³; DilatacaoTermicaLinear: ≤ 8,0x10-6 °C-1; ResistenciaAoChoqueTermico: Resiste; DurabilidadeInterior: Cumpre; DurabilidadeResistenciaAoGeloDegelo: Resiste; ResistenciaAoEscorregamentoDIN51130: R9; ResistenciaAoEscorregamentoDIN51097: A; ResistenciaAoEscorregamentoENV51097: A; ResistenciaAoEscorregamentoENV12633: Class 1; ResistenciaAoEscorregamentoBS7976: -; ResistenciaAoEscorregamentoANSIA1371: ≥0,42; ResistenciaAoDeslizamentoENV12633: Class 1; ResistenciaAoDeslizamentoBS7976: -; ResistenciaAsManchas: Class 5; LibertacaoDeCadmio: 0; LibertacaoDeChumbo: 0
Type - IFC.REVIGRÉS-Dados de especificação-Wall Covering - VariacaoTonalidade: 3; NivelDeTrafego: 5; EPavimento: Sim; ERevestimento: Sim; EExterno: Sim
Type - IFC.REVIGRÉS-Dados geométricos-Wall Covering - AlturaNominal: 8.5 mm; ComprimentoNominal: 29.5 mm; LarguraNominal: 29.5 mm
Type - IFC.REVIGRÉS-Dados de sustentabilidade-Wall Covering - ItemEParcialmenteReciclado: 0; PotencialPrivacaoDeAguaConsumoDeAguaPonderado: 4.5; EnergiaTermicaExportada: 0; ItemENovo: Sim; ItemEReciclado: Não; VidaÚtilEsperada: 50; SubstanciasPerigosas: Não; PotencialDeEsgotamentoAbioticoDosRecursosFosseis: 203; PotencialDeEsgotamentoAbioticoDosRecursosNaoFosseisMineraisEMetais: 0.000701; PotencialDeAquecimentoGlobalBiogenico: -0.48; CombustiveisFosseisComPotencialDeAquecimentoGlobal: 13.9; PotencialDeAquecimentoGlobalUsoDoSoloEMudancaDeUsoDoSolo: 0.0246; PotencialDeEutrofizacaoFraccaoDeNutrientesQueAtingemOCompartimentoFinalDeAguaDoce: 0.000189; PotencialDeEutrofizacaoFraccaoDeNutrientesQueAtingemOCompartimentoFinalMarinho: 0.0122; EnergiaRecuperada: 0.00739; ConsumoDeAguaDoce: 0.113; UtilizacaoLiquidaDeAguaDoce: 0.113; ResiduosPerigososEliminados: 0.00221; ResiduosNaoPerigososEliminados: 1.83; MassaTotalDeResiduosRadioactivosEliminados: 0.000394; EnergiaElectricaExportada: 1.55; MateriaisParaRecuperacaoDeEnergia: 0.00739; MateriaisParaReciclagem: 0.0253; UnidadeEPD: 1 m²
Type - IFC.REVIGRÉS-Dados gerais-Wall Covering - Nome: REVIGRÉS-LOCUS-BASE-29.5x29.5-SILK-QUILT BONE; TipoProduto: Prensado a seco: grupo BIa UGL | Grés porcelânico técnico; NumeroDeRegistoDAP: EPD-REV-20240006-CCC1-EN; ReferenciaDAP: -; UrlDOP: -
Classification: C3010 (Uniformat)
Pset_WallCommon - ExtendToStructure: no; LoadBearing: no
IFC.REVIGRÉS-Dados do fabricante-Wall Covering - Type: Basic Wall: REVIGRÉS-LOCUS-BASE-29.5x29.5-SILK-QUILT BONE
IFC.REVIGRÉS-Dados de desempenho-Wall Covering - Type: Basic Wall: REVIGRÉS-LOCUS-BASE-29.5x29.5-SILK-QUILT BONE
IFC.REVIGRÉS-Dados de especificação-Wall Covering - Type: Basic Wall: REVIGRÉS-LOCUS-BASE-29.5x29.5-SILK-QUILT BONE
IFC.REVIGRÉS-Dados geométricos-Wall Covering - Type: Basic Wall: REVIGRÉS-LOCUS-BASE-29.5x29.5-SILK-QUILT BONE
IFC.REVIGRÉS-Dados de sustentabilidade-Wall Covering - Type: Basic Wall: REVIGRÉS-LOCUS-BASE-29.5x29.5-SILK-QUILT BONE

# IfcWallStandardCase: Basic Wall:REVIGRÉS-LOCUS-BASE-29.5x29.5-SILK-QUILT GREEN, Basic Wall:REVIGRÉS-LOCUS-BASE-29.5x29.5-SILK-QUILT GREEN:40820
In: Level 1
Type - PredefinedType: STANDARD; Material: REVIGRÉS-LOCUS-BASE-30X30-SILK-QUILT GREEN 8.5 mm
Type - Pset_ElementShading - Roughness: 304.8 mm
Type - Pset_ManufacturerTypeInformation - Manufacturer: REVIGRÉS
Type - Pset_ProductRequirements - Category: Walls
Type - Pset_QuantityTakeOff - Reference: 312G12V661
Type - Pset_ReinforcementBarPitchOfWall - Description: Stone effect in wall and floor full body porcelain tile; Reference: 312G12V661
Type - Pset_WallCommon - IsExternal: no; Reference: 312G12V661
Type - IFC.REVIGRÉS-Dados do fabricante-Wall Covering - FabricanteURL: https://www.revigres.pt/; ReferenciaModelo: Locus; NumeroGlobalDeItemComercial: 312G12V661; Acabamento: SILK; Material: Grés porcelânico; IdentificadorDoOperadorEconomico: 501840856; UrlFabricanteArtigo: https://www.revigres.pt/colecoes/locus; PaisOrigem: Portugal
Type - IFC.REVIGRÉS-Dados de desempenho-Wall Covering - Rectilinearidade: ± 0.2% máx.± 0.8 mm; Ortogonalidade: ± 0.2% máx.± 1.5 mm; PlanaridadeDaSuperficie: ± 0.3% máx. ± 1.8 mm; QualidadeDaSuperficie: Cumpre; AbsorcaoDeAgua: < 0.05%; ModuloDeRuptura: > 45 N/mm²; ResistenciaAFlexao: > 2000 N; ResistenciaAAbrasaoProfunda: < 120 mm³; DilatacaoTermicaLinear: ≤ 8,0x10-6 °C-1; ResistenciaAoChoqueTermico: Resiste; DurabilidadeInterior: Cumpre; DurabilidadeResistenciaAoGeloDegelo: Resiste; ResistenciaAoEscorregamentoDIN51130: R9; ResistenciaAoEscorregamentoDIN51097: A; ResistenciaAoEscorregamentoENV51097: A; ResistenciaAoEscorregamentoENV12633: Class 1; ResistenciaAoEscorregamentoBS7976: -; ResistenciaAoEscorregamentoANSIA1371: ≥0,42; ResistenciaAoDeslizamentoENV12633: Class 1; ResistenciaAoDeslizamentoBS7976: -; ResistenciaAsManchas: Class 5; LibertacaoDeCadmio: 0; LibertacaoDeChumbo: 0
Type - IFC.REVIGRÉS-Dados de especificação-Wall Covering - VariacaoTonalidade: 3; NivelDeTrafego: 5; EPavimento: Sim; ERevestimento: Sim; EExterno: Sim
Type - IFC.REVIGRÉS-Dados geométricos-Wall Covering - AlturaNominal: 8.5 mm; ComprimentoNominal: 29.5 mm; LarguraNominal: 29.5 mm
Type - IFC.REVIGRÉS-Dados de sustentabilidade-Wall Covering - ItemEParcialmenteReciclado: 0; PotencialPrivacaoDeAguaConsumoDeAguaPonderado: 4.5; EnergiaTermicaExportada: 0; ItemENovo: Sim; ItemEReciclado: Não; VidaÚtilEsperada: 50; SubstanciasPerigosas: Não; PotencialDeEsgotamentoAbioticoDosRecursosFosseis: 203; PotencialDeEsgotamentoAbioticoDosRecursosNaoFosseisMineraisEMetais: 0.000701; PotencialDeAquecimentoGlobalBiogenico: -0.48; CombustiveisFosseisComPotencialDeAquecimentoGlobal: 13.9; PotencialDeAquecimentoGlobalUsoDoSoloEMudancaDeUsoDoSolo: 0.0246; PotencialDeEutrofizacaoFraccaoDeNutrientesQueAtingemOCompartimentoFinalDeAguaDoce: 0.000189; PotencialDeEutrofizacaoFraccaoDeNutrientesQueAtingemOCompartimentoFinalMarinho: 0.0122; EnergiaRecuperada: 0.00739; ConsumoDeAguaDoce: 0.113; UtilizacaoLiquidaDeAguaDoce: 0.113; ResiduosPerigososEliminados: 0.00221; ResiduosNaoPerigososEliminados: 1.83; MassaTotalDeResiduosRadioactivosEliminados: 0.000394; EnergiaElectricaExportada: 1.55; MateriaisParaRecuperacaoDeEnergia: 0.00739; MateriaisParaReciclagem: 0.0253; UnidadeEPD: 1 m²
Type - IFC.REVIGRÉS-Dados gerais-Wall Covering - Nome: REVIGRÉS-LOCUS-BASE-29.5x29.5-SILK-QUILT GREEN; TipoProduto: Prensado a seco: grupo BIa UGL | Grés porcelânico técnico; NumeroDeRegistoDAP: EPD-REV-20240006-CCC1-EN; ReferenciaDAP: -; UrlDOP: -
Classification: C3010 (Uniformat)
Pset_WallCommon - ExtendToStructure: no; LoadBearing: no
IFC.REVIGRÉS-Dados do fabricante-Wall Covering - Type: Basic Wall: REVIGRÉS-LOCUS-BASE-29.5x29.5-SILK-QUILT GREEN
IFC.REVIGRÉS-Dados de desempenho-Wall Covering - Type: Basic Wall: REVIGRÉS-LOCUS-BASE-29.5x29.5-SILK-QUILT GREEN
IFC.REVIGRÉS-Dados de especificação-Wall Covering - Type: Basic Wall: REVIGRÉS-LOCUS-BASE-29.5x29.5-SILK-QUILT GREEN
IFC.REVIGRÉS-Dados geométricos-Wall Covering - Type: Basic Wall: REVIGRÉS-LOCUS-BASE-29.5x29.5-SILK-QUILT GREEN
IFC.REVIGRÉS-Dados de sustentabilidade-Wall Covering - Type: Basic Wall: REVIGRÉS-LOCUS-BASE-29.5x29.5-SILK-QUILT GREEN

# IfcWallStandardCase: Basic Wall:REVIGRÉS-LOCUS-BASE-29.5x29.5-SILK-QUILT GRIS, Basic Wall:REVIGRÉS-LOCUS-BASE-29.5x29.5-SILK-QUILT GRIS:40821
In: Level 1
Type - PredefinedType: STANDARD; Material: REVIGRÉS-LOCUS-BASE-30X30-SILK-QUILT GRIS 8.5 mm
Type - Pset_ElementShading - Roughness: 304.8 mm
Type - Pset_ManufacturerTypeInformation - Manufacturer: REVIGRÉS
Type - Pset_ProductRequirements - Category: Walls
Type - Pset_QuantityTakeOff - Reference: 312G12V651
Type - Pset_ReinforcementBarPitchOfWall - Description: Stone effect in wall and floor full body porcelain tile; Reference: 312G12V651
Type - Pset_WallCommon - IsExternal: no; Reference: 312G12V651
Type - IFC.REVIGRÉS-Dados do fabricante-Wall Covering - FabricanteURL: https://www.revigres.pt/; ReferenciaModelo: Locus; NumeroGlobalDeItemComercial: 312G12V651; Acabamento: SILK; Material: Grés porcelânico; IdentificadorDoOperadorEconomico: 501840856; UrlFabricanteArtigo: https://www.revigres.pt/colecoes/locus; PaisOrigem: Portugal
Type - IFC.REVIGRÉS-Dados de desempenho-Wall Covering - Rectilinearidade: ± 0.2% máx.± 0.8 mm; Ortogonalidade: ± 0.2% máx.± 1.5 mm; PlanaridadeDaSuperficie: ± 0.3% máx. ± 1.8 mm; QualidadeDaSuperficie: Cumpre; AbsorcaoDeAgua: < 0.05%; ModuloDeRuptura: > 45 N/mm²; ResistenciaAFlexao: > 2000 N; ResistenciaAAbrasaoProfunda: < 120 mm³; DilatacaoTermicaLinear: ≤ 8,0x10-6 °C-1; ResistenciaAoChoqueTermico: Resiste; DurabilidadeInterior: Cumpre; DurabilidadeResistenciaAoGeloDegelo: Resiste; ResistenciaAoEscorregamentoDIN51130: R9; ResistenciaAoEscorregamentoDIN51097: A; ResistenciaAoEscorregamentoENV51097: A; ResistenciaAoEscorregamentoENV12633: Class 1; ResistenciaAoEscorregamentoBS7976: -; ResistenciaAoEscorregamentoANSIA1371: ≥0,42; ResistenciaAoDeslizamentoENV12633: Class 1; ResistenciaAoDeslizamentoBS7976: -; ResistenciaAsManchas: Class 5; LibertacaoDeCadmio: 0; LibertacaoDeChumbo: 0
Type - IFC.REVIGRÉS-Dados de especificação-Wall Covering - VariacaoTonalidade: 3; NivelDeTrafego: 5; EPavimento: Sim; ERevestimento: Sim; EExterno: Sim
Type - IFC.REVIGRÉS-Dados geométricos-Wall Covering - AlturaNominal: 8.5 mm; ComprimentoNominal: 29.5 mm; LarguraNominal: 29.5 mm
Type - IFC.REVIGRÉS-Dados de sustentabilidade-Wall Covering - PotencialPrivacaoDeAguaConsumoDeAguaPonderado: 4.5; EnergiaTermicaExportada: 0; ItemENovo: Sim; ItemEParcialmenteReciclado: 0.23; ItemEReciclado: Sim; VidaÚtilEsperada: 50; SubstanciasPerigosas: Não; PotencialDeEsgotamentoAbioticoDosRecursosFosseis: 203; PotencialDeEsgotamentoAbioticoDosRecursosNaoFosseisMineraisEMetais: 0.000701; PotencialDeAquecimentoGlobalBiogenico: -0.48; CombustiveisFosseisComPotencialDeAquecimentoGlobal: 13.9; PotencialDeAquecimentoGlobalUsoDoSoloEMudancaDeUsoDoSolo: 0.0246; PotencialDeEutrofizacaoFraccaoDeNutrientesQueAtingemOCompartimentoFinalDeAguaDoce: 0.000189; PotencialDeEutrofizacaoFraccaoDeNutrientesQueAtingemOCompartimentoFinalMarinho: 0.0122; EnergiaRecuperada: 0.00739; ConsumoDeAguaDoce: 0.113; UtilizacaoLiquidaDeAguaDoce: 0.113; ResiduosPerigososEliminados: 0.00221; ResiduosNaoPerigososEliminados: 1.83; MassaTotalDeResiduosRadioactivosEliminados: 0.000394; EnergiaElectricaExportada: 1.55; MateriaisParaRecuperacaoDeEnergia: 0.00739; MateriaisParaReciclagem: 0.0253; UnidadeEPD: 1 m²
Type - IFC.REVIGRÉS-Dados gerais-Wall Covering - Nome: REVIGRÉS-LOCUS-BASE-29.5x29.5-SILK-QUILT GRIS; TipoProduto: Prensado a seco: grupo BIa UGL | Grés porcelânico técnico; NumeroDeRegistoDAP: EPD-REV-20240006-CCC1-EN; ReferenciaDAP: -; UrlDOP: -
Classification: C3010 (Uniformat)
Pset_WallCommon - ExtendToStructure: no; LoadBearing: no
IFC.REVIGRÉS-Dados do fabricante-Wall Covering - Type: Basic Wall: REVIGRÉS-LOCUS-BASE-29.5x29.5-SILK-QUILT GRIS
IFC.REVIGRÉS-Dados de desempenho-Wall Covering - Type: Basic Wall: REVIGRÉS-LOCUS-BASE-29.5x29.5-SILK-QUILT GRIS
IFC.REVIGRÉS-Dados de especificação-Wall Covering - Type: Basic Wall: REVIGRÉS-LOCUS-BASE-29.5x29.5-SILK-QUILT GRIS
IFC.REVIGRÉS-Dados geométricos-Wall Covering - Type: Basic Wall: REVIGRÉS-LOCUS-BASE-29.5x29.5-SILK-QUILT GRIS
IFC.REVIGRÉS-Dados de sustentabilidade-Wall Covering - Type: Basic Wall: REVIGRÉS-LOCUS-BASE-29.5x29.5-SILK-QUILT GRIS

# IfcWallStandardCase: Basic Wall:REVIGRÉS-LOCUS-BASE-29.5x29.5-SOFT GRIP-QUILT BONE, Basic Wall:REVIGRÉS-LOCUS-BASE-29.5x29.5-SOFT GRIP-QUILT BONE:40830
In: Level 1
Type - PredefinedType: STANDARD; Material: REVIGRÉS-LOCUS-BASE-30X30-SOFT GRIP-QUILT BONE 8.5 mm
Type - Pset_ElementShading - Roughness: 304.8 mm
Type - Pset_ManufacturerTypeInformation - Manufacturer: REVIGRÉS
Type - Pset_ProductRequirements - Category: Walls
Type - Pset_QuantityTakeOff - Reference: 312F12V641
Type - Pset_ReinforcementBarPitchOfWall - Description: Stone effect in wall and floor full body porcelain tile; Reference: 312F12V641
Type - Pset_WallCommon - IsExternal: no; Reference: 312F12V641
Type - IFC.REVIGRÉS-Dados do fabricante-Wall Covering - FabricanteURL: https://www.revigres.pt/; ReferenciaModelo: Locus; NumeroGlobalDeItemComercial: 312F12V641; Acabamento: SOFT; Material: Grés porcelânico; IdentificadorDoOperadorEconomico: 501840856; UrlFabricanteArtigo: https://www.revigres.pt/colecoes/locus; PaisOrigem: Portugal
Type - IFC.REVIGRÉS-Dados de desempenho-Wall Covering - Rectilinearidade: ± 0.2% máx ± 1.0 mm; Ortogonalidade: ± 0.2% máx.± 1.5 mm; PlanaridadeDaSuperficie: ± 0.3% máx. ± 1.8 mm; QualidadeDaSuperficie: Cumpre; AbsorcaoDeAgua: < 0.05%; ModuloDeRuptura: > 45 N/mm²; ResistenciaAFlexao: > 2000 N; ResistenciaAAbrasaoProfunda: < 120 mm³; DilatacaoTermicaLinear: ≤ 8,0x10-6 °C-1; ResistenciaAoChoqueTermico: Resiste; DurabilidadeInterior: Cumpre; DurabilidadeResistenciaAoGeloDegelo: Resiste; ResistenciaAoEscorregamentoDIN51130: R11; ResistenciaAoEscorregamentoDIN51097: A; ResistenciaAoEscorregamentoENV51097: A; ResistenciaAoEscorregamentoENV12633: Class 2; ResistenciaAoEscorregamentoBS7976: > 36; ResistenciaAoEscorregamentoANSIA1371: ≥0,42; ResistenciaAoDeslizamentoENV12633: Class 2; ResistenciaAoDeslizamentoBS7976: > 36; ResistenciaAsManchas: Class 5; LibertacaoDeCadmio: 0; LibertacaoDeChumbo: 0
Type - IFC.REVIGRÉS-Dados de especificação-Wall Covering - VariacaoTonalidade: 3; NivelDeTrafego: 5; EPavimento: Sim; ERevestimento: Sim; EExterno: Sim
Type - IFC.REVIGRÉS-Dados geométricos-Wall Covering - AlturaNominal: 8.5 mm; ComprimentoNominal: 29.5 mm; LarguraNominal: 29.5 mm
Type - IFC.REVIGRÉS-Dados de sustentabilidade-Wall Covering - ItemEParcialmenteReciclado: 0; PotencialPrivacaoDeAguaConsumoDeAguaPonderado: 4.5; EnergiaTermicaExportada: 0; ItemENovo: Sim; ItemEReciclado: Não; VidaÚtilEsperada: 50; SubstanciasPerigosas: Não; PotencialDeEsgotamentoAbioticoDosRecursosFosseis: 203; PotencialDeEsgotamentoAbioticoDosRecursosNaoFosseisMineraisEMetais: 0.000701; PotencialDeAquecimentoGlobalBiogenico: -0.48; CombustiveisFosseisComPotencialDeAquecimentoGlobal: 13.9; PotencialDeAquecimentoGlobalUsoDoSoloEMudancaDeUsoDoSolo: 0.0246; PotencialDeEutrofizacaoFraccaoDeNutrientesQueAtingemOCompartimentoFinalDeAguaDoce: 0.000189; PotencialDeEutrofizacaoFraccaoDeNutrientesQueAtingemOCompartimentoFinalMarinho: 0.0122; EnergiaRecuperada: 0.00739; ConsumoDeAguaDoce: 0.113; UtilizacaoLiquidaDeAguaDoce: 0.113; ResiduosPerigososEliminados: 0.00221; ResiduosNaoPerigososEliminados: 1.83; MassaTotalDeResiduosRadioactivosEliminados: 0.000394; EnergiaElectricaExportada: 1.55; MateriaisParaRecuperacaoDeEnergia: 0.00739; MateriaisParaReciclagem: 0.0253; UnidadeEPD: 1 m²
Type - IFC.REVIGRÉS-Dados gerais-Wall Covering - Nome: REVIGRÉS-LOCUS-BASE-29.5x29.5-SOFT GRIP-QUILT BONE; TipoProduto: Prensado a seco: grupo BIa UGL | Grés porcelânico técnico; NumeroDeRegistoDAP: EPD-REV-20240006-CCC1-EN; ReferenciaDAP: -; UrlDOP: -
Classification: C3010 (Uniformat)
Pset_WallCommon - ExtendToStructure: no; LoadBearing: no
IFC.REVIGRÉS-Dados do fabricante-Wall Covering - Type: Basic Wall: REVIGRÉS-LOCUS-BASE-29.5x29.5-SOFT GRIP-QUILT BONE
IFC.REVIGRÉS-Dados de desempenho-Wall Covering - Type: Basic Wall: REVIGRÉS-LOCUS-BASE-29.5x29.5-SOFT GRIP-QUILT BONE
IFC.REVIGRÉS-Dados de especificação-Wall Covering - Type: Basic Wall: REVIGRÉS-LOCUS-BASE-29.5x29.5-SOFT GRIP-QUILT BONE
IFC.REVIGRÉS-Dados geométricos-Wall Covering - Type: Basic Wall: REVIGRÉS-LOCUS-BASE-29.5x29.5-SOFT GRIP-QUILT BONE
IFC.REVIGRÉS-Dados de sustentabilidade-Wall Covering - Type: Basic Wall: REVIGRÉS-LOCUS-BASE-29.5x29.5-SOFT GRIP-QUILT BONE

# IfcWallStandardCase: Basic Wall:REVIGRÉS-LOCUS-BASE-29.5x29.5-SOFT GRIP-QUILT GREEN, Basic Wall:REVIGRÉS-LOCUS-BASE-29.5x29.5-SOFT GRIP-QUILT GREEN:40838
In: Level 1
Type - PredefinedType: STANDARD; Material: REVIGRÉS-LOCUS-BASE-30X30-SOFT GRIP-QUILT GREEN 8.5 mm
Type - Pset_ElementShading - Roughness: 304.8 mm
Type - Pset_ManufacturerTypeInformation - Manufacturer: REVIGRÉS
Type - Pset_ProductRequirements - Category: Walls
Type - Pset_QuantityTakeOff - Reference: 312F12V661
Type - Pset_ReinforcementBarPitchOfWall - Description: Stone effect in wall and floor full body porcelain tile; Reference: 312F12V661
Type - Pset_WallCommon - IsExternal: no; Reference: 312F12V661
Type - IFC.REVIGRÉS-Dados do fabricante-Wall Covering - FabricanteURL: https://www.revigres.pt/; ReferenciaModelo: Locus; NumeroGlobalDeItemComercial: 312F12V661; Acabamento: SOFT; Material: Grés porcelânico; IdentificadorDoOperadorEconomico: 501840856; UrlFabricanteArtigo: https://www.revigres.pt/colecoes/locus; PaisOrigem: Portugal
Type - IFC.REVIGRÉS-Dados de desempenho-Wall Covering - Rectilinearidade: ± 0.2% máx ± 1.0 mm; Ortogonalidade: ± 0.2% máx.± 1.5 mm; PlanaridadeDaSuperficie: ± 0.3% máx. ± 1.8 mm; QualidadeDaSuperficie: Cumpre; AbsorcaoDeAgua: < 0.05%; ModuloDeRuptura: > 45 N/mm²; ResistenciaAFlexao: > 2000 N; ResistenciaAAbrasaoProfunda: < 120 mm³; DilatacaoTermicaLinear: ≤ 8,0x10-6 °C-1; ResistenciaAoChoqueTermico: Resiste; DurabilidadeInterior: Cumpre; DurabilidadeResistenciaAoGeloDegelo: Resiste; ResistenciaAoEscorregamentoDIN51130: R11; ResistenciaAoEscorregamentoDIN51097: A; ResistenciaAoEscorregamentoENV51097: A; ResistenciaAoEscorregamentoENV12633: Class 2; ResistenciaAoEscorregamentoBS7976: > 36; ResistenciaAoEscorregamentoANSIA1371: ≥0,42; ResistenciaAoDeslizamentoENV12633: Class 2; ResistenciaAoDeslizamentoBS7976: > 36; ResistenciaAsManchas: Class 5; LibertacaoDeCadmio: 0; LibertacaoDeChumbo: 0
Type - IFC.REVIGRÉS-Dados de especificação-Wall Covering - VariacaoTonalidade: 3; NivelDeTrafego: 5; EPavimento: Sim; ERevestimento: Sim; EExterno: Sim
Type - IFC.REVIGRÉS-Dados geométricos-Wall Covering - AlturaNominal: 8.5 mm; ComprimentoNominal: 29.5 mm; LarguraNominal: 29.5 mm
Type - IFC.REVIGRÉS-Dados de sustentabilidade-Wall Covering - ItemEParcialmenteReciclado: 0; PotencialPrivacaoDeAguaConsumoDeAguaPonderado: 4.5; EnergiaTermicaExportada: 0; ItemENovo: Sim; ItemEReciclado: Não; VidaÚtilEsperada: 50; SubstanciasPerigosas: Não; PotencialDeEsgotamentoAbioticoDosRecursosFosseis: 203; PotencialDeEsgotamentoAbioticoDosRecursosNaoFosseisMineraisEMetais: 0.000701; PotencialDeAquecimentoGlobalBiogenico: -0.48; CombustiveisFosseisComPotencialDeAquecimentoGlobal: 13.9; PotencialDeAquecimentoGlobalUsoDoSoloEMudancaDeUsoDoSolo: 0.0246; PotencialDeEutrofizacaoFraccaoDeNutrientesQueAtingemOCompartimentoFinalDeAguaDoce: 0.000189; PotencialDeEutrofizacaoFraccaoDeNutrientesQueAtingemOCompartimentoFinalMarinho: 0.0122; EnergiaRecuperada: 0.00739; ConsumoDeAguaDoce: 0.113; UtilizacaoLiquidaDeAguaDoce: 0.113; ResiduosPerigososEliminados: 0.00221; ResiduosNaoPerigososEliminados: 1.83; MassaTotalDeResiduosRadioactivosEliminados: 0.000394; EnergiaElectricaExportada: 1.55; MateriaisParaRecuperacaoDeEnergia: 0.00739; MateriaisParaReciclagem: 0.0253; UnidadeEPD: 1 m²
Type - IFC.REVIGRÉS-Dados gerais-Wall Covering - Nome: REVIGRÉS-LOCUS-BASE-29.5x29.5-SOFT GRIP-QUILT GREEN; TipoProduto: Prensado a seco: grupo BIa UGL | Grés porcelânico técnico; NumeroDeRegistoDAP: EPD-REV-20240006-CCC1-EN; ReferenciaDAP: -; UrlDOP: -
Classification: C3010 (Uniformat)
Pset_WallCommon - ExtendToStructure: no; LoadBearing: no
IFC.REVIGRÉS-Dados do fabricante-Wall Covering - Type: Basic Wall: REVIGRÉS-LOCUS-BASE-29.5x29.5-SOFT GRIP-QUILT GREEN
IFC.REVIGRÉS-Dados de desempenho-Wall Covering - Type: Basic Wall: REVIGRÉS-LOCUS-BASE-29.5x29.5-SOFT GRIP-QUILT GREEN
IFC.REVIGRÉS-Dados de especificação-Wall Covering - Type: Basic Wall: REVIGRÉS-LOCUS-BASE-29.5x29.5-SOFT GRIP-QUILT GREEN
IFC.REVIGRÉS-Dados geométricos-Wall Covering - Type: Basic Wall: REVIGRÉS-LOCUS-BASE-29.5x29.5-SOFT GRIP-QUILT GREEN
IFC.REVIGRÉS-Dados de sustentabilidade-Wall Covering - Type: Basic Wall: REVIGRÉS-LOCUS-BASE-29.5x29.5-SOFT GRIP-QUILT GREEN

# IfcWallStandardCase: Basic Wall:REVIGRÉS-LOCUS-BASE-29.5x29.5-SOFT GRIP-QUILT GRIS, Basic Wall:REVIGRÉS-LOCUS-BASE-29.5x29.5-SOFT GRIP-QUILT GRIS:40846
In: Level 1
Type - PredefinedType: STANDARD; Material: REVIGRÉS-LOCUS-BASE-30X30-SOFT GRIP-QUILT GRIS 8.5 mm
Type - Pset_ElementShading - Roughness: 304.8 mm
Type - Pset_ManufacturerTypeInformation - Manufacturer: REVIGRÉS
Type - Pset_ProductRequirements - Category: Walls
Type - Pset_QuantityTakeOff - Reference: 312F12V651
Type - Pset_ReinforcementBarPitchOfWall - Description: Stone effect in wall and floor full body porcelain tile; Reference: 312F12V651
Type - Pset_WallCommon - IsExternal: no; Reference: 312F12V651
Type - IFC.REVIGRÉS-Dados do fabricante-Wall Covering - FabricanteURL: https://www.revigres.pt/; ReferenciaModelo: Locus; NumeroGlobalDeItemComercial: 312F12V651; Acabamento: SOFT; Material: Grés porcelânico; IdentificadorDoOperadorEconomico: 501840856; UrlFabricanteArtigo: https://www.revigres.pt/colecoes/locus; PaisOrigem: Portugal
Type - IFC.REVIGRÉS-Dados de desempenho-Wall Covering - Rectilinearidade: ± 0.2% máx ± 1.0 mm; Ortogonalidade: ± 0.2% máx.± 1.5 mm; PlanaridadeDaSuperficie: ± 0.3% máx. ± 1.8 mm; QualidadeDaSuperficie: Cumpre; AbsorcaoDeAgua: < 0.05%; ModuloDeRuptura: > 45 N/mm²; ResistenciaAFlexao: > 2000 N; ResistenciaAAbrasaoProfunda: < 120 mm³; DilatacaoTermicaLinear: ≤ 8,0x10-6 °C-1; ResistenciaAoChoqueTermico: Resiste; DurabilidadeInterior: Cumpre; DurabilidadeResistenciaAoGeloDegelo: Resiste; ResistenciaAoEscorregamentoDIN51130: R11; ResistenciaAoEscorregamentoDIN51097: A; ResistenciaAoEscorregamentoENV51097: A; ResistenciaAoEscorregamentoENV12633: Class 2; ResistenciaAoEscorregamentoBS7976: > 36; ResistenciaAoEscorregamentoANSIA1371: ≥0,42; ResistenciaAoDeslizamentoENV12633: Class 2; ResistenciaAoDeslizamentoBS7976: > 36; ResistenciaAsManchas: Class 5; LibertacaoDeCadmio: 0; LibertacaoDeChumbo: 0
Type - IFC.REVIGRÉS-Dados de especificação-Wall Covering - VariacaoTonalidade: 3; NivelDeTrafego: 5; EPavimento: Sim; ERevestimento: Sim; EExterno: Sim
Type - IFC.REVIGRÉS-Dados geométricos-Wall Covering - AlturaNominal: 8.5 mm; ComprimentoNominal: 29.5 mm; LarguraNominal: 29.5 mm
Type - IFC.REVIGRÉS-Dados de sustentabilidade-Wall Covering - PotencialPrivacaoDeAguaConsumoDeAguaPonderado: 4.5; EnergiaTermicaExportada: 0; ItemENovo: Sim; ItemEParcialmenteReciclado: 0.23; ItemEReciclado: Sim; VidaÚtilEsperada: 50; SubstanciasPerigosas: Não; PotencialDeEsgotamentoAbioticoDosRecursosFosseis: 203; PotencialDeEsgotamentoAbioticoDosRecursosNaoFosseisMineraisEMetais: 0.000701; PotencialDeAquecimentoGlobalBiogenico: -0.48; CombustiveisFosseisComPotencialDeAquecimentoGlobal: 13.9; PotencialDeAquecimentoGlobalUsoDoSoloEMudancaDeUsoDoSolo: 0.0246; PotencialDeEutrofizacaoFraccaoDeNutrientesQueAtingemOCompartimentoFinalDeAguaDoce: 0.000189; PotencialDeEutrofizacaoFraccaoDeNutrientesQueAtingemOCompartimentoFinalMarinho: 0.0122; EnergiaRecuperada: 0.00739; ConsumoDeAguaDoce: 0.113; UtilizacaoLiquidaDeAguaDoce: 0.113; ResiduosPerigososEliminados: 0.00221; ResiduosNaoPerigososEliminados: 1.83; MassaTotalDeResiduosRadioactivosEliminados: 0.000394; EnergiaElectricaExportada: 1.55; MateriaisParaRecuperacaoDeEnergia: 0.00739; MateriaisParaReciclagem: 0.0253; UnidadeEPD: 1 m²
Type - IFC.REVIGRÉS-Dados gerais-Wall Covering - Nome: REVIGRÉS-LOCUS-BASE-29.5x29.5-SOFT GRIP-QUILT GRIS; TipoProduto: Prensado a seco: grupo BIa UGL | Grés porcelânico técnico; NumeroDeRegistoDAP: EPD-REV-20240006-CCC1-EN; ReferenciaDAP: -; UrlDOP: -
Classification: C3010 (Uniformat)
Pset_WallCommon - ExtendToStructure: no; LoadBearing: no
IFC.REVIGRÉS-Dados do fabricante-Wall Covering - Type: Basic Wall: REVIGRÉS-LOCUS-BASE-29.5x29.5-SOFT GRIP-QUILT GRIS
IFC.REVIGRÉS-Dados de desempenho-Wall Covering - Type: Basic Wall: REVIGRÉS-LOCUS-BASE-29.5x29.5-SOFT GRIP-QUILT GRIS
IFC.REVIGRÉS-Dados de especificação-Wall Covering - Type: Basic Wall: REVIGRÉS-LOCUS-BASE-29.5x29.5-SOFT GRIP-QUILT GRIS
IFC.REVIGRÉS-Dados geométricos-Wall Covering - Type: Basic Wall: REVIGRÉS-LOCUS-BASE-29.5x29.5-SOFT GRIP-QUILT GRIS
IFC.REVIGRÉS-Dados de sustentabilidade-Wall Covering - Type: Basic Wall: REVIGRÉS-LOCUS-BASE-29.5x29.5-SOFT GRIP-QUILT GRIS

# IfcWallStandardCase: Basic Wall:REVIGRÉS-LOCUS-BASE-29.5x59.2-SILK-ALLOY, Basic Wall:REVIGRÉS-LOCUS-BASE-29.5x59.2-SILK-ALLOY:36059
In: Level 1
Type - PredefinedType: STANDARD; Material: REVIGRÉS-LOCUS-BASE-30x60-SILK-ALLOY 8.5 mm
Type - Pset_ElementShading - Roughness: 304.8 mm
Type - Pset_ManufacturerTypeInformation - Manufacturer: REVIGRÉS
Type - Pset_ProductRequirements - Category: Walls
Type - Pset_QuantityTakeOff - Reference: 312G21V671
Type - Pset_ReinforcementBarPitchOfWall - Description: Stone effect in wall and floor full body porcelain tile; Reference: 312G21V671
Type - Pset_WallCommon - IsExternal: no; Reference: 312G21V671
Type - IFC.REVIGRÉS-Dados do fabricante-Wall Covering - FabricanteURL: https://www.revigres.pt/; ReferenciaModelo: Locus; NumeroGlobalDeItemComercial: 312G21V671; Acabamento: SILK; Material: Grés porcelânico; IdentificadorDoOperadorEconomico: 501840856; UrlFabricanteArtigo: https://www.revigres.pt/colecoes/locus; PaisOrigem: Portugal
Type - IFC.REVIGRÉS-Dados de desempenho-Wall Covering - Rectilinearidade: ± 0.2% máx.± 0.8 mm; Ortogonalidade: ± 0.2% máx.± 1.5 mm; PlanaridadeDaSuperficie: ± 0.3% máx. ± 1.8 mm; QualidadeDaSuperficie: Cumpre; AbsorcaoDeAgua: < 0.05%; ModuloDeRuptura: > 45 N/mm²; ResistenciaAFlexao: > 2000 N; ResistenciaAAbrasaoProfunda: < 120 mm³; DilatacaoTermicaLinear: ≤ 8,0x10-6 °C-1; ResistenciaAoChoqueTermico: Resiste; DurabilidadeInterior: Cumpre; DurabilidadeResistenciaAoGeloDegelo: Resiste; ResistenciaAoEscorregamentoDIN51130: R9; ResistenciaAoEscorregamentoDIN51097: A; ResistenciaAoEscorregamentoENV51097: A; ResistenciaAoEscorregamentoENV12633: Class 1; ResistenciaAoEscorregamentoBS7976: -; ResistenciaAoEscorregamentoANSIA1371: ≥0,42; ResistenciaAoDeslizamentoENV12633: Class 1; ResistenciaAoDeslizamentoBS7976: -; ResistenciaAsManchas: Class 5; LibertacaoDeCadmio: 0; LibertacaoDeChumbo: 0
Type - IFC.REVIGRÉS-Dados de especificação-Wall Covering - VariacaoTonalidade: 3; NivelDeTrafego: 5; EPavimento: Sim; ERevestimento: Sim; EExterno: Sim
Type - IFC.REVIGRÉS-Dados geométricos-Wall Covering - AlturaNominal: 8.5 mm; ComprimentoNominal: 29.5 mm; LarguraNominal: 59.2 mm
Type - IFC.REVIGRÉS-Dados de sustentabilidade-Wall Covering - ItemEParcialmenteReciclado: 0; PotencialPrivacaoDeAguaConsumoDeAguaPonderado: 4.5; EnergiaTermicaExportada: 0; ItemENovo: Sim; ItemEReciclado: Não; VidaÚtilEsperada: 50; SubstanciasPerigosas: Não; PotencialDeEsgotamentoAbioticoDosRecursosFosseis: 203; PotencialDeEsgotamentoAbioticoDosRecursosNaoFosseisMineraisEMetais: 0.000701; PotencialDeAquecimentoGlobalBiogenico: -0.48; CombustiveisFosseisComPotencialDeAquecimentoGlobal: 13.9; PotencialDeAquecimentoGlobalUsoDoSoloEMudancaDeUsoDoSolo: 0.0246; PotencialDeEutrofizacaoFraccaoDeNutrientesQueAtingemOCompartimentoFinalDeAguaDoce: 0.000189; PotencialDeEutrofizacaoFraccaoDeNutrientesQueAtingemOCompartimentoFinalMarinho: 0.0122; EnergiaRecuperada: 0.00739; ConsumoDeAguaDoce: 0.113; UtilizacaoLiquidaDeAguaDoce: 0.113; ResiduosPerigososEliminados: 0.00221; ResiduosNaoPerigososEliminados: 1.83; MassaTotalDeResiduosRadioactivosEliminados: 0.000394; EnergiaElectricaExportada: 1.55; MateriaisParaRecuperacaoDeEnergia: 0.00739; MateriaisParaReciclagem: 0.0253; UnidadeEPD: 1 m²
Type - IFC.REVIGRÉS-Dados gerais-Wall Covering - Nome: REVIGRÉS-LOCUS-BASE-29.5x59.2-SILK-ALLOY; TipoProduto: Prensado a seco: grupo BIa UGL | Grés porcelânico técnico; NumeroDeRegistoDAP: EPD-REV-20240006-CCC1-EN; ReferenciaDAP: -; UrlDOP: -
Classification: C3010 (Uniformat)
Pset_WallCommon - ExtendToStructure: no; LoadBearing: no
IFC.REVIGRÉS-Dados do fabricante-Wall Covering - Type: Basic Wall: REVIGRÉS-LOCUS-BASE-29.5x59.2-SILK-ALLOY
IFC.REVIGRÉS-Dados de desempenho-Wall Covering - Type: Basic Wall: REVIGRÉS-LOCUS-BASE-29.5x59.2-SILK-ALLOY
IFC.REVIGRÉS-Dados de especificação-Wall Covering - Type: Basic Wall: REVIGRÉS-LOCUS-BASE-29.5x59.2-SILK-ALLOY
IFC.REVIGRÉS-Dados geométricos-Wall Covering - Type: Basic Wall: REVIGRÉS-LOCUS-BASE-29.5x59.2-SILK-ALLOY
IFC.REVIGRÉS-Dados de sustentabilidade-Wall Covering - Type: Basic Wall: REVIGRÉS-LOCUS-BASE-29.5x59.2-SILK-ALLOY

# IfcWallStandardCase: Basic Wall:REVIGRÉS-LOCUS-BASE-29.5x59.2-SILK-BONE, Basic Wall:REVIGRÉS-LOCUS-BASE-29.5x59.2-SILK-BONE:36640
In: Level 1
Type - PredefinedType: STANDARD; Material: REVIGRÉS-LOCUS-BASE-30x60-SILK-BONE 8.5 mm
Type - Pset_ElementShading - Roughness: 304.8 mm
Type - Pset_ManufacturerTypeInformation - Manufacturer: REVIGRÉS
Type - Pset_ProductRequirements - Category: Walls
Type - Pset_QuantityTakeOff - Reference: 312G21V681
Type - Pset_ReinforcementBarPitchOfWall - Description: Stone effect in wall and floor full body porcelain tile; Reference: 312G21V681
Type - Pset_WallCommon - IsExternal: no; Reference: 312G21V681
Type - IFC.REVIGRÉS-Dados do fabricante-Wall Covering - FabricanteURL: https://www.revigres.pt/; ReferenciaModelo: Locus; NumeroGlobalDeItemComercial: 312G21V681; Acabamento: SILK; Material: Grés porcelânico; IdentificadorDoOperadorEconomico: 501840856; UrlFabricanteArtigo: https://www.revigres.pt/colecoes/locus; PaisOrigem: Portugal
Type - IFC.REVIGRÉS-Dados de desempenho-Wall Covering - Rectilinearidade: ± 0.2% máx.± 0.8 mm; Ortogonalidade: ± 0.2% máx.± 1.5 mm; PlanaridadeDaSuperficie: ± 0.3% máx. ± 1.8 mm; QualidadeDaSuperficie: Cumpre; AbsorcaoDeAgua: < 0.05%; ModuloDeRuptura: > 45 N/mm²; ResistenciaAFlexao: > 2000 N; ResistenciaAAbrasaoProfunda: < 120 mm³; DilatacaoTermicaLinear: ≤ 8,0x10-6 °C-1; ResistenciaAoChoqueTermico: Resiste; DurabilidadeInterior: Cumpre; DurabilidadeResistenciaAoGeloDegelo: Resiste; ResistenciaAoEscorregamentoDIN51130: R9; ResistenciaAoEscorregamentoDIN51097: A; ResistenciaAoEscorregamentoENV51097: A; ResistenciaAoEscorregamentoENV12633: Class 1; ResistenciaAoEscorregamentoBS7976: -; ResistenciaAoEscorregamentoANSIA1371: ≥0,42; ResistenciaAoDeslizamentoENV12633: Class 1; ResistenciaAoDeslizamentoBS7976: -; ResistenciaAsManchas: Class 5; LibertacaoDeCadmio: 0; LibertacaoDeChumbo: 0
Type - IFC.REVIGRÉS-Dados de especificação-Wall Covering - VariacaoTonalidade: 3; NivelDeTrafego: 5; EPavimento: Sim; ERevestimento: Sim; EExterno: Sim
Type - IFC.REVIGRÉS-Dados geométricos-Wall Covering - AlturaNominal: 8.5 mm; ComprimentoNominal: 29.5 mm; LarguraNominal: 59.2 mm
Type - IFC.REVIGRÉS-Dados de sustentabilidade-Wall Covering - ItemEParcialmenteReciclado: 0; PotencialPrivacaoDeAguaConsumoDeAguaPonderado: 4.5; EnergiaTermicaExportada: 0; ItemENovo: Sim; ItemEReciclado: Não; VidaÚtilEsperada: 50; SubstanciasPerigosas: Não; PotencialDeEsgotamentoAbioticoDosRecursosFosseis: 203; PotencialDeEsgotamentoAbioticoDosRecursosNaoFosseisMineraisEMetais: 0.000701; PotencialDeAquecimentoGlobalBiogenico: -0.48; CombustiveisFosseisComPotencialDeAquecimentoGlobal: 13.9; PotencialDeAquecimentoGlobalUsoDoSoloEMudancaDeUsoDoSolo: 0.0246; PotencialDeEutrofizacaoFraccaoDeNutrientesQueAtingemOCompartimentoFinalDeAguaDoce: 0.000189; PotencialDeEutrofizacaoFraccaoDeNutrientesQueAtingemOCompartimentoFinalMarinho: 0.0122; EnergiaRecuperada: 0.00739; ConsumoDeAguaDoce: 0.113; UtilizacaoLiquidaDeAguaDoce: 0.113; ResiduosPerigososEliminados: 0.00221; ResiduosNaoPerigososEliminados: 1.83; MassaTotalDeResiduosRadioactivosEliminados: 0.000394; EnergiaElectricaExportada: 1.55; MateriaisParaRecuperacaoDeEnergia: 0.00739; MateriaisParaReciclagem: 0.0253; UnidadeEPD: 1 m²
Type - IFC.REVIGRÉS-Dados gerais-Wall Covering - Nome: REVIGRÉS-LOCUS-BASE-29.5x59.2-SILK-BONE; TipoProduto: Prensado a seco: grupo BIa UGL | Grés porcelânico técnico; NumeroDeRegistoDAP: EPD-REV-20240006-CCC1-EN; ReferenciaDAP: -; UrlDOP: -
Classification: C3010 (Uniformat)
Pset_WallCommon - ExtendToStructure: no; LoadBearing: no
IFC.REVIGRÉS-Dados do fabricante-Wall Covering - Type: Basic Wall: REVIGRÉS-LOCUS-BASE-29.5x59.2-SILK-BONE
IFC.REVIGRÉS-Dados de desempenho-Wall Covering - Type: Basic Wall: REVIGRÉS-LOCUS-BASE-29.5x59.2-SILK-BONE
IFC.REVIGRÉS-Dados de especificação-Wall Covering - Type: Basic Wall: REVIGRÉS-LOCUS-BASE-29.5x59.2-SILK-BONE
IFC.REVIGRÉS-Dados geométricos-Wall Covering - Type: Basic Wall: REVIGRÉS-LOCUS-BASE-29.5x59.2-SILK-BONE
IFC.REVIGRÉS-Dados de sustentabilidade-Wall Covering - Type: Basic Wall: REVIGRÉS-LOCUS-BASE-29.5x59.2-SILK-BONE

# IfcWallStandardCase: Basic Wall:REVIGRÉS-LOCUS-BASE-29.5x59.2-SILK-GRIS, Basic Wall:REVIGRÉS-LOCUS-BASE-29.5x59.2-SILK-GRIS:37313
In: Level 1
Type - PredefinedType: STANDARD; Material: REVIGRÉS-LOCUS-BASE-30x60-SILK-GRIS 8.5 mm
Type - Pset_ElementShading - Roughness: 304.8 mm
Type - Pset_ManufacturerTypeInformation - Manufacturer: REVIGRÉS
Type - Pset_ProductRequirements - Category: Walls
Type - Pset_QuantityTakeOff - Reference: 312G21V691
Type - Pset_ReinforcementBarPitchOfWall - Description: Stone effect in wall and floor full body porcelain tile; Reference: 312G21V691
Type - Pset_WallCommon - IsExternal: no; Reference: 312G21V691
Type - IFC.REVIGRÉS-Dados do fabricante-Wall Covering - FabricanteURL: https://www.revigres.pt/; ReferenciaModelo: Locus; NumeroGlobalDeItemComercial: 312G21V691; Acabamento: SILK; Material: Grés porcelânico; IdentificadorDoOperadorEconomico: 501840856; UrlFabricanteArtigo: https://www.revigres.pt/colecoes/locus; PaisOrigem: Portugal
Type - IFC.REVIGRÉS-Dados de desempenho-Wall Covering - Rectilinearidade: ± 0.2% máx.± 0.8 mm; Ortogonalidade: ± 0.2% máx.± 1.5 mm; PlanaridadeDaSuperficie: ± 0.3% máx. ± 1.8 mm; QualidadeDaSuperficie: Cumpre; AbsorcaoDeAgua: < 0.05%; ModuloDeRuptura: > 45 N/mm²; ResistenciaAFlexao: > 2000 N; ResistenciaAAbrasaoProfunda: < 120 mm³; DilatacaoTermicaLinear: ≤ 8,0x10-6 °C-1; ResistenciaAoChoqueTermico: Resiste; DurabilidadeInterior: Cumpre; DurabilidadeResistenciaAoGeloDegelo: Resiste; ResistenciaAoEscorregamentoDIN51130: R9; ResistenciaAoEscorregamentoDIN51097: A; ResistenciaAoEscorregamentoENV51097: A; ResistenciaAoEscorregamentoENV12633: Class 1; ResistenciaAoEscorregamentoBS7976: -; ResistenciaAoEscorregamentoANSIA1371: ≥0,42; ResistenciaAoDeslizamentoENV12633: Class 1; ResistenciaAoDeslizamentoBS7976: -; ResistenciaAsManchas: Class 5; LibertacaoDeCadmio: 0; LibertacaoDeChumbo: 0
Type - IFC.REVIGRÉS-Dados de especificação-Wall Covering - VariacaoTonalidade: 3; NivelDeTrafego: 5; EPavimento: Sim; ERevestimento: Sim; EExterno: Sim
Type - IFC.REVIGRÉS-Dados geométricos-Wall Covering - AlturaNominal: 8.5 mm; ComprimentoNominal: 29.5 mm; LarguraNominal: 59.2 mm
Type - IFC.REVIGRÉS-Dados de sustentabilidade-Wall Covering - PotencialPrivacaoDeAguaConsumoDeAguaPonderado: 4.5; EnergiaTermicaExportada: 0; ItemENovo: Sim; ItemEParcialmenteReciclado: 0.23; ItemEReciclado: Sim; VidaÚtilEsperada: 50; SubstanciasPerigosas: Não; PotencialDeEsgotamentoAbioticoDosRecursosFosseis: 203; PotencialDeEsgotamentoAbioticoDosRecursosNaoFosseisMineraisEMetais: 0.000701; PotencialDeAquecimentoGlobalBiogenico: -0.48; CombustiveisFosseisComPotencialDeAquecimentoGlobal: 13.9; PotencialDeAquecimentoGlobalUsoDoSoloEMudancaDeUsoDoSolo: 0.0246; PotencialDeEutrofizacaoFraccaoDeNutrientesQueAtingemOCompartimentoFinalDeAguaDoce: 0.000189; PotencialDeEutrofizacaoFraccaoDeNutrientesQueAtingemOCompartimentoFinalMarinho: 0.0122; EnergiaRecuperada: 0.00739; ConsumoDeAguaDoce: 0.113; UtilizacaoLiquidaDeAguaDoce: 0.113; ResiduosPerigososEliminados: 0.00221; ResiduosNaoPerigososEliminados: 1.83; MassaTotalDeResiduosRadioactivosEliminados: 0.000394; EnergiaElectricaExportada: 1.55; MateriaisParaRecuperacaoDeEnergia: 0.00739; MateriaisParaReciclagem: 0.0253; UnidadeEPD: 1 m²
Type - IFC.REVIGRÉS-Dados gerais-Wall Covering - Nome: REVIGRÉS-LOCUS-BASE-29.5x59.2-SILK-GRIS; TipoProduto: Prensado a seco: grupo BIa UGL | Grés porcelânico técnico; NumeroDeRegistoDAP: EPD-REV-20240006-CCC1-EN; ReferenciaDAP: -; UrlDOP: -
Classification: C3010 (Uniformat)
Pset_WallCommon - ExtendToStructure: no; LoadBearing: no
IFC.REVIGRÉS-Dados do fabricante-Wall Covering - Type: Basic Wall: REVIGRÉS-LOCUS-BASE-29.5x59.2-SILK-GRIS
IFC.REVIGRÉS-Dados de desempenho-Wall Covering - Type: Basic Wall: REVIGRÉS-LOCUS-BASE-29.5x59.2-SILK-GRIS
IFC.REVIGRÉS-Dados de especificação-Wall Covering - Type: Basic Wall: REVIGRÉS-LOCUS-BASE-29.5x59.2-SILK-GRIS
IFC.REVIGRÉS-Dados geométricos-Wall Covering - Type: Basic Wall: REVIGRÉS-LOCUS-BASE-29.5x59.2-SILK-GRIS
IFC.REVIGRÉS-Dados de sustentabilidade-Wall Covering - Type: Basic Wall: REVIGRÉS-LOCUS-BASE-29.5x59.2-SILK-GRIS

# IfcWallStandardCase: Basic Wall:REVIGRÉS-LOCUS-BASE-29.5x59.2-SILK-SMOG, Basic Wall:REVIGRÉS-LOCUS-BASE-29.5x59.2-SILK-SMOG:37828
In: Level 1
Type - PredefinedType: STANDARD; Material: REVIGRÉS-LOCUS-BASE-30x60-SILK-SMOG 8.5 mm
Type - Pset_ElementShading - Roughness: 304.8 mm
Type - Pset_ManufacturerTypeInformation - Manufacturer: REVIGRÉS
Type - Pset_ProductRequirements - Category: Walls
Type - Pset_QuantityTakeOff - Reference: 312G21V701
Type - Pset_ReinforcementBarPitchOfWall - Description: Stone effect in wall and floor full body porcelain tile; Reference: 312G21V701
Type - Pset_WallCommon - IsExternal: no; Reference: 312G21V701
Type - IFC.REVIGRÉS-Dados do fabricante-Wall Covering - FabricanteURL: https://www.revigres.pt/; ReferenciaModelo: Locus; NumeroGlobalDeItemComercial: 312G21V701; Acabamento: SILK; Material: Grés porcelânico; IdentificadorDoOperadorEconomico: 501840856; UrlFabricanteArtigo: https://www.revigres.pt/colecoes/locus; PaisOrigem: Portugal
Type - IFC.REVIGRÉS-Dados de desempenho-Wall Covering - Rectilinearidade: ± 0.2% máx.± 0.8 mm; Ortogonalidade: ± 0.2% máx.± 1.5 mm; PlanaridadeDaSuperficie: ± 0.3% máx. ± 1.8 mm; QualidadeDaSuperficie: Cumpre; AbsorcaoDeAgua: < 0.05%; ModuloDeRuptura: > 45 N/mm²; ResistenciaAFlexao: > 2000 N; ResistenciaAAbrasaoProfunda: < 120 mm³; DilatacaoTermicaLinear: ≤ 8,0x10-6 °C-1; ResistenciaAoChoqueTermico: Resiste; DurabilidadeInterior: Cumpre; DurabilidadeResistenciaAoGeloDegelo: Resiste; ResistenciaAoEscorregamentoDIN51130: R9; ResistenciaAoEscorregamentoDIN51097: A; ResistenciaAoEscorregamentoENV51097: A; ResistenciaAoEscorregamentoENV12633: Class 1; ResistenciaAoEscorregamentoBS7976: -; ResistenciaAoEscorregamentoANSIA1371: ≥0,42; ResistenciaAoDeslizamentoENV12633: Class 1; ResistenciaAoDeslizamentoBS7976: -; ResistenciaAsManchas: Class 5; LibertacaoDeCadmio: 0; LibertacaoDeChumbo: 0
Type - IFC.REVIGRÉS-Dados de especificação-Wall Covering - VariacaoTonalidade: 3; NivelDeTrafego: 5; EPavimento: Sim; ERevestimento: Sim; EExterno: Sim
Type - IFC.REVIGRÉS-Dados geométricos-Wall Covering - AlturaNominal: 8.5 mm; ComprimentoNominal: 29.5 mm; LarguraNominal: 59.2 mm
Type - IFC.REVIGRÉS-Dados de sustentabilidade-Wall Covering - PotencialPrivacaoDeAguaConsumoDeAguaPonderado: 4.5; EnergiaTermicaExportada: 0; ItemENovo: Sim; ItemEParcialmenteReciclado: 0.29; ItemEReciclado: Sim; VidaÚtilEsperada: 50; SubstanciasPerigosas: Não; PotencialDeEsgotamentoAbioticoDosRecursosFosseis: 203; PotencialDeEsgotamentoAbioticoDosRecursosNaoFosseisMineraisEMetais: 0.000701; PotencialDeAquecimentoGlobalBiogenico: -0.48; CombustiveisFosseisComPotencialDeAquecimentoGlobal: 13.9; PotencialDeAquecimentoGlobalUsoDoSoloEMudancaDeUsoDoSolo: 0.0246; PotencialDeEutrofizacaoFraccaoDeNutrientesQueAtingemOCompartimentoFinalDeAguaDoce: 0.000189; PotencialDeEutrofizacaoFraccaoDeNutrientesQueAtingemOCompartimentoFinalMarinho: 0.0122; EnergiaRecuperada: 0.00739; ConsumoDeAguaDoce: 0.113; UtilizacaoLiquidaDeAguaDoce: 0.113; ResiduosPerigososEliminados: 0.00221; ResiduosNaoPerigososEliminados: 1.83; MassaTotalDeResiduosRadioactivosEliminados: 0.000394; EnergiaElectricaExportada: 1.55; MateriaisParaRecuperacaoDeEnergia: 0.00739; MateriaisParaReciclagem: 0.0253; UnidadeEPD: 1 m²
Type - IFC.REVIGRÉS-Dados gerais-Wall Covering - Nome: REVIGRÉS-LOCUS-BASE-29.5x59.2-SILK-SMOG; TipoProduto: Prensado a seco: grupo BIa UGL | Grés porcelânico técnico; NumeroDeRegistoDAP: EPD-REV-20240006-CCC1-EN; ReferenciaDAP: -; UrlDOP: -
Classification: C3010 (Uniformat)
Pset_WallCommon - ExtendToStructure: no; LoadBearing: no
IFC.REVIGRÉS-Dados do fabricante-Wall Covering - Type: Basic Wall: REVIGRÉS-LOCUS-BASE-29.5x59.2-SILK-SMOG
IFC.REVIGRÉS-Dados de desempenho-Wall Covering - Type: Basic Wall: REVIGRÉS-LOCUS-BASE-29.5x59.2-SILK-SMOG
IFC.REVIGRÉS-Dados de especificação-Wall Covering - Type: Basic Wall: REVIGRÉS-LOCUS-BASE-29.5x59.2-SILK-SMOG
IFC.REVIGRÉS-Dados geométricos-Wall Covering - Type: Basic Wall: REVIGRÉS-LOCUS-BASE-29.5x59.2-SILK-SMOG
IFC.REVIGRÉS-Dados de sustentabilidade-Wall Covering - Type: Basic Wall: REVIGRÉS-LOCUS-BASE-29.5x59.2-SILK-SMOG

# IfcWallStandardCase: Basic Wall:REVIGRÉS-LOCUS-BASE-29.5x59.2-SOFT GRIP-ALLOY, Basic Wall:REVIGRÉS-LOCUS-BASE-29.5x59.2-SOFT GRIP-ALLOY:36067
In: Level 1
Type - PredefinedType: STANDARD; Material: REVIGRÉS-LOCUS-BASE-30x60-SOFT GRIP-ALLOY 8.5 mm
Type - Pset_ElementShading - Roughness: 304.8 mm
Type - Pset_ManufacturerTypeInformation - Manufacturer: REVIGRÉS
Type - Pset_ProductRequirements - Category: Walls
Type - Pset_QuantityTakeOff - Reference: 312F21V671
Type - Pset_ReinforcementBarPitchOfWall - Description: Stone effect in wall and floor full body porcelain tile; Reference: 312F21V671
Type - Pset_WallCommon - IsExternal: no; Reference: 312F21V671
Type - IFC.REVIGRÉS-Dados do fabricante-Wall Covering - FabricanteURL: https://www.revigres.pt/; ReferenciaModelo: Locus; NumeroGlobalDeItemComercial: 312F21V671; Acabamento: SOFT; Material: Grés porcelânico; IdentificadorDoOperadorEconomico: 501840856; UrlFabricanteArtigo: https://www.revigres.pt/colecoes/locus; PaisOrigem: Portugal
Type - IFC.REVIGRÉS-Dados de desempenho-Wall Covering - Rectilinearidade: ± 0.2% máx ± 1.0 mm; Ortogonalidade: ± 0.2% máx.± 1.5 mm; PlanaridadeDaSuperficie: ± 0.3% máx. ± 1.8 mm; QualidadeDaSuperficie: Cumpre; AbsorcaoDeAgua: < 0.05%; ModuloDeRuptura: > 45 N/mm²; ResistenciaAFlexao: > 2000 N; ResistenciaAAbrasaoProfunda: < 120 mm³; DilatacaoTermicaLinear: ≤ 8,0x10-6 °C-1; ResistenciaAoChoqueTermico: Resiste; DurabilidadeInterior: Cumpre; DurabilidadeResistenciaAoGeloDegelo: Resiste; ResistenciaAoEscorregamentoDIN51130: R11; ResistenciaAoEscorregamentoDIN51097: A; ResistenciaAoEscorregamentoENV51097: A; ResistenciaAoEscorregamentoENV12633: Class 2; ResistenciaAoEscorregamentoBS7976: > 36; ResistenciaAoEscorregamentoANSIA1371: ≥0,42; ResistenciaAoDeslizamentoENV12633: Class 2; ResistenciaAoDeslizamentoBS7976: > 36; ResistenciaAsManchas: Class 5; LibertacaoDeCadmio: 0; LibertacaoDeChumbo: 0
Type - IFC.REVIGRÉS-Dados de especificação-Wall Covering - VariacaoTonalidade: 3; NivelDeTrafego: 5; EPavimento: Sim; ERevestimento: Sim; EExterno: Sim
Type - IFC.REVIGRÉS-Dados geométricos-Wall Covering - AlturaNominal: 8.5 mm; ComprimentoNominal: 29.5 mm; LarguraNominal: 59.2 mm
Type - IFC.REVIGRÉS-Dados de sustentabilidade-Wall Covering - ItemEParcialmenteReciclado: 0; PotencialPrivacaoDeAguaConsumoDeAguaPonderado: 4.5; EnergiaTermicaExportada: 0; ItemENovo: Sim; ItemEReciclado: Não; VidaÚtilEsperada: 50; SubstanciasPerigosas: Não; PotencialDeEsgotamentoAbioticoDosRecursosFosseis: 203; PotencialDeEsgotamentoAbioticoDosRecursosNaoFosseisMineraisEMetais: 0.000701; PotencialDeAquecimentoGlobalBiogenico: -0.48; CombustiveisFosseisComPotencialDeAquecimentoGlobal: 13.9; PotencialDeAquecimentoGlobalUsoDoSoloEMudancaDeUsoDoSolo: 0.0246; PotencialDeEutrofizacaoFraccaoDeNutrientesQueAtingemOCompartimentoFinalDeAguaDoce: 0.000189; PotencialDeEutrofizacaoFraccaoDeNutrientesQueAtingemOCompartimentoFinalMarinho: 0.0122; EnergiaRecuperada: 0.00739; ConsumoDeAguaDoce: 0.113; UtilizacaoLiquidaDeAguaDoce: 0.113; ResiduosPerigososEliminados: 0.00221; ResiduosNaoPerigososEliminados: 1.83; MassaTotalDeResiduosRadioactivosEliminados: 0.000394; EnergiaElectricaExportada: 1.55; MateriaisParaRecuperacaoDeEnergia: 0.00739; MateriaisParaReciclagem: 0.0253; UnidadeEPD: 1 m²
Type - IFC.REVIGRÉS-Dados gerais-Wall Covering - Nome: REVIGRÉS-LOCUS-BASE-29.5x59.2-SOFT GRIP-ALLOY; TipoProduto: Prensado a seco: grupo BIa UGL | Grés porcelânico técnico; NumeroDeRegistoDAP: EPD-REV-20240006-CCC1-EN; ReferenciaDAP: -; UrlDOP: -
Classification: C3010 (Uniformat)
Pset_WallCommon - ExtendToStructure: no; LoadBearing: no
IFC.REVIGRÉS-Dados do fabricante-Wall Covering - Type: Basic Wall: REVIGRÉS-LOCUS-BASE-29.5x59.2-SOFT GRIP-ALLOY
IFC.REVIGRÉS-Dados de desempenho-Wall Covering - Type: Basic Wall: REVIGRÉS-LOCUS-BASE-29.5x59.2-SOFT GRIP-ALLOY
IFC.REVIGRÉS-Dados de especificação-Wall Covering - Type: Basic Wall: REVIGRÉS-LOCUS-BASE-29.5x59.2-SOFT GRIP-ALLOY
IFC.REVIGRÉS-Dados geométricos-Wall Covering - Type: Basic Wall: REVIGRÉS-LOCUS-BASE-29.5x59.2-SOFT GRIP-ALLOY
IFC.REVIGRÉS-Dados de sustentabilidade-Wall Covering - Type: Basic Wall: REVIGRÉS-LOCUS-BASE-29.5x59.2-SOFT GRIP-ALLOY

# IfcWallStandardCase: Basic Wall:REVIGRÉS-LOCUS-BASE-29.5x59.2-SOFT GRIP-BONE, Basic Wall:REVIGRÉS-LOCUS-BASE-29.5x59.2-SOFT GRIP-BONE:36648
In: Level 1
Type - PredefinedType: STANDARD; Material: REVIGRÉS-LOCUS-BASE-30x60-SOFT GRIP-BONE 8.5 mm
Type - Pset_ElementShading - Roughness: 304.8 mm
Type - Pset_ManufacturerTypeInformation - Manufacturer: REVIGRÉS
Type - Pset_ProductRequirements - Category: Walls
Type - Pset_QuantityTakeOff - Reference: 312F21V681
Type - Pset_ReinforcementBarPitchOfWall - Description: Stone effect in wall and floor full body porcelain tile; Reference: 312F21V681
Type - Pset_WallCommon - IsExternal: no; Reference: 312F21V681
Type - IFC.REVIGRÉS-Dados do fabricante-Wall Covering - FabricanteURL: https://www.revigres.pt/; ReferenciaModelo: Locus; NumeroGlobalDeItemComercial: 312F21V681; Acabamento: SOFT; Material: Grés porcelânico; IdentificadorDoOperadorEconomico: 501840856; UrlFabricanteArtigo: https://www.revigres.pt/colecoes/locus; PaisOrigem: Portugal
Type - IFC.REVIGRÉS-Dados de desempenho-Wall Covering - Rectilinearidade: ± 0.2% máx ± 1.0 mm; Ortogonalidade: ± 0.2% máx.± 1.5 mm; PlanaridadeDaSuperficie: ± 0.3% máx. ± 1.8 mm; QualidadeDaSuperficie: Cumpre; AbsorcaoDeAgua: < 0.05%; ModuloDeRuptura: > 45 N/mm²; ResistenciaAFlexao: > 2000 N; ResistenciaAAbrasaoProfunda: < 120 mm³; DilatacaoTermicaLinear: ≤ 8,0x10-6 °C-1; ResistenciaAoChoqueTermico: Resiste; DurabilidadeInterior: Cumpre; DurabilidadeResistenciaAoGeloDegelo: Resiste; ResistenciaAoEscorregamentoDIN51130: R11; ResistenciaAoEscorregamentoDIN51097: A; ResistenciaAoEscorregamentoENV51097: A; ResistenciaAoEscorregamentoENV12633: Class 2; ResistenciaAoEscorregamentoBS7976: > 36; ResistenciaAoEscorregamentoANSIA1371: ≥0,42; ResistenciaAoDeslizamentoENV12633: Class 2; ResistenciaAoDeslizamentoBS7976: > 36; ResistenciaAsManchas: Class 5; LibertacaoDeCadmio: 0; LibertacaoDeChumbo: 0
Type - IFC.REVIGRÉS-Dados de especificação-Wall Covering - VariacaoTonalidade: 3; NivelDeTrafego: 5; EPavimento: Sim; ERevestimento: Sim; EExterno: Sim
Type - IFC.REVIGRÉS-Dados geométricos-Wall Covering - AlturaNominal: 8.5 mm; ComprimentoNominal: 29.5 mm; LarguraNominal: 59.2 mm
Type - IFC.REVIGRÉS-Dados de sustentabilidade-Wall Covering - ItemEParcialmenteReciclado: 0; PotencialPrivacaoDeAguaConsumoDeAguaPonderado: 4.5; EnergiaTermicaExportada: 0; ItemENovo: Sim; ItemEReciclado: Não; VidaÚtilEsperada: 50; SubstanciasPerigosas: Não; PotencialDeEsgotamentoAbioticoDosRecursosFosseis: 203; PotencialDeEsgotamentoAbioticoDosRecursosNaoFosseisMineraisEMetais: 0.000701; PotencialDeAquecimentoGlobalBiogenico: -0.48; CombustiveisFosseisComPotencialDeAquecimentoGlobal: 13.9; PotencialDeAquecimentoGlobalUsoDoSoloEMudancaDeUsoDoSolo: 0.0246; PotencialDeEutrofizacaoFraccaoDeNutrientesQueAtingemOCompartimentoFinalDeAguaDoce: 0.000189; PotencialDeEutrofizacaoFraccaoDeNutrientesQueAtingemOCompartimentoFinalMarinho: 0.0122; EnergiaRecuperada: 0.00739; ConsumoDeAguaDoce: 0.113; UtilizacaoLiquidaDeAguaDoce: 0.113; ResiduosPerigososEliminados: 0.00221; ResiduosNaoPerigososEliminados: 1.83; MassaTotalDeResiduosRadioactivosEliminados: 0.000394; EnergiaElectricaExportada: 1.55; MateriaisParaRecuperacaoDeEnergia: 0.00739; MateriaisParaReciclagem: 0.0253; UnidadeEPD: 1 m²
Type - IFC.REVIGRÉS-Dados gerais-Wall Covering - Nome: REVIGRÉS-LOCUS-BASE-29.5x59.2-SOFT GRIP-BONE; TipoProduto: Prensado a seco: grupo BIa UGL | Grés porcelânico técnico; NumeroDeRegistoDAP: EPD-REV-20240006-CCC1-EN; ReferenciaDAP: -; UrlDOP: -
Classification: C3010 (Uniformat)
Pset_WallCommon - ExtendToStructure: no; LoadBearing: no
IFC.REVIGRÉS-Dados do fabricante-Wall Covering - Type: Basic Wall: REVIGRÉS-LOCUS-BASE-29.5x59.2-SOFT GRIP-BONE
IFC.REVIGRÉS-Dados de desempenho-Wall Covering - Type: Basic Wall: REVIGRÉS-LOCUS-BASE-29.5x59.2-SOFT GRIP-BONE
IFC.REVIGRÉS-Dados de especificação-Wall Covering - Type: Basic Wall: REVIGRÉS-LOCUS-BASE-29.5x59.2-SOFT GRIP-BONE
IFC.REVIGRÉS-Dados geométricos-Wall Covering - Type: Basic Wall: REVIGRÉS-LOCUS-BASE-29.5x59.2-SOFT GRIP-BONE
IFC.REVIGRÉS-Dados de sustentabilidade-Wall Covering - Type: Basic Wall: REVIGRÉS-LOCUS-BASE-29.5x59.2-SOFT GRIP-BONE

# IfcWallStandardCase: Basic Wall:REVIGRÉS-LOCUS-BASE-29.5x59.2-SOFT GRIP-GRIS, Basic Wall:REVIGRÉS-LOCUS-BASE-29.5x59.2-SOFT GRIP-GRIS:37321
In: Level 1
Type - PredefinedType: STANDARD; Material: REVIGRÉS-LOCUS-BASE-30x60-SOFT GRIP-GRIS 8.5 mm
Type - Pset_ElementShading - Roughness: 304.8 mm
Type - Pset_ManufacturerTypeInformation - Manufacturer: REVIGRÉS
Type - Pset_ProductRequirements - Category: Walls
Type - Pset_QuantityTakeOff - Reference: 312F21V691
Type - Pset_ReinforcementBarPitchOfWall - Description: Stone effect in wall and floor full body porcelain tile; Reference: 312F21V691
Type - Pset_WallCommon - IsExternal: no; Reference: 312F21V691
Type - IFC.REVIGRÉS-Dados do fabricante-Wall Covering - FabricanteURL: https://www.revigres.pt/; ReferenciaModelo: Locus; NumeroGlobalDeItemComercial: 312F21V691; Acabamento: SOFT; Material: Grés porcelânico; IdentificadorDoOperadorEconomico: 501840856; UrlFabricanteArtigo: https://www.revigres.pt/colecoes/locus; PaisOrigem: Portugal
Type - IFC.REVIGRÉS-Dados de desempenho-Wall Covering - Rectilinearidade: ± 0.2% máx ± 1.0 mm; Ortogonalidade: ± 0.2% máx.± 1.5 mm; PlanaridadeDaSuperficie: ± 0.3% máx. ± 1.8 mm; QualidadeDaSuperficie: Cumpre; AbsorcaoDeAgua: < 0.05%; ModuloDeRuptura: > 45 N/mm²; ResistenciaAFlexao: > 2000 N; ResistenciaAAbrasaoProfunda: < 120 mm³; DilatacaoTermicaLinear: ≤ 8,0x10-6 °C-1; ResistenciaAoChoqueTermico: Resiste; DurabilidadeInterior: Cumpre; DurabilidadeResistenciaAoGeloDegelo: Resiste; ResistenciaAoEscorregamentoDIN51130: R11; ResistenciaAoEscorregamentoDIN51097: A; ResistenciaAoEscorregamentoENV51097: A; ResistenciaAoEscorregamentoENV12633: Class 2; ResistenciaAoEscorregamentoBS7976: > 36; ResistenciaAoEscorregamentoANSIA1371: ≥0,42; ResistenciaAoDeslizamentoENV12633: Class 2; ResistenciaAoDeslizamentoBS7976: > 36; ResistenciaAsManchas: Class 5; LibertacaoDeCadmio: 0; LibertacaoDeChumbo: 0
Type - IFC.REVIGRÉS-Dados de especificação-Wall Covering - VariacaoTonalidade: 3; NivelDeTrafego: 5; EPavimento: Sim; ERevestimento: Sim; EExterno: Sim
Type - IFC.REVIGRÉS-Dados geométricos-Wall Covering - AlturaNominal: 8.5 mm; ComprimentoNominal: 29.5 mm; LarguraNominal: 59.2 mm
Type - IFC.REVIGRÉS-Dados de sustentabilidade-Wall Covering - PotencialPrivacaoDeAguaConsumoDeAguaPonderado: 4.5; EnergiaTermicaExportada: 0; ItemENovo: Sim; ItemEParcialmenteReciclado: 0.23; ItemEReciclado: Sim; VidaÚtilEsperada: 50; SubstanciasPerigosas: Não; PotencialDeEsgotamentoAbioticoDosRecursosFosseis: 203; PotencialDeEsgotamentoAbioticoDosRecursosNaoFosseisMineraisEMetais: 0.000701; PotencialDeAquecimentoGlobalBiogenico: -0.48; CombustiveisFosseisComPotencialDeAquecimentoGlobal: 13.9; PotencialDeAquecimentoGlobalUsoDoSoloEMudancaDeUsoDoSolo: 0.0246; PotencialDeEutrofizacaoFraccaoDeNutrientesQueAtingemOCompartimentoFinalDeAguaDoce: 0.000189; PotencialDeEutrofizacaoFraccaoDeNutrientesQueAtingemOCompartimentoFinalMarinho: 0.0122; EnergiaRecuperada: 0.00739; ConsumoDeAguaDoce: 0.113; UtilizacaoLiquidaDeAguaDoce: 0.113; ResiduosPerigososEliminados: 0.00221; ResiduosNaoPerigososEliminados: 1.83; MassaTotalDeResiduosRadioactivosEliminados: 0.000394; EnergiaElectricaExportada: 1.55; MateriaisParaRecuperacaoDeEnergia: 0.00739; MateriaisParaReciclagem: 0.0253; UnidadeEPD: 1 m²
Type - IFC.REVIGRÉS-Dados gerais-Wall Covering - Nome: REVIGRÉS-LOCUS-BASE-29.5x59.2-SOFT GRIP-GRIS; TipoProduto: Prensado a seco: grupo BIa UGL | Grés porcelânico técnico; NumeroDeRegistoDAP: EPD-REV-20240006-CCC1-EN; ReferenciaDAP: -; UrlDOP: -
Classification: C3010 (Uniformat)
Pset_WallCommon - ExtendToStructure: no; LoadBearing: no
IFC.REVIGRÉS-Dados do fabricante-Wall Covering - Type: Basic Wall: REVIGRÉS-LOCUS-BASE-29.5x59.2-SOFT GRIP-GRIS
IFC.REVIGRÉS-Dados de desempenho-Wall Covering - Type: Basic Wall: REVIGRÉS-LOCUS-BASE-29.5x59.2-SOFT GRIP-GRIS
IFC.REVIGRÉS-Dados de especificação-Wall Covering - Type: Basic Wall: REVIGRÉS-LOCUS-BASE-29.5x59.2-SOFT GRIP-GRIS
IFC.REVIGRÉS-Dados geométricos-Wall Covering - Type: Basic Wall: REVIGRÉS-LOCUS-BASE-29.5x59.2-SOFT GRIP-GRIS
IFC.REVIGRÉS-Dados de sustentabilidade-Wall Covering - Type: Basic Wall: REVIGRÉS-LOCUS-BASE-29.5x59.2-SOFT GRIP-GRIS

# IfcWallStandardCase: Basic Wall:REVIGRÉS-LOCUS-BASE-29.5x59.2-SOFT GRIP-SMOG, Basic Wall:REVIGRÉS-LOCUS-BASE-29.5x59.2-SOFT GRIP-SMOG:37836
In: Level 1
Type - PredefinedType: STANDARD; Material: REVIGRÉS-LOCUS-BASE-30x60-SOFT GRIP-SMOG 8.5 mm
Type - Pset_ElementShading - Roughness: 304.8 mm
Type - Pset_ManufacturerTypeInformation - Manufacturer: REVIGRÉS
Type - Pset_ProductRequirements - Category: Walls
Type - Pset_QuantityTakeOff - Reference: 312F21V701
Type - Pset_ReinforcementBarPitchOfWall - Description: Stone effect in wall and floor full body porcelain tile; Reference: 312F21V701
Type - Pset_WallCommon - IsExternal: no; Reference: 312F21V701
Type - IFC.REVIGRÉS-Dados do fabricante-Wall Covering - FabricanteURL: https://www.revigres.pt/; ReferenciaModelo: Locus; NumeroGlobalDeItemComercial: 312F21V701; Acabamento: SOFT; Material: Grés porcelânico; IdentificadorDoOperadorEconomico: 501840856; UrlFabricanteArtigo: https://www.revigres.pt/colecoes/locus; PaisOrigem: Portugal
Type - IFC.REVIGRÉS-Dados de desempenho-Wall Covering - Rectilinearidade: ± 0.2% máx ± 1.0 mm; Ortogonalidade: ± 0.2% máx.± 1.5 mm; PlanaridadeDaSuperficie: ± 0.3% máx. ± 1.8 mm; QualidadeDaSuperficie: Cumpre; AbsorcaoDeAgua: < 0.05%; ModuloDeRuptura: > 45 N/mm²; ResistenciaAFlexao: > 2000 N; ResistenciaAAbrasaoProfunda: < 120 mm³; DilatacaoTermicaLinear: ≤ 8,0x10-6 °C-1; ResistenciaAoChoqueTermico: Resiste; DurabilidadeInterior: Cumpre; DurabilidadeResistenciaAoGeloDegelo: Resiste; ResistenciaAoEscorregamentoDIN51130: R11; ResistenciaAoEscorregamentoDIN51097: A; ResistenciaAoEscorregamentoENV51097: A; ResistenciaAoEscorregamentoENV12633: Class 2; ResistenciaAoEscorregamentoBS7976: > 36; ResistenciaAoEscorregamentoANSIA1371: ≥0,42; ResistenciaAoDeslizamentoENV12633: Class 2; ResistenciaAoDeslizamentoBS7976: > 36; ResistenciaAsManchas: Class 5; LibertacaoDeCadmio: 0; LibertacaoDeChumbo: 0
Type - IFC.REVIGRÉS-Dados de especificação-Wall Covering - VariacaoTonalidade: 3; NivelDeTrafego: 5; EPavimento: Sim; ERevestimento: Sim; EExterno: Sim
Type - IFC.REVIGRÉS-Dados geométricos-Wall Covering - AlturaNominal: 8.5 mm; ComprimentoNominal: 29.5 mm; LarguraNominal: 59.2 mm
Type - IFC.REVIGRÉS-Dados de sustentabilidade-Wall Covering - PotencialPrivacaoDeAguaConsumoDeAguaPonderado: 4.5; EnergiaTermicaExportada: 0; ItemENovo: Sim; ItemEParcialmenteReciclado: 0.29; ItemEReciclado: Sim; VidaÚtilEsperada: 50; SubstanciasPerigosas: Não; PotencialDeEsgotamentoAbioticoDosRecursosFosseis: 203; PotencialDeEsgotamentoAbioticoDosRecursosNaoFosseisMineraisEMetais: 0.000701; PotencialDeAquecimentoGlobalBiogenico: -0.48; CombustiveisFosseisComPotencialDeAquecimentoGlobal: 13.9; PotencialDeAquecimentoGlobalUsoDoSoloEMudancaDeUsoDoSolo: 0.0246; PotencialDeEutrofizacaoFraccaoDeNutrientesQueAtingemOCompartimentoFinalDeAguaDoce: 0.000189; PotencialDeEutrofizacaoFraccaoDeNutrientesQueAtingemOCompartimentoFinalMarinho: 0.0122; EnergiaRecuperada: 0.00739; ConsumoDeAguaDoce: 0.113; UtilizacaoLiquidaDeAguaDoce: 0.113; ResiduosPerigososEliminados: 0.00221; ResiduosNaoPerigososEliminados: 1.83; MassaTotalDeResiduosRadioactivosEliminados: 0.000394; EnergiaElectricaExportada: 1.55; MateriaisParaRecuperacaoDeEnergia: 0.00739; MateriaisParaReciclagem: 0.0253; UnidadeEPD: 1 m²
Type - IFC.REVIGRÉS-Dados gerais-Wall Covering - Nome: REVIGRÉS-LOCUS-BASE-29.5x59.2-SOFT GRIP-SMOG; TipoProduto: Prensado a seco: grupo BIa UGL | Grés porcelânico técnico; NumeroDeRegistoDAP: EPD-REV-20240006-CCC1-EN; ReferenciaDAP: -; UrlDOP: -
Classification: C3010 (Uniformat)
Pset_WallCommon - ExtendToStructure: no; LoadBearing: no
IFC.REVIGRÉS-Dados do fabricante-Wall Covering - Type: Basic Wall: REVIGRÉS-LOCUS-BASE-29.5x59.2-SOFT GRIP-SMOG
IFC.REVIGRÉS-Dados de desempenho-Wall Covering - Type: Basic Wall: REVIGRÉS-LOCUS-BASE-29.5x59.2-SOFT GRIP-SMOG
IFC.REVIGRÉS-Dados de especificação-Wall Covering - Type: Basic Wall: REVIGRÉS-LOCUS-BASE-29.5x59.2-SOFT GRIP-SMOG
IFC.REVIGRÉS-Dados geométricos-Wall Covering - Type: Basic Wall: REVIGRÉS-LOCUS-BASE-29.5x59.2-SOFT GRIP-SMOG
IFC.REVIGRÉS-Dados de sustentabilidade-Wall Covering - Type: Basic Wall: REVIGRÉS-LOCUS-BASE-29.5x59.2-SOFT GRIP-SMOG

# IfcWallStandardCase: Basic Wall:REVIGRÉS-LOCUS-BASE-44.35x88.9-SILK-ALLOY, Basic Wall:REVIGRÉS-LOCUS-BASE-44.35x88.9-SILK-ALLOY:36366
In: Level 1
Type - PredefinedType: STANDARD; Material: REVIGRÉS-LOCUS-BASE-45X90-SILK-ALLOY 10.5 mm
Type - Pset_ElementShading - Roughness: 304.8 mm
Type - Pset_ManufacturerTypeInformation - Manufacturer: REVIGRÉS
Type - Pset_ProductRequirements - Category: Walls
Type - Pset_QuantityTakeOff - Reference: 312GH8V671
Type - Pset_ReinforcementBarPitchOfWall - Description: Stone effect in wall and floor full body porcelain tile; Reference: 312GH8V671
Type - Pset_WallCommon - IsExternal: no; Reference: 312GH8V671
Type - IFC.REVIGRÉS-Dados do fabricante-Wall Covering - FabricanteURL: https://www.revigres.pt/; ReferenciaModelo: Locus; NumeroGlobalDeItemComercial: 312GH8V671; Acabamento: SILK; Material: Grés porcelânico; IdentificadorDoOperadorEconomico: 501840856; UrlFabricanteArtigo: https://www.revigres.pt/colecoes/locus; PaisOrigem: Portugal
Type - IFC.REVIGRÉS-Dados de desempenho-Wall Covering - Rectilinearidade: ± 0.2% máx.± 0.8 mm; Ortogonalidade: ± 0.2% máx.± 1.5 mm; PlanaridadeDaSuperficie: ± 0.3% máx. ± 1.8 mm; QualidadeDaSuperficie: Cumpre; AbsorcaoDeAgua: < 0.05%; ModuloDeRuptura: > 45 N/mm²; ResistenciaAFlexao: > 2000 N; ResistenciaAAbrasaoProfunda: < 120 mm³; DilatacaoTermicaLinear: ≤ 8,0x10-6 °C-1; ResistenciaAoChoqueTermico: Resiste; DurabilidadeInterior: Cumpre; DurabilidadeResistenciaAoGeloDegelo: Resiste; ResistenciaAoEscorregamentoDIN51130: R9; ResistenciaAoEscorregamentoDIN51097: A; ResistenciaAoEscorregamentoENV51097: A; ResistenciaAoEscorregamentoENV12633: Class 1; ResistenciaAoEscorregamentoBS7976: -; ResistenciaAoEscorregamentoANSIA1371: ≥0,42; ResistenciaAoDeslizamentoENV12633: Class 1; ResistenciaAoDeslizamentoBS7976: -; ResistenciaAsManchas: Class 5; LibertacaoDeCadmio: 0; LibertacaoDeChumbo: 0
Type - IFC.REVIGRÉS-Dados de especificação-Wall Covering - VariacaoTonalidade: 3; NivelDeTrafego: 5; EPavimento: Sim; ERevestimento: Sim; EExterno: Sim
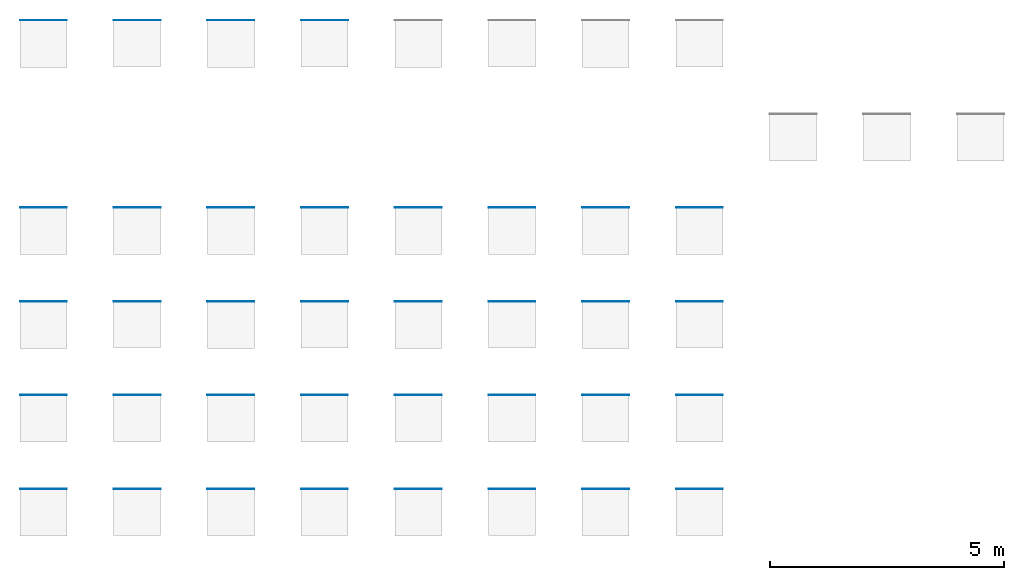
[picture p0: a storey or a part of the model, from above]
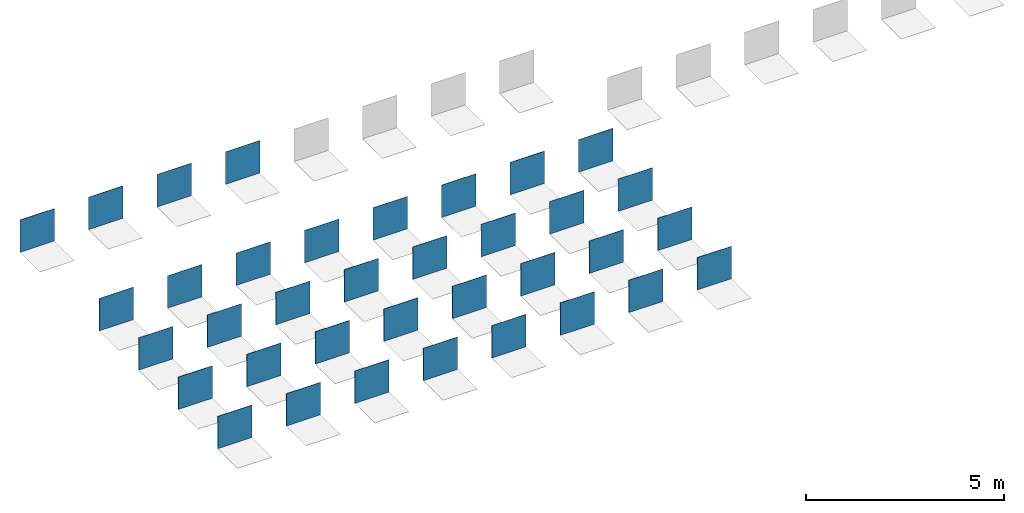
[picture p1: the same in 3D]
Properties of the parts of a building model (IFC2X3), part 5 of 7

# IfcWallStandardCase: Basic Wall:REVIGRÉS-LOCUS-BASE-44.35x88.9-SILK-ALLOY, Basic Wall:REVIGRÉS-LOCUS-BASE-44.35x88.9-SILK-ALLOY:36366
Type - IFC.REVIGRÉS-Dados geométricos-Wall Covering - AlturaNominal: 10.5 mm; ComprimentoNominal: 44.35 mm; LarguraNominal: 88.9 mm
Type - IFC.REVIGRÉS-Dados de sustentabilidade-Wall Covering - ItemEParcialmenteReciclado: 0; PotencialPrivacaoDeAguaConsumoDeAguaPonderado: 4.5; EnergiaTermicaExportada: 0; ItemENovo: Sim; ItemEReciclado: Não; VidaÚtilEsperada: 50; SubstanciasPerigosas: Não; PotencialDeEsgotamentoAbioticoDosRecursosFosseis: 203; PotencialDeEsgotamentoAbioticoDosRecursosNaoFosseisMineraisEMetais: 0.000701; PotencialDeAquecimentoGlobalBiogenico: -0.48; CombustiveisFosseisComPotencialDeAquecimentoGlobal: 13.9; PotencialDeAquecimentoGlobalUsoDoSoloEMudancaDeUsoDoSolo: 0.0246; PotencialDeEutrofizacaoFraccaoDeNutrientesQueAtingemOCompartimentoFinalDeAguaDoce: 0.000189; PotencialDeEutrofizacaoFraccaoDeNutrientesQueAtingemOCompartimentoFinalMarinho: 0.0122; EnergiaRecuperada: 0.00739; ConsumoDeAguaDoce: 0.113; UtilizacaoLiquidaDeAguaDoce: 0.113; ResiduosPerigososEliminados: 0.00221; ResiduosNaoPerigososEliminados: 1.83; MassaTotalDeResiduosRadioactivosEliminados: 0.000394; EnergiaElectricaExportada: 1.55; MateriaisParaRecuperacaoDeEnergia: 0.00739; MateriaisParaReciclagem: 0.0253; UnidadeEPD: 1 m²
Type - IFC.REVIGRÉS-Dados gerais-Wall Covering - Nome: REVIGRÉS-LOCUS-BASE-44.35x88.9-SILK-ALLOY; TipoProduto: Prensado a seco: grupo BIa UGL | Grés porcelânico técnico; NumeroDeRegistoDAP: EPD-REV-20240006-CCC1-EN; ReferenciaDAP: -; UrlDOP: -
Classification: C3010 (Uniformat)
Pset_WallCommon - ExtendToStructure: no; LoadBearing: no
IFC.REVIGRÉS-Dados do fabricante-Wall Covering - Type: Basic Wall: REVIGRÉS-LOCUS-BASE-44.35x88.9-SILK-ALLOY
IFC.REVIGRÉS-Dados de desempenho-Wall Covering - Type: Basic Wall: REVIGRÉS-LOCUS-BASE-44.35x88.9-SILK-ALLOY
IFC.REVIGRÉS-Dados de especificação-Wall Covering - Type: Basic Wall: REVIGRÉS-LOCUS-BASE-44.35x88.9-SILK-ALLOY
IFC.REVIGRÉS-Dados geométricos-Wall Covering - Type: Basic Wall: REVIGRÉS-LOCUS-BASE-44.35x88.9-SILK-ALLOY
IFC.REVIGRÉS-Dados de sustentabilidade-Wall Covering - Type: Basic Wall: REVIGRÉS-LOCUS-BASE-44.35x88.9-SILK-ALLOY

# IfcWallStandardCase: Basic Wall:REVIGRÉS-LOCUS-BASE-44.35x88.9-SILK-BONE, Basic Wall:REVIGRÉS-LOCUS-BASE-44.35x88.9-SILK-BONE:36694
In: Level 1
Type - PredefinedType: STANDARD; Material: REVIGRÉS-LOCUS-BASE-45X90-SILK-BONE 10.5 mm
Type - Pset_ElementShading - Roughness: 304.8 mm
Type - Pset_ManufacturerTypeInformation - Manufacturer: REVIGRÉS
Type - Pset_ProductRequirements - Category: Walls
Type - Pset_QuantityTakeOff - Reference: 312GH8V681
Type - Pset_ReinforcementBarPitchOfWall - Description: Stone effect in wall and floor full body porcelain tile; Reference: 312GH8V681
Type - Pset_WallCommon - IsExternal: no; Reference: 312GH8V681
Type - IFC.REVIGRÉS-Dados do fabricante-Wall Covering - FabricanteURL: https://www.revigres.pt/; ReferenciaModelo: Locus; NumeroGlobalDeItemComercial: 312GH8V681; Acabamento: SILK; Material: Grés porcelânico; IdentificadorDoOperadorEconomico: 501840856; UrlFabricanteArtigo: https://www.revigres.pt/colecoes/locus; PaisOrigem: Portugal
Type - IFC.REVIGRÉS-Dados de desempenho-Wall Covering - Rectilinearidade: ± 0.2% máx.± 0.8 mm; Ortogonalidade: ± 0.2% máx.± 1.5 mm; PlanaridadeDaSuperficie: ± 0.3% máx. ± 1.8 mm; QualidadeDaSuperficie: Cumpre; AbsorcaoDeAgua: < 0.05%; ModuloDeRuptura: > 45 N/mm²; ResistenciaAFlexao: > 2000 N; ResistenciaAAbrasaoProfunda: < 120 mm³; DilatacaoTermicaLinear: ≤ 8,0x10-6 °C-1; ResistenciaAoChoqueTermico: Resiste; DurabilidadeInterior: Cumpre; DurabilidadeResistenciaAoGeloDegelo: Resiste; ResistenciaAoEscorregamentoDIN51130: R9; ResistenciaAoEscorregamentoDIN51097: A; ResistenciaAoEscorregamentoENV51097: A; ResistenciaAoEscorregamentoENV12633: Class 1; ResistenciaAoEscorregamentoBS7976: -; ResistenciaAoEscorregamentoANSIA1371: ≥0,42; ResistenciaAoDeslizamentoENV12633: Class 1; ResistenciaAoDeslizamentoBS7976: -; ResistenciaAsManchas: Class 5; LibertacaoDeCadmio: 0; LibertacaoDeChumbo: 0
Type - IFC.REVIGRÉS-Dados de especificação-Wall Covering - VariacaoTonalidade: 3; NivelDeTrafego: 5; EPavimento: Sim; ERevestimento: Sim; EExterno: Sim
Type - IFC.REVIGRÉS-Dados geométricos-Wall Covering - AlturaNominal: 10.5 mm; ComprimentoNominal: 44.35 mm; LarguraNominal: 88.9 mm
Type - IFC.REVIGRÉS-Dados de sustentabilidade-Wall Covering - ItemEParcialmenteReciclado: 0; PotencialPrivacaoDeAguaConsumoDeAguaPonderado: 4.5; EnergiaTermicaExportada: 0; ItemENovo: Sim; ItemEReciclado: Não; VidaÚtilEsperada: 50; SubstanciasPerigosas: Não; PotencialDeEsgotamentoAbioticoDosRecursosFosseis: 203; PotencialDeEsgotamentoAbioticoDosRecursosNaoFosseisMineraisEMetais: 0.000701; PotencialDeAquecimentoGlobalBiogenico: -0.48; CombustiveisFosseisComPotencialDeAquecimentoGlobal: 13.9; PotencialDeAquecimentoGlobalUsoDoSoloEMudancaDeUsoDoSolo: 0.0246; PotencialDeEutrofizacaoFraccaoDeNutrientesQueAtingemOCompartimentoFinalDeAguaDoce: 0.000189; PotencialDeEutrofizacaoFraccaoDeNutrientesQueAtingemOCompartimentoFinalMarinho: 0.0122; EnergiaRecuperada: 0.00739; ConsumoDeAguaDoce: 0.113; UtilizacaoLiquidaDeAguaDoce: 0.113; ResiduosPerigososEliminados: 0.00221; ResiduosNaoPerigososEliminados: 1.83; MassaTotalDeResiduosRadioactivosEliminados: 0.000394; EnergiaElectricaExportada: 1.55; MateriaisParaRecuperacaoDeEnergia: 0.00739; MateriaisParaReciclagem: 0.0253; UnidadeEPD: 1 m²
Type - IFC.REVIGRÉS-Dados gerais-Wall Covering - Nome: REVIGRÉS-LOCUS-BASE-44.35x88.9-SILK-BONE; TipoProduto: Prensado a seco: grupo BIa UGL | Grés porcelânico técnico; NumeroDeRegistoDAP: EPD-REV-20240006-CCC1-EN; ReferenciaDAP: -; UrlDOP: -
Classification: C3010 (Uniformat)
Pset_WallCommon - ExtendToStructure: no; LoadBearing: no
IFC.REVIGRÉS-Dados do fabricante-Wall Covering - Type: Basic Wall: REVIGRÉS-LOCUS-BASE-44.35x88.9-SILK-BONE
IFC.REVIGRÉS-Dados de desempenho-Wall Covering - Type: Basic Wall: REVIGRÉS-LOCUS-BASE-44.35x88.9-SILK-BONE
IFC.REVIGRÉS-Dados de especificação-Wall Covering - Type: Basic Wall: REVIGRÉS-LOCUS-BASE-44.35x88.9-SILK-BONE
IFC.REVIGRÉS-Dados geométricos-Wall Covering - Type: Basic Wall: REVIGRÉS-LOCUS-BASE-44.35x88.9-SILK-BONE
IFC.REVIGRÉS-Dados de sustentabilidade-Wall Covering - Type: Basic Wall: REVIGRÉS-LOCUS-BASE-44.35x88.9-SILK-BONE

# IfcWallStandardCase: Basic Wall:REVIGRÉS-LOCUS-BASE-44.35x88.9-SILK-GRIS, Basic Wall:REVIGRÉS-LOCUS-BASE-44.35x88.9-SILK-GRIS:37361
In: Level 1
Type - PredefinedType: STANDARD; Material: REVIGRÉS-LOCUS-BASE-45X90-SILK-GRIS 10.5 mm
Type - Pset_ElementShading - Roughness: 304.8 mm
Type - Pset_ManufacturerTypeInformation - Manufacturer: REVIGRÉS
Type - Pset_ProductRequirements - Category: Walls
Type - Pset_QuantityTakeOff - Reference: 312GH8V691
Type - Pset_ReinforcementBarPitchOfWall - Description: Stone effect in wall and floor full body porcelain tile; Reference: 312GH8V691
Type - Pset_WallCommon - IsExternal: no; Reference: 312GH8V691
Type - IFC.REVIGRÉS-Dados do fabricante-Wall Covering - FabricanteURL: https://www.revigres.pt/; ReferenciaModelo: Locus; NumeroGlobalDeItemComercial: 312GH8V691; Acabamento: SILK; Material: Grés porcelânico; IdentificadorDoOperadorEconomico: 501840856; UrlFabricanteArtigo: https://www.revigres.pt/colecoes/locus; PaisOrigem: Portugal
Type - IFC.REVIGRÉS-Dados de desempenho-Wall Covering - Rectilinearidade: ± 0.2% máx.± 0.8 mm; Ortogonalidade: ± 0.2% máx.± 1.5 mm; PlanaridadeDaSuperficie: ± 0.3% máx. ± 1.8 mm; QualidadeDaSuperficie: Cumpre; AbsorcaoDeAgua: < 0.05%; ModuloDeRuptura: > 45 N/mm²; ResistenciaAFlexao: > 2000 N; ResistenciaAAbrasaoProfunda: < 120 mm³; DilatacaoTermicaLinear: ≤ 8,0x10-6 °C-1; ResistenciaAoChoqueTermico: Resiste; DurabilidadeInterior: Cumpre; DurabilidadeResistenciaAoGeloDegelo: Resiste; ResistenciaAoEscorregamentoDIN51130: R9; ResistenciaAoEscorregamentoDIN51097: A; ResistenciaAoEscorregamentoENV51097: A; ResistenciaAoEscorregamentoENV12633: Class 1; ResistenciaAoEscorregamentoBS7976: -; ResistenciaAoEscorregamentoANSIA1371: ≥0,42; ResistenciaAoDeslizamentoENV12633: Class 1; ResistenciaAoDeslizamentoBS7976: -; ResistenciaAsManchas: Class 5; LibertacaoDeCadmio: 0; LibertacaoDeChumbo: 0
Type - IFC.REVIGRÉS-Dados de especificação-Wall Covering - VariacaoTonalidade: 3; NivelDeTrafego: 5; EPavimento: Sim; ERevestimento: Sim; EExterno: Sim
Type - IFC.REVIGRÉS-Dados geométricos-Wall Covering - AlturaNominal: 10.5 mm; ComprimentoNominal: 44.35 mm; LarguraNominal: 88.9 mm
Type - IFC.REVIGRÉS-Dados de sustentabilidade-Wall Covering - PotencialPrivacaoDeAguaConsumoDeAguaPonderado: 4.5; EnergiaTermicaExportada: 0; ItemENovo: Sim; ItemEParcialmenteReciclado: 0.23; ItemEReciclado: Sim; VidaÚtilEsperada: 50; SubstanciasPerigosas: Não; PotencialDeEsgotamentoAbioticoDosRecursosFosseis: 203; PotencialDeEsgotamentoAbioticoDosRecursosNaoFosseisMineraisEMetais: 0.000701; PotencialDeAquecimentoGlobalBiogenico: -0.48; CombustiveisFosseisComPotencialDeAquecimentoGlobal: 13.9; PotencialDeAquecimentoGlobalUsoDoSoloEMudancaDeUsoDoSolo: 0.0246; PotencialDeEutrofizacaoFraccaoDeNutrientesQueAtingemOCompartimentoFinalDeAguaDoce: 0.000189; PotencialDeEutrofizacaoFraccaoDeNutrientesQueAtingemOCompartimentoFinalMarinho: 0.0122; EnergiaRecuperada: 0.00739; ConsumoDeAguaDoce: 0.113; UtilizacaoLiquidaDeAguaDoce: 0.113; ResiduosPerigososEliminados: 0.00221; ResiduosNaoPerigososEliminados: 1.83; MassaTotalDeResiduosRadioactivosEliminados: 0.000394; EnergiaElectricaExportada: 1.55; MateriaisParaRecuperacaoDeEnergia: 0.00739; MateriaisParaReciclagem: 0.0253; UnidadeEPD: 1 m²
Type - IFC.REVIGRÉS-Dados gerais-Wall Covering - Nome: REVIGRÉS-LOCUS-BASE-44.35x88.9-SILK-GRIS; TipoProduto: Prensado a seco: grupo BIa UGL | Grés porcelânico técnico; NumeroDeRegistoDAP: EPD-REV-20240006-CCC1-EN; ReferenciaDAP: -; UrlDOP: -
Classification: C3010 (Uniformat)
Pset_WallCommon - ExtendToStructure: no; LoadBearing: no
IFC.REVIGRÉS-Dados do fabricante-Wall Covering - Type: Basic Wall: REVIGRÉS-LOCUS-BASE-44.35x88.9-SILK-GRIS
IFC.REVIGRÉS-Dados de desempenho-Wall Covering - Type: Basic Wall: REVIGRÉS-LOCUS-BASE-44.35x88.9-SILK-GRIS
IFC.REVIGRÉS-Dados de especificação-Wall Covering - Type: Basic Wall: REVIGRÉS-LOCUS-BASE-44.35x88.9-SILK-GRIS
IFC.REVIGRÉS-Dados geométricos-Wall Covering - Type: Basic Wall: REVIGRÉS-LOCUS-BASE-44.35x88.9-SILK-GRIS
IFC.REVIGRÉS-Dados de sustentabilidade-Wall Covering - Type: Basic Wall: REVIGRÉS-LOCUS-BASE-44.35x88.9-SILK-GRIS

# IfcWallStandardCase: Basic Wall:REVIGRÉS-LOCUS-BASE-44.35x88.9-SILK-SMOG, Basic Wall:REVIGRÉS-LOCUS-BASE-44.35x88.9-SILK-SMOG:37876
In: Level 1
Type - PredefinedType: STANDARD; Material: REVIGRÉS-LOCUS-BASE-45X90-SILK-SMOG 10.5 mm
Type - Pset_ElementShading - Roughness: 304.8 mm
Type - Pset_ManufacturerTypeInformation - Manufacturer: REVIGRÉS
Type - Pset_ProductRequirements - Category: Walls
Type - Pset_QuantityTakeOff - Reference: 312GH8V701
Type - Pset_ReinforcementBarPitchOfWall - Description: Stone effect in wall and floor full body porcelain tile; Reference: 312GH8V701
Type - Pset_WallCommon - IsExternal: no; Reference: 312GH8V701
Type - IFC.REVIGRÉS-Dados do fabricante-Wall Covering - FabricanteURL: https://www.revigres.pt/; ReferenciaModelo: Locus; NumeroGlobalDeItemComercial: 312GH8V701; Acabamento: SILK; Material: Grés porcelânico; IdentificadorDoOperadorEconomico: 501840856; UrlFabricanteArtigo: https://www.revigres.pt/colecoes/locus; PaisOrigem: Portugal
Type - IFC.REVIGRÉS-Dados de desempenho-Wall Covering - Rectilinearidade: ± 0.2% máx.± 0.8 mm; Ortogonalidade: ± 0.2% máx.± 1.5 mm; PlanaridadeDaSuperficie: ± 0.3% máx. ± 1.8 mm; QualidadeDaSuperficie: Cumpre; AbsorcaoDeAgua: < 0.05%; ModuloDeRuptura: > 45 N/mm²; ResistenciaAFlexao: > 2000 N; ResistenciaAAbrasaoProfunda: < 120 mm³; DilatacaoTermicaLinear: ≤ 8,0x10-6 °C-1; ResistenciaAoChoqueTermico: Resiste; DurabilidadeInterior: Cumpre; DurabilidadeResistenciaAoGeloDegelo: Resiste; ResistenciaAoEscorregamentoDIN51130: R9; ResistenciaAoEscorregamentoDIN51097: A; ResistenciaAoEscorregamentoENV51097: A; ResistenciaAoEscorregamentoENV12633: Class 1; ResistenciaAoEscorregamentoBS7976: -; ResistenciaAoEscorregamentoANSIA1371: ≥0,42; ResistenciaAoDeslizamentoENV12633: Class 1; ResistenciaAoDeslizamentoBS7976: -; ResistenciaAsManchas: Class 5; LibertacaoDeCadmio: 0; LibertacaoDeChumbo: 0
Type - IFC.REVIGRÉS-Dados de especificação-Wall Covering - VariacaoTonalidade: 3; NivelDeTrafego: 5; EPavimento: Sim; ERevestimento: Sim; EExterno: Sim
Type - IFC.REVIGRÉS-Dados geométricos-Wall Covering - AlturaNominal: 10.5 mm; ComprimentoNominal: 44.35 mm; LarguraNominal: 88.9 mm
Type - IFC.REVIGRÉS-Dados de sustentabilidade-Wall Covering - PotencialPrivacaoDeAguaConsumoDeAguaPonderado: 4.5; EnergiaTermicaExportada: 0; ItemENovo: Sim; ItemEParcialmenteReciclado: 0.29; ItemEReciclado: Sim; VidaÚtilEsperada: 50; SubstanciasPerigosas: Não; PotencialDeEsgotamentoAbioticoDosRecursosFosseis: 203; PotencialDeEsgotamentoAbioticoDosRecursosNaoFosseisMineraisEMetais: 0.000701; PotencialDeAquecimentoGlobalBiogenico: -0.48; CombustiveisFosseisComPotencialDeAquecimentoGlobal: 13.9; PotencialDeAquecimentoGlobalUsoDoSoloEMudancaDeUsoDoSolo: 0.0246; PotencialDeEutrofizacaoFraccaoDeNutrientesQueAtingemOCompartimentoFinalDeAguaDoce: 0.000189; PotencialDeEutrofizacaoFraccaoDeNutrientesQueAtingemOCompartimentoFinalMarinho: 0.0122; EnergiaRecuperada: 0.00739; ConsumoDeAguaDoce: 0.113; UtilizacaoLiquidaDeAguaDoce: 0.113; ResiduosPerigososEliminados: 0.00221; ResiduosNaoPerigososEliminados: 1.83; MassaTotalDeResiduosRadioactivosEliminados: 0.000394; EnergiaElectricaExportada: 1.55; MateriaisParaRecuperacaoDeEnergia: 0.00739; MateriaisParaReciclagem: 0.0253; UnidadeEPD: 1 m²
Type - IFC.REVIGRÉS-Dados gerais-Wall Covering - Nome: REVIGRÉS-LOCUS-BASE-44.35x88.9-SILK-SMOG; TipoProduto: Prensado a seco: grupo BIa UGL | Grés porcelânico técnico; NumeroDeRegistoDAP: EPD-REV-20240006-CCC1-EN; ReferenciaDAP: -; UrlDOP: -
Classification: C3010 (Uniformat)
Pset_WallCommon - ExtendToStructure: no; LoadBearing: no
IFC.REVIGRÉS-Dados do fabricante-Wall Covering - Type: Basic Wall: REVIGRÉS-LOCUS-BASE-44.35x88.9-SILK-SMOG
IFC.REVIGRÉS-Dados de desempenho-Wall Covering - Type: Basic Wall: REVIGRÉS-LOCUS-BASE-44.35x88.9-SILK-SMOG
IFC.REVIGRÉS-Dados de especificação-Wall Covering - Type: Basic Wall: REVIGRÉS-LOCUS-BASE-44.35x88.9-SILK-SMOG
IFC.REVIGRÉS-Dados geométricos-Wall Covering - Type: Basic Wall: REVIGRÉS-LOCUS-BASE-44.35x88.9-SILK-SMOG
IFC.REVIGRÉS-Dados de sustentabilidade-Wall Covering - Type: Basic Wall: REVIGRÉS-LOCUS-BASE-44.35x88.9-SILK-SMOG

# IfcWallStandardCase: Basic Wall:REVIGRÉS-LOCUS-BASE-44.35x88.9-SOFT GRIP-ALLOY, Basic Wall:REVIGRÉS-LOCUS-BASE-44.35x88.9-SOFT GRIP-ALLOY:36374
In: Level 1
Type - PredefinedType: STANDARD; Material: REVIGRÉS-LOCUS-BASE-45X90-SOFT GRIP-ALLOY 10.5 mm
Type - Pset_ElementShading - Roughness: 304.8 mm
Type - Pset_ManufacturerTypeInformation - Manufacturer: REVIGRÉS
Type - Pset_ProductRequirements - Category: Walls
Type - Pset_QuantityTakeOff - Reference: 312FH8V671
Type - Pset_ReinforcementBarPitchOfWall - Description: Stone effect in wall and floor full body porcelain tile; Reference: 312FH8V671
Type - Pset_WallCommon - IsExternal: no; Reference: 312FH8V671
Type - IFC.REVIGRÉS-Dados do fabricante-Wall Covering - FabricanteURL: https://www.revigres.pt/; ReferenciaModelo: Locus; NumeroGlobalDeItemComercial: 312FH8V671; Acabamento: SOFT; Material: Grés porcelânico; IdentificadorDoOperadorEconomico: 501840856; UrlFabricanteArtigo: https://www.revigres.pt/colecoes/locus; PaisOrigem: Portugal
Type - IFC.REVIGRÉS-Dados de desempenho-Wall Covering - Rectilinearidade: ± 0.2% máx ± 1.0 mm; Ortogonalidade: ± 0.2% máx.± 1.5 mm; PlanaridadeDaSuperficie: ± 0.3% máx. ± 1.8 mm; QualidadeDaSuperficie: Cumpre; AbsorcaoDeAgua: < 0.05%; ModuloDeRuptura: > 45 N/mm²; ResistenciaAFlexao: > 3500 N; ResistenciaAAbrasaoProfunda: < 120 mm³; DilatacaoTermicaLinear: ≤ 8,0x10-6 °C-1; ResistenciaAoChoqueTermico: Resiste; DurabilidadeInterior: Cumpre; DurabilidadeResistenciaAoGeloDegelo: Resiste; ResistenciaAoEscorregamentoDIN51130: R11; ResistenciaAoEscorregamentoDIN51097: A; ResistenciaAoEscorregamentoENV51097: A; ResistenciaAoEscorregamentoENV12633: Class 2; ResistenciaAoEscorregamentoBS7976: > 36; ResistenciaAoEscorregamentoANSIA1371: ≥0,42; ResistenciaAoDeslizamentoENV12633: Class 2; ResistenciaAoDeslizamentoBS7976: > 36; ResistenciaAsManchas: Class 5; LibertacaoDeCadmio: 0; LibertacaoDeChumbo: 0
Type - IFC.REVIGRÉS-Dados de especificação-Wall Covering - VariacaoTonalidade: 3; NivelDeTrafego: 5; EPavimento: Sim; ERevestimento: Sim; EExterno: Sim
Type - IFC.REVIGRÉS-Dados geométricos-Wall Covering - AlturaNominal: 10.5 mm; ComprimentoNominal: 44.35 mm; LarguraNominal: 88.9 mm
Type - IFC.REVIGRÉS-Dados de sustentabilidade-Wall Covering - ItemEParcialmenteReciclado: 0; PotencialPrivacaoDeAguaConsumoDeAguaPonderado: 4.5; EnergiaTermicaExportada: 0; ItemENovo: Sim; ItemEReciclado: Não; VidaÚtilEsperada: 50; SubstanciasPerigosas: Não; PotencialDeEsgotamentoAbioticoDosRecursosFosseis: 203; PotencialDeEsgotamentoAbioticoDosRecursosNaoFosseisMineraisEMetais: 0.000701; PotencialDeAquecimentoGlobalBiogenico: -0.48; CombustiveisFosseisComPotencialDeAquecimentoGlobal: 13.9; PotencialDeAquecimentoGlobalUsoDoSoloEMudancaDeUsoDoSolo: 0.0246; PotencialDeEutrofizacaoFraccaoDeNutrientesQueAtingemOCompartimentoFinalDeAguaDoce: 0.000189; PotencialDeEutrofizacaoFraccaoDeNutrientesQueAtingemOCompartimentoFinalMarinho: 0.0122; EnergiaRecuperada: 0.00739; ConsumoDeAguaDoce: 0.113; UtilizacaoLiquidaDeAguaDoce: 0.113; ResiduosPerigososEliminados: 0.00221; ResiduosNaoPerigososEliminados: 1.83; MassaTotalDeResiduosRadioactivosEliminados: 0.000394; EnergiaElectricaExportada: 1.55; MateriaisParaRecuperacaoDeEnergia: 0.00739; MateriaisParaReciclagem: 0.0253; UnidadeEPD: 1 m²
Type - IFC.REVIGRÉS-Dados gerais-Wall Covering - Nome: REVIGRÉS-LOCUS-BASE-44.35x88.9-SOFT GRIP-ALLOY; TipoProduto: Prensado a seco: grupo BIa UGL | Grés porcelânico técnico; NumeroDeRegistoDAP: EPD-REV-20240006-CCC1-EN; ReferenciaDAP: -; UrlDOP: -
Classification: C3010 (Uniformat)
Pset_WallCommon - ExtendToStructure: no; LoadBearing: no
IFC.REVIGRÉS-Dados do fabricante-Wall Covering - Type: Basic Wall: REVIGRÉS-LOCUS-BASE-44.35x88.9-SOFT GRIP-ALLOY
IFC.REVIGRÉS-Dados de desempenho-Wall Covering - Type: Basic Wall: REVIGRÉS-LOCUS-BASE-44.35x88.9-SOFT GRIP-ALLOY
IFC.REVIGRÉS-Dados de especificação-Wall Covering - Type: Basic Wall: REVIGRÉS-LOCUS-BASE-44.35x88.9-SOFT GRIP-ALLOY
IFC.REVIGRÉS-Dados geométricos-Wall Covering - Type: Basic Wall: REVIGRÉS-LOCUS-BASE-44.35x88.9-SOFT GRIP-ALLOY
IFC.REVIGRÉS-Dados de sustentabilidade-Wall Covering - Type: Basic Wall: REVIGRÉS-LOCUS-BASE-44.35x88.9-SOFT GRIP-ALLOY

# IfcWallStandardCase: Basic Wall:REVIGRÉS-LOCUS-BASE-44.35x88.9-SOFT GRIP-BONE, Basic Wall:REVIGRÉS-LOCUS-BASE-44.35x88.9-SOFT GRIP-BONE:36702
In: Level 1
Type - PredefinedType: STANDARD; Material: REVIGRÉS-LOCUS-BASE-45X90-SOFT GRIP-BONE 10.5 mm
Type - Pset_ElementShading - Roughness: 304.8 mm
Type - Pset_ManufacturerTypeInformation - Manufacturer: REVIGRÉS
Type - Pset_ProductRequirements - Category: Walls
Type - Pset_QuantityTakeOff - Reference: 312FH8V681
Type - Pset_ReinforcementBarPitchOfWall - Description: Stone effect in wall and floor full body porcelain tile; Reference: 312FH8V681
Type - Pset_WallCommon - IsExternal: no; Reference: 312FH8V681
Type - IFC.REVIGRÉS-Dados do fabricante-Wall Covering - FabricanteURL: https://www.revigres.pt/; ReferenciaModelo: Locus; NumeroGlobalDeItemComercial: 312FH8V681; Acabamento: SOFT; Material: Grés porcelânico; IdentificadorDoOperadorEconomico: 501840856; UrlFabricanteArtigo: https://www.revigres.pt/colecoes/locus; PaisOrigem: Portugal
Type - IFC.REVIGRÉS-Dados de desempenho-Wall Covering - Rectilinearidade: ± 0.2% máx ± 1.0 mm; Ortogonalidade: ± 0.2% máx.± 1.5 mm; PlanaridadeDaSuperficie: ± 0.3% máx. ± 1.8 mm; QualidadeDaSuperficie: Cumpre; AbsorcaoDeAgua: < 0.05%; ModuloDeRuptura: > 45 N/mm²; ResistenciaAFlexao: > 3500 N; ResistenciaAAbrasaoProfunda: < 120 mm³; DilatacaoTermicaLinear: ≤ 8,0x10-6 °C-1; ResistenciaAoChoqueTermico: Resiste; DurabilidadeInterior: Cumpre; DurabilidadeResistenciaAoGeloDegelo: Resiste; ResistenciaAoEscorregamentoDIN51130: R11; ResistenciaAoEscorregamentoDIN51097: A; ResistenciaAoEscorregamentoENV51097: A; ResistenciaAoEscorregamentoENV12633: Class 2; ResistenciaAoEscorregamentoBS7976: > 36; ResistenciaAoEscorregamentoANSIA1371: ≥0,42; ResistenciaAoDeslizamentoENV12633: Class 2; ResistenciaAoDeslizamentoBS7976: > 36; ResistenciaAsManchas: Class 5; LibertacaoDeCadmio: 0; LibertacaoDeChumbo: 0
Type - IFC.REVIGRÉS-Dados de especificação-Wall Covering - VariacaoTonalidade: 3; NivelDeTrafego: 5; EPavimento: Sim; ERevestimento: Sim; EExterno: Sim
Type - IFC.REVIGRÉS-Dados geométricos-Wall Covering - AlturaNominal: 10.5 mm; ComprimentoNominal: 44.35 mm; LarguraNominal: 88.9 mm
Type - IFC.REVIGRÉS-Dados de sustentabilidade-Wall Covering - ItemEParcialmenteReciclado: 0; PotencialPrivacaoDeAguaConsumoDeAguaPonderado: 4.5; EnergiaTermicaExportada: 0; ItemENovo: Sim; ItemEReciclado: Não; VidaÚtilEsperada: 50; SubstanciasPerigosas: Não; PotencialDeEsgotamentoAbioticoDosRecursosFosseis: 203; PotencialDeEsgotamentoAbioticoDosRecursosNaoFosseisMineraisEMetais: 0.000701; PotencialDeAquecimentoGlobalBiogenico: -0.48; CombustiveisFosseisComPotencialDeAquecimentoGlobal: 13.9; PotencialDeAquecimentoGlobalUsoDoSoloEMudancaDeUsoDoSolo: 0.0246; PotencialDeEutrofizacaoFraccaoDeNutrientesQueAtingemOCompartimentoFinalDeAguaDoce: 0.000189; PotencialDeEutrofizacaoFraccaoDeNutrientesQueAtingemOCompartimentoFinalMarinho: 0.0122; EnergiaRecuperada: 0.00739; ConsumoDeAguaDoce: 0.113; UtilizacaoLiquidaDeAguaDoce: 0.113; ResiduosPerigososEliminados: 0.00221; ResiduosNaoPerigososEliminados: 1.83; MassaTotalDeResiduosRadioactivosEliminados: 0.000394; EnergiaElectricaExportada: 1.55; MateriaisParaRecuperacaoDeEnergia: 0.00739; MateriaisParaReciclagem: 0.0253; UnidadeEPD: 1 m²
Type - IFC.REVIGRÉS-Dados gerais-Wall Covering - Nome: REVIGRÉS-LOCUS-BASE-44.35x88.9-SOFT GRIP-BONE; TipoProduto: Prensado a seco: grupo BIa UGL | Grés porcelânico técnico; NumeroDeRegistoDAP: EPD-REV-20240006-CCC1-EN; ReferenciaDAP: -; UrlDOP: -
Classification: C3010 (Uniformat)
Pset_WallCommon - ExtendToStructure: no; LoadBearing: no
IFC.REVIGRÉS-Dados do fabricante-Wall Covering - Type: Basic Wall: REVIGRÉS-LOCUS-BASE-44.35x88.9-SOFT GRIP-BONE
IFC.REVIGRÉS-Dados de desempenho-Wall Covering - Type: Basic Wall: REVIGRÉS-LOCUS-BASE-44.35x88.9-SOFT GRIP-BONE
IFC.REVIGRÉS-Dados de especificação-Wall Covering - Type: Basic Wall: REVIGRÉS-LOCUS-BASE-44.35x88.9-SOFT GRIP-BONE
IFC.REVIGRÉS-Dados geométricos-Wall Covering - Type: Basic Wall: REVIGRÉS-LOCUS-BASE-44.35x88.9-SOFT GRIP-BONE
IFC.REVIGRÉS-Dados de sustentabilidade-Wall Covering - Type: Basic Wall: REVIGRÉS-LOCUS-BASE-44.35x88.9-SOFT GRIP-BONE

# IfcWallStandardCase: Basic Wall:REVIGRÉS-LOCUS-BASE-44.35x88.9-SOFT GRIP-GRIS, Basic Wall:REVIGRÉS-LOCUS-BASE-44.35x88.9-SOFT GRIP-GRIS:37369
In: Level 1
Type - PredefinedType: STANDARD; Material: REVIGRÉS-LOCUS-BASE-45X90-SOFT GRIP-GRIS 10.5 mm
Type - Pset_ElementShading - Roughness: 304.8 mm
Type - Pset_ManufacturerTypeInformation - Manufacturer: REVIGRÉS
Type - Pset_ProductRequirements - Category: Walls
Type - Pset_QuantityTakeOff - Reference: 312FH8V691
Type - Pset_ReinforcementBarPitchOfWall - Description: Stone effect in wall and floor full body porcelain tile; Reference: 312FH8V691
Type - Pset_WallCommon - IsExternal: no; Reference: 312FH8V691
Type - IFC.REVIGRÉS-Dados do fabricante-Wall Covering - FabricanteURL: https://www.revigres.pt/; ReferenciaModelo: Locus; NumeroGlobalDeItemComercial: 312FH8V691; Acabamento: SOFT; Material: Grés porcelânico; IdentificadorDoOperadorEconomico: 501840856; UrlFabricanteArtigo: https://www.revigres.pt/colecoes/locus; PaisOrigem: Portugal
Type - IFC.REVIGRÉS-Dados de desempenho-Wall Covering - Rectilinearidade: ± 0.2% máx ± 1.0 mm; Ortogonalidade: ± 0.2% máx.± 1.5 mm; PlanaridadeDaSuperficie: ± 0.3% máx. ± 1.8 mm; QualidadeDaSuperficie: Cumpre; AbsorcaoDeAgua: < 0.05%; ModuloDeRuptura: > 45 N/mm²; ResistenciaAFlexao: > 3500 N; ResistenciaAAbrasaoProfunda: < 120 mm³; DilatacaoTermicaLinear: ≤ 8,0x10-6 °C-1; ResistenciaAoChoqueTermico: Resiste; DurabilidadeInterior: Cumpre; DurabilidadeResistenciaAoGeloDegelo: Resiste; ResistenciaAoEscorregamentoDIN51130: R11; ResistenciaAoEscorregamentoDIN51097: A; ResistenciaAoEscorregamentoENV51097: A; ResistenciaAoEscorregamentoENV12633: Class 2; ResistenciaAoEscorregamentoBS7976: > 36; ResistenciaAoEscorregamentoANSIA1371: ≥0,42; ResistenciaAoDeslizamentoENV12633: Class 2; ResistenciaAoDeslizamentoBS7976: > 36; ResistenciaAsManchas: Class 5; LibertacaoDeCadmio: 0; LibertacaoDeChumbo: 0
Type - IFC.REVIGRÉS-Dados de especificação-Wall Covering - VariacaoTonalidade: 3; NivelDeTrafego: 5; EPavimento: Sim; ERevestimento: Sim; EExterno: Sim
Type - IFC.REVIGRÉS-Dados geométricos-Wall Covering - AlturaNominal: 10.5 mm; ComprimentoNominal: 44.35 mm; LarguraNominal: 88.9 mm
Type - IFC.REVIGRÉS-Dados de sustentabilidade-Wall Covering - PotencialPrivacaoDeAguaConsumoDeAguaPonderado: 4.5; EnergiaTermicaExportada: 0; ItemENovo: Sim; ItemEParcialmenteReciclado: 0.23; ItemEReciclado: Sim; VidaÚtilEsperada: 50; SubstanciasPerigosas: Não; PotencialDeEsgotamentoAbioticoDosRecursosFosseis: 203; PotencialDeEsgotamentoAbioticoDosRecursosNaoFosseisMineraisEMetais: 0.000701; PotencialDeAquecimentoGlobalBiogenico: -0.48; CombustiveisFosseisComPotencialDeAquecimentoGlobal: 13.9; PotencialDeAquecimentoGlobalUsoDoSoloEMudancaDeUsoDoSolo: 0.0246; PotencialDeEutrofizacaoFraccaoDeNutrientesQueAtingemOCompartimentoFinalDeAguaDoce: 0.000189; PotencialDeEutrofizacaoFraccaoDeNutrientesQueAtingemOCompartimentoFinalMarinho: 0.0122; EnergiaRecuperada: 0.00739; ConsumoDeAguaDoce: 0.113; UtilizacaoLiquidaDeAguaDoce: 0.113; ResiduosPerigososEliminados: 0.00221; ResiduosNaoPerigososEliminados: 1.83; MassaTotalDeResiduosRadioactivosEliminados: 0.000394; EnergiaElectricaExportada: 1.55; MateriaisParaRecuperacaoDeEnergia: 0.00739; MateriaisParaReciclagem: 0.0253; UnidadeEPD: 1 m²
Type - IFC.REVIGRÉS-Dados gerais-Wall Covering - Nome: REVIGRÉS-LOCUS-BASE-44.35x88.9-SOFT GRIP-GRIS; TipoProduto: Prensado a seco: grupo BIa UGL | Grés porcelânico técnico; NumeroDeRegistoDAP: EPD-REV-20240006-CCC1-EN; ReferenciaDAP: -; UrlDOP: -
Classification: C3010 (Uniformat)
Pset_WallCommon - ExtendToStructure: no; LoadBearing: no
IFC.REVIGRÉS-Dados do fabricante-Wall Covering - Type: Basic Wall: REVIGRÉS-LOCUS-BASE-44.35x88.9-SOFT GRIP-GRIS
IFC.REVIGRÉS-Dados de desempenho-Wall Covering - Type: Basic Wall: REVIGRÉS-LOCUS-BASE-44.35x88.9-SOFT GRIP-GRIS
IFC.REVIGRÉS-Dados de especificação-Wall Covering - Type: Basic Wall: REVIGRÉS-LOCUS-BASE-44.35x88.9-SOFT GRIP-GRIS
IFC.REVIGRÉS-Dados geométricos-Wall Covering - Type: Basic Wall: REVIGRÉS-LOCUS-BASE-44.35x88.9-SOFT GRIP-GRIS
IFC.REVIGRÉS-Dados de sustentabilidade-Wall Covering - Type: Basic Wall: REVIGRÉS-LOCUS-BASE-44.35x88.9-SOFT GRIP-GRIS

# IfcWallStandardCase: Basic Wall:REVIGRÉS-LOCUS-BASE-44.35x88.9-SOFT GRIP-SMOG, Basic Wall:REVIGRÉS-LOCUS-BASE-44.35x88.9-SOFT GRIP-SMOG:37884
In: Level 1
Type - PredefinedType: STANDARD; Material: REVIGRÉS-LOCUS-BASE-45X90-SOFT GRIP-SMOG 10.5 mm
Type - Pset_ElementShading - Roughness: 304.8 mm
Type - Pset_ManufacturerTypeInformation - Manufacturer: REVIGRÉS
Type - Pset_ProductRequirements - Category: Walls
Type - Pset_QuantityTakeOff - Reference: 312FH8V701
Type - Pset_ReinforcementBarPitchOfWall - Description: Stone effect in wall and floor full body porcelain tile; Reference: 312FH8V701
Type - Pset_WallCommon - IsExternal: no; Reference: 312FH8V701
Type - IFC.REVIGRÉS-Dados do fabricante-Wall Covering - FabricanteURL: https://www.revigres.pt/; ReferenciaModelo: Locus; NumeroGlobalDeItemComercial: 312FH8V701; Acabamento: SOFT; Material: Grés porcelânico; IdentificadorDoOperadorEconomico: 501840856; UrlFabricanteArtigo: https://www.revigres.pt/colecoes/locus; PaisOrigem: Portugal
Type - IFC.REVIGRÉS-Dados de desempenho-Wall Covering - Rectilinearidade: ± 0.2% máx ± 1.0 mm; Ortogonalidade: ± 0.2% máx.± 1.5 mm; PlanaridadeDaSuperficie: ± 0.3% máx. ± 1.8 mm; QualidadeDaSuperficie: Cumpre; AbsorcaoDeAgua: < 0.05%; ModuloDeRuptura: > 45 N/mm²; ResistenciaAFlexao: > 3500 N; ResistenciaAAbrasaoProfunda: < 120 mm³; DilatacaoTermicaLinear: ≤ 8,0x10-6 °C-1; ResistenciaAoChoqueTermico: Resiste; DurabilidadeInterior: Cumpre; DurabilidadeResistenciaAoGeloDegelo: Resiste; ResistenciaAoEscorregamentoDIN51130: R11; ResistenciaAoEscorregamentoDIN51097: A; ResistenciaAoEscorregamentoENV51097: A; ResistenciaAoEscorregamentoENV12633: Class 2; ResistenciaAoEscorregamentoBS7976: > 36; ResistenciaAoEscorregamentoANSIA1371: ≥0,42; ResistenciaAoDeslizamentoENV12633: Class 2; ResistenciaAoDeslizamentoBS7976: > 36; ResistenciaAsManchas: Class 5; LibertacaoDeCadmio: 0; LibertacaoDeChumbo: 0
Type - IFC.REVIGRÉS-Dados de especificação-Wall Covering - VariacaoTonalidade: 3; NivelDeTrafego: 5; EPavimento: Sim; ERevestimento: Sim; EExterno: Sim
Type - IFC.REVIGRÉS-Dados geométricos-Wall Covering - AlturaNominal: 10.5 mm; ComprimentoNominal: 44.35 mm; LarguraNominal: 88.9 mm
Type - IFC.REVIGRÉS-Dados de sustentabilidade-Wall Covering - PotencialPrivacaoDeAguaConsumoDeAguaPonderado: 4.5; EnergiaTermicaExportada: 0; ItemENovo: Sim; ItemEParcialmenteReciclado: 0.29; ItemEReciclado: Sim; VidaÚtilEsperada: 50; SubstanciasPerigosas: Não; PotencialDeEsgotamentoAbioticoDosRecursosFosseis: 203; PotencialDeEsgotamentoAbioticoDosRecursosNaoFosseisMineraisEMetais: 0.000701; PotencialDeAquecimentoGlobalBiogenico: -0.48; CombustiveisFosseisComPotencialDeAquecimentoGlobal: 13.9; PotencialDeAquecimentoGlobalUsoDoSoloEMudancaDeUsoDoSolo: 0.0246; PotencialDeEutrofizacaoFraccaoDeNutrientesQueAtingemOCompartimentoFinalDeAguaDoce: 0.000189; PotencialDeEutrofizacaoFraccaoDeNutrientesQueAtingemOCompartimentoFinalMarinho: 0.0122; EnergiaRecuperada: 0.00739; ConsumoDeAguaDoce: 0.113; UtilizacaoLiquidaDeAguaDoce: 0.113; ResiduosPerigososEliminados: 0.00221; ResiduosNaoPerigososEliminados: 1.83; MassaTotalDeResiduosRadioactivosEliminados: 0.000394; EnergiaElectricaExportada: 1.55; MateriaisParaRecuperacaoDeEnergia: 0.00739; MateriaisParaReciclagem: 0.0253; UnidadeEPD: 1 m²
Type - IFC.REVIGRÉS-Dados gerais-Wall Covering - Nome: REVIGRÉS-LOCUS-BASE-44.35x88.9-SOFT GRIP-SMOG; TipoProduto: Prensado a seco: grupo BIa UGL | Grés porcelânico técnico; NumeroDeRegistoDAP: EPD-REV-20240006-CCC1-EN; ReferenciaDAP: -; UrlDOP: -
Classification: C3010 (Uniformat)
Pset_WallCommon - ExtendToStructure: no; LoadBearing: no
IFC.REVIGRÉS-Dados do fabricante-Wall Covering - Type: Basic Wall: REVIGRÉS-LOCUS-BASE-44.35x88.9-SOFT GRIP-SMOG
IFC.REVIGRÉS-Dados de desempenho-Wall Covering - Type: Basic Wall: REVIGRÉS-LOCUS-BASE-44.35x88.9-SOFT GRIP-SMOG
IFC.REVIGRÉS-Dados de especificação-Wall Covering - Type: Basic Wall: REVIGRÉS-LOCUS-BASE-44.35x88.9-SOFT GRIP-SMOG
IFC.REVIGRÉS-Dados geométricos-Wall Covering - Type: Basic Wall: REVIGRÉS-LOCUS-BASE-44.35x88.9-SOFT GRIP-SMOG
IFC.REVIGRÉS-Dados de sustentabilidade-Wall Covering - Type: Basic Wall: REVIGRÉS-LOCUS-BASE-44.35x88.9-SOFT GRIP-SMOG

# IfcWallStandardCase: Basic Wall:REVIGRÉS-LOCUS-BASE-59.2x59.2-SILK-ALLOY, Basic Wall:REVIGRÉS-LOCUS-BASE-59.2x59.2-SILK-ALLOY:36215
In: Level 1
Type - PredefinedType: STANDARD; Material: REVIGRÉS-LOCUS-BASE-60x60-SILK-ALLOY 8.5 mm
Type - Pset_ElementShading - Roughness: 304.8 mm
Type - Pset_ManufacturerTypeInformation - Manufacturer: REVIGRÉS
Type - Pset_ProductRequirements - Category: Walls
Type - Pset_QuantityTakeOff - Reference: 312G13V671
Type - Pset_ReinforcementBarPitchOfWall - Description: Stone effect in wall and floor full body porcelain tile; Reference: 312G13V671
Type - Pset_WallCommon - IsExternal: no; Reference: 312G13V671
Type - IFC.REVIGRÉS-Dados do fabricante-Wall Covering - FabricanteURL: https://www.revigres.pt/; ReferenciaModelo: Locus; NumeroGlobalDeItemComercial: 312G13V671; Acabamento: SILK; Material: Grés porcelânico; IdentificadorDoOperadorEconomico: 501840856; UrlFabricanteArtigo: https://www.revigres.pt/colecoes/locus; PaisOrigem: Portugal
Type - IFC.REVIGRÉS-Dados de desempenho-Wall Covering - Rectilinearidade: ± 0.2% máx.± 0.8 mm; Ortogonalidade: ± 0.2% máx.± 1.5 mm; PlanaridadeDaSuperficie: ± 0.3% máx. ± 1.8 mm; QualidadeDaSuperficie: Cumpre; AbsorcaoDeAgua: < 0.05%; ModuloDeRuptura: > 45 N/mm²; ResistenciaAFlexao: > 2000 N; ResistenciaAAbrasaoProfunda: < 120 mm³; DilatacaoTermicaLinear: ≤ 8,0x10-6 °C-1; ResistenciaAoChoqueTermico: Resiste; DurabilidadeInterior: Cumpre; DurabilidadeResistenciaAoGeloDegelo: Resiste; ResistenciaAoEscorregamentoDIN51130: R9; ResistenciaAoEscorregamentoDIN51097: A; ResistenciaAoEscorregamentoENV51097: A; ResistenciaAoEscorregamentoENV12633: Class 1; ResistenciaAoEscorregamentoBS7976: -; ResistenciaAoEscorregamentoANSIA1371: ≥0,42; ResistenciaAoDeslizamentoENV12633: Class 1; ResistenciaAoDeslizamentoBS7976: -; ResistenciaAsManchas: Class 5; LibertacaoDeCadmio: 0; LibertacaoDeChumbo: 0
Type - IFC.REVIGRÉS-Dados de especificação-Wall Covering - VariacaoTonalidade: 3; NivelDeTrafego: 5; EPavimento: Sim; ERevestimento: Sim; EExterno: Sim
Type - IFC.REVIGRÉS-Dados geométricos-Wall Covering - AlturaNominal: 8.5 mm; ComprimentoNominal: 59.2 mm; LarguraNominal: 59.2 mm
Type - IFC.REVIGRÉS-Dados de sustentabilidade-Wall Covering - ItemEParcialmenteReciclado: 0; PotencialPrivacaoDeAguaConsumoDeAguaPonderado: 4.5; EnergiaTermicaExportada: 0; ItemENovo: Sim; ItemEReciclado: Não; VidaÚtilEsperada: 50; SubstanciasPerigosas: Não; PotencialDeEsgotamentoAbioticoDosRecursosFosseis: 203; PotencialDeEsgotamentoAbioticoDosRecursosNaoFosseisMineraisEMetais: 0.000701; PotencialDeAquecimentoGlobalBiogenico: -0.48; CombustiveisFosseisComPotencialDeAquecimentoGlobal: 13.9; PotencialDeAquecimentoGlobalUsoDoSoloEMudancaDeUsoDoSolo: 0.0246; PotencialDeEutrofizacaoFraccaoDeNutrientesQueAtingemOCompartimentoFinalDeAguaDoce: 0.000189; PotencialDeEutrofizacaoFraccaoDeNutrientesQueAtingemOCompartimentoFinalMarinho: 0.0122; EnergiaRecuperada: 0.00739; ConsumoDeAguaDoce: 0.113; UtilizacaoLiquidaDeAguaDoce: 0.113; ResiduosPerigososEliminados: 0.00221; ResiduosNaoPerigososEliminados: 1.83; MassaTotalDeResiduosRadioactivosEliminados: 0.000394; EnergiaElectricaExportada: 1.55; MateriaisParaRecuperacaoDeEnergia: 0.00739; MateriaisParaReciclagem: 0.0253; UnidadeEPD: 1 m²
Type - IFC.REVIGRÉS-Dados gerais-Wall Covering - Nome: REVIGRÉS-LOCUS-BASE-59.2x59.2-SILK-ALLOY; TipoProduto: Prensado a seco: grupo BIa UGL | Grés porcelânico técnico; NumeroDeRegistoDAP: EPD-REV-20240006-CCC1-EN; ReferenciaDAP: -; UrlDOP: -
Classification: C3010 (Uniformat)
Pset_WallCommon - ExtendToStructure: no; LoadBearing: no
IFC.REVIGRÉS-Dados do fabricante-Wall Covering - Type: Basic Wall: REVIGRÉS-LOCUS-BASE-59.2x59.2-SILK-ALLOY
IFC.REVIGRÉS-Dados de desempenho-Wall Covering - Type: Basic Wall: REVIGRÉS-LOCUS-BASE-59.2x59.2-SILK-ALLOY
IFC.REVIGRÉS-Dados de especificação-Wall Covering - Type: Basic Wall: REVIGRÉS-LOCUS-BASE-59.2x59.2-SILK-ALLOY
IFC.REVIGRÉS-Dados geométricos-Wall Covering - Type: Basic Wall: REVIGRÉS-LOCUS-BASE-59.2x59.2-SILK-ALLOY
IFC.REVIGRÉS-Dados de sustentabilidade-Wall Covering - Type: Basic Wall: REVIGRÉS-LOCUS-BASE-59.2x59.2-SILK-ALLOY

# IfcWallStandardCase: Basic Wall:REVIGRÉS-LOCUS-BASE-59.2x59.2-SILK-BONE, Basic Wall:REVIGRÉS-LOCUS-BASE-59.2x59.2-SILK-BONE:36667
In: Level 1
Type - PredefinedType: STANDARD; Material: REVIGRÉS-LOCUS-BASE-60x60-SILK-BONE 8.5 mm
Type - Pset_ElementShading - Roughness: 304.8 mm
Type - Pset_ManufacturerTypeInformation - Manufacturer: REVIGRÉS
Type - Pset_ProductRequirements - Category: Walls
Type - Pset_QuantityTakeOff - Reference: 312G13V681
Type - Pset_ReinforcementBarPitchOfWall - Description: Stone effect in wall and floor full body porcelain tile; Reference: 312G13V681
Type - Pset_WallCommon - IsExternal: no; Reference: 312G13V681
Type - IFC.REVIGRÉS-Dados do fabricante-Wall Covering - FabricanteURL: https://www.revigres.pt/; ReferenciaModelo: Locus; NumeroGlobalDeItemComercial: 312G13V681; Acabamento: SILK; Material: Grés porcelânico; IdentificadorDoOperadorEconomico: 501840856; UrlFabricanteArtigo: https://www.revigres.pt/colecoes/locus; PaisOrigem: Portugal
Type - IFC.REVIGRÉS-Dados de desempenho-Wall Covering - Rectilinearidade: ± 0.2% máx.± 0.8 mm; Ortogonalidade: ± 0.2% máx.± 1.5 mm; PlanaridadeDaSuperficie: ± 0.3% máx. ± 1.8 mm; QualidadeDaSuperficie: Cumpre; AbsorcaoDeAgua: < 0.05%; ModuloDeRuptura: > 45 N/mm²; ResistenciaAFlexao: > 2000 N; ResistenciaAAbrasaoProfunda: < 120 mm³; DilatacaoTermicaLinear: ≤ 8,0x10-6 °C-1; ResistenciaAoChoqueTermico: Resiste; DurabilidadeInterior: Cumpre; DurabilidadeResistenciaAoGeloDegelo: Resiste; ResistenciaAoEscorregamentoDIN51130: R9; ResistenciaAoEscorregamentoDIN51097: A; ResistenciaAoEscorregamentoENV51097: A; ResistenciaAoEscorregamentoENV12633: Class 1; ResistenciaAoEscorregamentoBS7976: -; ResistenciaAoEscorregamentoANSIA1371: ≥0,42; ResistenciaAoDeslizamentoENV12633: Class 1; ResistenciaAoDeslizamentoBS7976: -; ResistenciaAsManchas: Class 5; LibertacaoDeCadmio: 0; LibertacaoDeChumbo: 0
Type - IFC.REVIGRÉS-Dados de especificação-Wall Covering - VariacaoTonalidade: 3; NivelDeTrafego: 5; EPavimento: Sim; ERevestimento: Sim; EExterno: Sim
Type - IFC.REVIGRÉS-Dados geométricos-Wall Covering - AlturaNominal: 8.5 mm; ComprimentoNominal: 59.2 mm; LarguraNominal: 59.2 mm
Type - IFC.REVIGRÉS-Dados de sustentabilidade-Wall Covering - ItemEParcialmenteReciclado: 0; PotencialPrivacaoDeAguaConsumoDeAguaPonderado: 4.5; EnergiaTermicaExportada: 0; ItemENovo: Sim; ItemEReciclado: Não; VidaÚtilEsperada: 50; SubstanciasPerigosas: Não; PotencialDeEsgotamentoAbioticoDosRecursosFosseis: 203; PotencialDeEsgotamentoAbioticoDosRecursosNaoFosseisMineraisEMetais: 0.000701; PotencialDeAquecimentoGlobalBiogenico: -0.48; CombustiveisFosseisComPotencialDeAquecimentoGlobal: 13.9; PotencialDeAquecimentoGlobalUsoDoSoloEMudancaDeUsoDoSolo: 0.0246; PotencialDeEutrofizacaoFraccaoDeNutrientesQueAtingemOCompartimentoFinalDeAguaDoce: 0.000189; PotencialDeEutrofizacaoFraccaoDeNutrientesQueAtingemOCompartimentoFinalMarinho: 0.0122; EnergiaRecuperada: 0.00739; ConsumoDeAguaDoce: 0.113; UtilizacaoLiquidaDeAguaDoce: 0.113; ResiduosPerigososEliminados: 0.00221; ResiduosNaoPerigososEliminados: 1.83; MassaTotalDeResiduosRadioactivosEliminados: 0.000394; EnergiaElectricaExportada: 1.55; MateriaisParaRecuperacaoDeEnergia: 0.00739; MateriaisParaReciclagem: 0.0253; UnidadeEPD: 1 m²
Type - IFC.REVIGRÉS-Dados gerais-Wall Covering - Nome: REVIGRÉS-LOCUS-BASE-59.2x59.2-SILK-BONE; TipoProduto: Prensado a seco: grupo BIa UGL | Grés porcelânico técnico; NumeroDeRegistoDAP: EPD-REV-20240006-CCC1-EN; ReferenciaDAP: -; UrlDOP: -
Classification: C3010 (Uniformat)
Pset_WallCommon - ExtendToStructure: no; LoadBearing: no
IFC.REVIGRÉS-Dados do fabricante-Wall Covering - Type: Basic Wall: REVIGRÉS-LOCUS-BASE-59.2x59.2-SILK-BONE
IFC.REVIGRÉS-Dados de desempenho-Wall Covering - Type: Basic Wall: REVIGRÉS-LOCUS-BASE-59.2x59.2-SILK-BONE
IFC.REVIGRÉS-Dados de especificação-Wall Covering - Type: Basic Wall: REVIGRÉS-LOCUS-BASE-59.2x59.2-SILK-BONE
IFC.REVIGRÉS-Dados geométricos-Wall Covering - Type: Basic Wall: REVIGRÉS-LOCUS-BASE-59.2x59.2-SILK-BONE
IFC.REVIGRÉS-Dados de sustentabilidade-Wall Covering - Type: Basic Wall: REVIGRÉS-LOCUS-BASE-59.2x59.2-SILK-BONE

# IfcWallStandardCase: Basic Wall:REVIGRÉS-LOCUS-BASE-59.2x59.2-SILK-GRIS, Basic Wall:REVIGRÉS-LOCUS-BASE-59.2x59.2-SILK-GRIS:37337
In: Level 1
Type - PredefinedType: STANDARD; Material: REVIGRÉS-LOCUS-BASE-60x60-SILK-GRIS 8.5 mm
Type - Pset_ElementShading - Roughness: 304.8 mm
Type - Pset_ManufacturerTypeInformation - Manufacturer: REVIGRÉS
Type - Pset_ProductRequirements - Category: Walls
Type - Pset_QuantityTakeOff - Reference: 312G13V691
Type - Pset_ReinforcementBarPitchOfWall - Description: Stone effect in wall and floor full body porcelain tile; Reference: 312G13V691
Type - Pset_WallCommon - IsExternal: no; Reference: 312G13V691
Type - IFC.REVIGRÉS-Dados do fabricante-Wall Covering - FabricanteURL: https://www.revigres.pt/; ReferenciaModelo: Locus; NumeroGlobalDeItemComercial: 312G13V691; Acabamento: SILK; Material: Grés porcelânico; IdentificadorDoOperadorEconomico: 501840856; UrlFabricanteArtigo: https://www.revigres.pt/colecoes/locus; PaisOrigem: Portugal
Type - IFC.REVIGRÉS-Dados de desempenho-Wall Covering - Rectilinearidade: ± 0.2% máx.± 0.8 mm; Ortogonalidade: ± 0.2% máx.± 1.5 mm; PlanaridadeDaSuperficie: ± 0.3% máx. ± 1.8 mm; QualidadeDaSuperficie: Cumpre; AbsorcaoDeAgua: < 0.05%; ModuloDeRuptura: > 45 N/mm²; ResistenciaAFlexao: > 2000 N; ResistenciaAAbrasaoProfunda: < 120 mm³; DilatacaoTermicaLinear: ≤ 8,0x10-6 °C-1; ResistenciaAoChoqueTermico: Resiste; DurabilidadeInterior: Cumpre; DurabilidadeResistenciaAoGeloDegelo: Resiste; ResistenciaAoEscorregamentoDIN51130: R9; ResistenciaAoEscorregamentoDIN51097: A; ResistenciaAoEscorregamentoENV51097: A; ResistenciaAoEscorregamentoENV12633: Class 1; ResistenciaAoEscorregamentoBS7976: -; ResistenciaAoEscorregamentoANSIA1371: ≥0,42; ResistenciaAoDeslizamentoENV12633: Class 1; ResistenciaAoDeslizamentoBS7976: -; ResistenciaAsManchas: Class 5; LibertacaoDeCadmio: 0; LibertacaoDeChumbo: 0
Type - IFC.REVIGRÉS-Dados de especificação-Wall Covering - VariacaoTonalidade: 3; NivelDeTrafego: 5; EPavimento: Sim; ERevestimento: Sim; EExterno: Sim
Type - IFC.REVIGRÉS-Dados geométricos-Wall Covering - AlturaNominal: 8.5 mm; ComprimentoNominal: 59.2 mm; LarguraNominal: 59.2 mm
Type - IFC.REVIGRÉS-Dados de sustentabilidade-Wall Covering - PotencialPrivacaoDeAguaConsumoDeAguaPonderado: 4.5; EnergiaTermicaExportada: 0; ItemENovo: Sim; ItemEParcialmenteReciclado: 0.23; ItemEReciclado: Sim; VidaÚtilEsperada: 50; SubstanciasPerigosas: Não; PotencialDeEsgotamentoAbioticoDosRecursosFosseis: 203; PotencialDeEsgotamentoAbioticoDosRecursosNaoFosseisMineraisEMetais: 0.000701; PotencialDeAquecimentoGlobalBiogenico: -0.48; CombustiveisFosseisComPotencialDeAquecimentoGlobal: 13.9; PotencialDeAquecimentoGlobalUsoDoSoloEMudancaDeUsoDoSolo: 0.0246; PotencialDeEutrofizacaoFraccaoDeNutrientesQueAtingemOCompartimentoFinalDeAguaDoce: 0.000189; PotencialDeEutrofizacaoFraccaoDeNutrientesQueAtingemOCompartimentoFinalMarinho: 0.0122; EnergiaRecuperada: 0.00739; ConsumoDeAguaDoce: 0.113; UtilizacaoLiquidaDeAguaDoce: 0.113; ResiduosPerigososEliminados: 0.00221; ResiduosNaoPerigososEliminados: 1.83; MassaTotalDeResiduosRadioactivosEliminados: 0.000394; EnergiaElectricaExportada: 1.55; MateriaisParaRecuperacaoDeEnergia: 0.00739; MateriaisParaReciclagem: 0.0253; UnidadeEPD: 1 m²
Type - IFC.REVIGRÉS-Dados gerais-Wall Covering - Nome: REVIGRÉS-LOCUS-BASE-59.2x59.2-SILK-GRIS; TipoProduto: Prensado a seco: grupo BIa UGL | Grés porcelânico técnico; NumeroDeRegistoDAP: EPD-REV-20240006-CCC1-EN; ReferenciaDAP: -; UrlDOP: -
Classification: C3010 (Uniformat)
Pset_WallCommon - ExtendToStructure: no; LoadBearing: no
IFC.REVIGRÉS-Dados do fabricante-Wall Covering - Type: Basic Wall: REVIGRÉS-LOCUS-BASE-59.2x59.2-SILK-GRIS
IFC.REVIGRÉS-Dados de desempenho-Wall Covering - Type: Basic Wall: REVIGRÉS-LOCUS-BASE-59.2x59.2-SILK-GRIS
IFC.REVIGRÉS-Dados de especificação-Wall Covering - Type: Basic Wall: REVIGRÉS-LOCUS-BASE-59.2x59.2-SILK-GRIS
IFC.REVIGRÉS-Dados geométricos-Wall Covering - Type: Basic Wall: REVIGRÉS-LOCUS-BASE-59.2x59.2-SILK-GRIS
IFC.REVIGRÉS-Dados de sustentabilidade-Wall Covering - Type: Basic Wall: REVIGRÉS-LOCUS-BASE-59.2x59.2-SILK-GRIS

# IfcWallStandardCase: Basic Wall:REVIGRÉS-LOCUS-BASE-59.2x59.2-SILK-SMOG, Basic Wall:REVIGRÉS-LOCUS-BASE-59.2x59.2-SILK-SMOG:37852
In: Level 1
Type - PredefinedType: STANDARD; Material: REVIGRÉS-LOCUS-BASE-60x60-SILK-SMOG 8.5 mm
Type - Pset_ElementShading - Roughness: 304.8 mm
Type - Pset_ManufacturerTypeInformation - Manufacturer: REVIGRÉS
Type - Pset_ProductRequirements - Category: Walls
Type - Pset_QuantityTakeOff - Reference: 312G13V701
Type - Pset_ReinforcementBarPitchOfWall - Description: Stone effect in wall and floor full body porcelain tile; Reference: 312G13V701
Type - Pset_WallCommon - IsExternal: no; Reference: 312G13V701
Type - IFC.REVIGRÉS-Dados do fabricante-Wall Covering - FabricanteURL: https://www.revigres.pt/; ReferenciaModelo: Locus; NumeroGlobalDeItemComercial: 312G13V701; Acabamento: SILK; Material: Grés porcelânico; IdentificadorDoOperadorEconomico: 501840856; UrlFabricanteArtigo: https://www.revigres.pt/colecoes/locus; PaisOrigem: Portugal
Type - IFC.REVIGRÉS-Dados de desempenho-Wall Covering - Rectilinearidade: ± 0.2% máx.± 0.8 mm; Ortogonalidade: ± 0.2% máx.± 1.5 mm; PlanaridadeDaSuperficie: ± 0.3% máx. ± 1.8 mm; QualidadeDaSuperficie: Cumpre; AbsorcaoDeAgua: < 0.05%; ModuloDeRuptura: > 45 N/mm²; ResistenciaAFlexao: > 2000 N; ResistenciaAAbrasaoProfunda: < 120 mm³; DilatacaoTermicaLinear: ≤ 8,0x10-6 °C-1; ResistenciaAoChoqueTermico: Resiste; DurabilidadeInterior: Cumpre; DurabilidadeResistenciaAoGeloDegelo: Resiste; ResistenciaAoEscorregamentoDIN51130: R9; ResistenciaAoEscorregamentoDIN51097: A; ResistenciaAoEscorregamentoENV51097: A; ResistenciaAoEscorregamentoENV12633: Class 1; ResistenciaAoEscorregamentoBS7976: -; ResistenciaAoEscorregamentoANSIA1371: ≥0,42; ResistenciaAoDeslizamentoENV12633: Class 1; ResistenciaAoDeslizamentoBS7976: -; ResistenciaAsManchas: Class 5; LibertacaoDeCadmio: 0; LibertacaoDeChumbo: 0
Type - IFC.REVIGRÉS-Dados de especificação-Wall Covering - VariacaoTonalidade: 3; NivelDeTrafego: 5; EPavimento: Sim; ERevestimento: Sim; EExterno: Sim
Type - IFC.REVIGRÉS-Dados geométricos-Wall Covering - AlturaNominal: 8.5 mm; ComprimentoNominal: 59.2 mm; LarguraNominal: 59.2 mm
Type - IFC.REVIGRÉS-Dados de sustentabilidade-Wall Covering - PotencialPrivacaoDeAguaConsumoDeAguaPonderado: 4.5; EnergiaTermicaExportada: 0; ItemENovo: Sim; ItemEParcialmenteReciclado: 0.29; ItemEReciclado: Sim; VidaÚtilEsperada: 50; SubstanciasPerigosas: Não; PotencialDeEsgotamentoAbioticoDosRecursosFosseis: 203; PotencialDeEsgotamentoAbioticoDosRecursosNaoFosseisMineraisEMetais: 0.000701; PotencialDeAquecimentoGlobalBiogenico: -0.48; CombustiveisFosseisComPotencialDeAquecimentoGlobal: 13.9; PotencialDeAquecimentoGlobalUsoDoSoloEMudancaDeUsoDoSolo: 0.0246; PotencialDeEutrofizacaoFraccaoDeNutrientesQueAtingemOCompartimentoFinalDeAguaDoce: 0.000189; PotencialDeEutrofizacaoFraccaoDeNutrientesQueAtingemOCompartimentoFinalMarinho: 0.0122; EnergiaRecuperada: 0.00739; ConsumoDeAguaDoce: 0.113; UtilizacaoLiquidaDeAguaDoce: 0.113; ResiduosPerigososEliminados: 0.00221; ResiduosNaoPerigososEliminados: 1.83; MassaTotalDeResiduosRadioactivosEliminados: 0.000394; EnergiaElectricaExportada: 1.55; MateriaisParaRecuperacaoDeEnergia: 0.00739; MateriaisParaReciclagem: 0.0253; UnidadeEPD: 1 m²
Type - IFC.REVIGRÉS-Dados gerais-Wall Covering - Nome: REVIGRÉS-LOCUS-BASE-59.2x59.2-SILK-SMOG; TipoProduto: Prensado a seco: grupo BIa UGL | Grés porcelânico técnico; NumeroDeRegistoDAP: EPD-REV-20240006-CCC1-EN; ReferenciaDAP: -; UrlDOP: -
Classification: C3010 (Uniformat)
Pset_WallCommon - ExtendToStructure: no; LoadBearing: no
IFC.REVIGRÉS-Dados do fabricante-Wall Covering - Type: Basic Wall: REVIGRÉS-LOCUS-BASE-59.2x59.2-SILK-SMOG
IFC.REVIGRÉS-Dados de desempenho-Wall Covering - Type: Basic Wall: REVIGRÉS-LOCUS-BASE-59.2x59.2-SILK-SMOG
IFC.REVIGRÉS-Dados de especificação-Wall Covering - Type: Basic Wall: REVIGRÉS-LOCUS-BASE-59.2x59.2-SILK-SMOG
IFC.REVIGRÉS-Dados geométricos-Wall Covering - Type: Basic Wall: REVIGRÉS-LOCUS-BASE-59.2x59.2-SILK-SMOG
IFC.REVIGRÉS-Dados de sustentabilidade-Wall Covering - Type: Basic Wall: REVIGRÉS-LOCUS-BASE-59.2x59.2-SILK-SMOG

# IfcWallStandardCase: Basic Wall:REVIGRÉS-LOCUS-BASE-59.2x59.2-SOFT GRIP-ALLOY, Basic Wall:REVIGRÉS-LOCUS-BASE-59.2x59.2-SOFT GRIP-ALLOY:36223
In: Level 1
Type - PredefinedType: STANDARD; Material: REVIGRÉS-LOCUS-BASE-60x60-SOFT GRIP-ALLOY 8.5 mm
Type - Pset_ElementShading - Roughness: 304.8 mm
Type - Pset_ManufacturerTypeInformation - Manufacturer: REVIGRÉS
Type - Pset_ProductRequirements - Category: Walls
Type - Pset_QuantityTakeOff - Reference: 312F13V671
Type - Pset_ReinforcementBarPitchOfWall - Description: Stone effect in wall and floor full body porcelain tile; Reference: 312F13V671
Type - Pset_WallCommon - IsExternal: no; Reference: 312F13V671
Type - IFC.REVIGRÉS-Dados do fabricante-Wall Covering - FabricanteURL: https://www.revigres.pt/; ReferenciaModelo: Locus; NumeroGlobalDeItemComercial: 312F13V671; Acabamento: SOFT; Material: Grés porcelânico; IdentificadorDoOperadorEconomico: 501840856; UrlFabricanteArtigo: https://www.revigres.pt/colecoes/locus; PaisOrigem: Portugal
Type - IFC.REVIGRÉS-Dados de desempenho-Wall Covering - Rectilinearidade: ± 0.2% máx ± 1.0 mm; Ortogonalidade: ± 0.2% máx.± 1.5 mm; PlanaridadeDaSuperficie: ± 0.3% máx. ± 1.8 mm; QualidadeDaSuperficie: Cumpre; AbsorcaoDeAgua: < 0.05%; ModuloDeRuptura: > 45 N/mm²; ResistenciaAFlexao: > 2000 N; ResistenciaAAbrasaoProfunda: < 120 mm³; DilatacaoTermicaLinear: ≤ 8,0x10-6 °C-1; ResistenciaAoChoqueTermico: Resiste; DurabilidadeInterior: Cumpre; DurabilidadeResistenciaAoGeloDegelo: Resiste; ResistenciaAoEscorregamentoDIN51130: R11; ResistenciaAoEscorregamentoDIN51097: A; ResistenciaAoEscorregamentoENV51097: A; ResistenciaAoEscorregamentoENV12633: Class 2; ResistenciaAoEscorregamentoBS7976: > 36; ResistenciaAoEscorregamentoANSIA1371: ≥0,42; ResistenciaAoDeslizamentoENV12633: Class 2; ResistenciaAoDeslizamentoBS7976: > 36; ResistenciaAsManchas: Class 5; LibertacaoDeCadmio: 0; LibertacaoDeChumbo: 0
Type - IFC.REVIGRÉS-Dados de especificação-Wall Covering - VariacaoTonalidade: 3; NivelDeTrafego: 5; EPavimento: Sim; ERevestimento: Sim; EExterno: Sim
Type - IFC.REVIGRÉS-Dados geométricos-Wall Covering - AlturaNominal: 8.5 mm; ComprimentoNominal: 59.2 mm; LarguraNominal: 59.2 mm
Type - IFC.REVIGRÉS-Dados de sustentabilidade-Wall Covering - ItemEParcialmenteReciclado: 0; PotencialPrivacaoDeAguaConsumoDeAguaPonderado: 4.5; EnergiaTermicaExportada: 0; ItemENovo: Sim; ItemEReciclado: Não; VidaÚtilEsperada: 50; SubstanciasPerigosas: Não; PotencialDeEsgotamentoAbioticoDosRecursosFosseis: 203; PotencialDeEsgotamentoAbioticoDosRecursosNaoFosseisMineraisEMetais: 0.000701; PotencialDeAquecimentoGlobalBiogenico: -0.48; CombustiveisFosseisComPotencialDeAquecimentoGlobal: 13.9; PotencialDeAquecimentoGlobalUsoDoSoloEMudancaDeUsoDoSolo: 0.0246; PotencialDeEutrofizacaoFraccaoDeNutrientesQueAtingemOCompartimentoFinalDeAguaDoce: 0.000189; PotencialDeEutrofizacaoFraccaoDeNutrientesQueAtingemOCompartimentoFinalMarinho: 0.0122; EnergiaRecuperada: 0.00739; ConsumoDeAguaDoce: 0.113; UtilizacaoLiquidaDeAguaDoce: 0.113; ResiduosPerigososEliminados: 0.00221; ResiduosNaoPerigososEliminados: 1.83; MassaTotalDeResiduosRadioactivosEliminados: 0.000394; EnergiaElectricaExportada: 1.55; MateriaisParaRecuperacaoDeEnergia: 0.00739; MateriaisParaReciclagem: 0.0253; UnidadeEPD: 1 m²
Type - IFC.REVIGRÉS-Dados gerais-Wall Covering - Nome: REVIGRÉS-LOCUS-BASE-59.2x59.2-SOFT GRIP-ALLOY; TipoProduto: Prensado a seco: grupo BIa UGL | Grés porcelânico técnico; NumeroDeRegistoDAP: EPD-REV-20240006-CCC1-EN; ReferenciaDAP: -; UrlDOP: -
Classification: C3010 (Uniformat)
Pset_WallCommon - ExtendToStructure: no; LoadBearing: no
IFC.REVIGRÉS-Dados do fabricante-Wall Covering - Type: Basic Wall: REVIGRÉS-LOCUS-BASE-59.2x59.2-SOFT GRIP-ALLOY
IFC.REVIGRÉS-Dados de desempenho-Wall Covering - Type: Basic Wall: REVIGRÉS-LOCUS-BASE-59.2x59.2-SOFT GRIP-ALLOY
IFC.REVIGRÉS-Dados de especificação-Wall Covering - Type: Basic Wall: REVIGRÉS-LOCUS-BASE-59.2x59.2-SOFT GRIP-ALLOY
IFC.REVIGRÉS-Dados geométricos-Wall Covering - Type: Basic Wall: REVIGRÉS-LOCUS-BASE-59.2x59.2-SOFT GRIP-ALLOY
IFC.REVIGRÉS-Dados de sustentabilidade-Wall Covering - Type: Basic Wall: REVIGRÉS-LOCUS-BASE-59.2x59.2-SOFT GRIP-ALLOY

# IfcWallStandardCase: Basic Wall:REVIGRÉS-LOCUS-BASE-59.2x59.2-SOFT GRIP-BONE, Basic Wall:REVIGRÉS-LOCUS-BASE-59.2x59.2-SOFT GRIP-BONE:36675
In: Level 1
Type - PredefinedType: STANDARD; Material: REVIGRÉS-LOCUS-BASE-60x60-SOFT GRIP-BONE 8.5 mm
Type - Pset_ElementShading - Roughness: 304.8 mm
Type - Pset_ManufacturerTypeInformation - Manufacturer: REVIGRÉS
Type - Pset_ProductRequirements - Category: Walls
Type - Pset_QuantityTakeOff - Reference: 312F13V681
Type - Pset_ReinforcementBarPitchOfWall - Description: Stone effect in wall and floor full body porcelain tile; Reference: 312F13V681
Type - Pset_WallCommon - IsExternal: no; Reference: 312F13V681
Type - IFC.REVIGRÉS-Dados do fabricante-Wall Covering - FabricanteURL: https://www.revigres.pt/; ReferenciaModelo: Locus; NumeroGlobalDeItemComercial: 312F13V681; Acabamento: SOFT; Material: Grés porcelânico; IdentificadorDoOperadorEconomico: 501840856; UrlFabricanteArtigo: https://www.revigres.pt/colecoes/locus; PaisOrigem: Portugal
Type - IFC.REVIGRÉS-Dados de desempenho-Wall Covering - Rectilinearidade: ± 0.2% máx ± 1.0 mm; Ortogonalidade: ± 0.2% máx.± 1.5 mm; PlanaridadeDaSuperficie: ± 0.3% máx. ± 1.8 mm; QualidadeDaSuperficie: Cumpre; AbsorcaoDeAgua: < 0.05%; ModuloDeRuptura: > 45 N/mm²; ResistenciaAFlexao: > 2000 N; ResistenciaAAbrasaoProfunda: < 120 mm³; DilatacaoTermicaLinear: ≤ 8,0x10-6 °C-1; ResistenciaAoChoqueTermico: Resiste; DurabilidadeInterior: Cumpre; DurabilidadeResistenciaAoGeloDegelo: Resiste; ResistenciaAoEscorregamentoDIN51130: R11; ResistenciaAoEscorregamentoDIN51097: A; ResistenciaAoEscorregamentoENV51097: A; ResistenciaAoEscorregamentoENV12633: Class 2; ResistenciaAoEscorregamentoBS7976: > 36; ResistenciaAoEscorregamentoANSIA1371: ≥0,42; ResistenciaAoDeslizamentoENV12633: Class 2; ResistenciaAoDeslizamentoBS7976: > 36; ResistenciaAsManchas: Class 5; LibertacaoDeCadmio: 0; LibertacaoDeChumbo: 0
Type - IFC.REVIGRÉS-Dados de especificação-Wall Covering - VariacaoTonalidade: 3; NivelDeTrafego: 5; EPavimento: Sim; ERevestimento: Sim; EExterno: Sim
Type - IFC.REVIGRÉS-Dados geométricos-Wall Covering - AlturaNominal: 8.5 mm; ComprimentoNominal: 59.2 mm; LarguraNominal: 59.2 mm
Type - IFC.REVIGRÉS-Dados de sustentabilidade-Wall Covering - ItemEParcialmenteReciclado: 0; PotencialPrivacaoDeAguaConsumoDeAguaPonderado: 4.5; EnergiaTermicaExportada: 0; ItemENovo: Sim; ItemEReciclado: Não; VidaÚtilEsperada: 50; SubstanciasPerigosas: Não; PotencialDeEsgotamentoAbioticoDosRecursosFosseis: 203; PotencialDeEsgotamentoAbioticoDosRecursosNaoFosseisMineraisEMetais: 0.000701; PotencialDeAquecimentoGlobalBiogenico: -0.48; CombustiveisFosseisComPotencialDeAquecimentoGlobal: 13.9; PotencialDeAquecimentoGlobalUsoDoSoloEMudancaDeUsoDoSolo: 0.0246; PotencialDeEutrofizacaoFraccaoDeNutrientesQueAtingemOCompartimentoFinalDeAguaDoce: 0.000189; PotencialDeEutrofizacaoFraccaoDeNutrientesQueAtingemOCompartimentoFinalMarinho: 0.0122; EnergiaRecuperada: 0.00739; ConsumoDeAguaDoce: 0.113; UtilizacaoLiquidaDeAguaDoce: 0.113; ResiduosPerigososEliminados: 0.00221; ResiduosNaoPerigososEliminados: 1.83; MassaTotalDeResiduosRadioactivosEliminados: 0.000394; EnergiaElectricaExportada: 1.55; MateriaisParaRecuperacaoDeEnergia: 0.00739; MateriaisParaReciclagem: 0.0253; UnidadeEPD: 1 m²
Type - IFC.REVIGRÉS-Dados gerais-Wall Covering - Nome: REVIGRÉS-LOCUS-BASE-59.2x59.2-SOFT GRIP-BONE; TipoProduto: Prensado a seco: grupo BIa UGL | Grés porcelânico técnico; NumeroDeRegistoDAP: EPD-REV-20240006-CCC1-EN; ReferenciaDAP: -; UrlDOP: -
Classification: C3010 (Uniformat)
Pset_WallCommon - ExtendToStructure: no; LoadBearing: no
IFC.REVIGRÉS-Dados do fabricante-Wall Covering - Type: Basic Wall: REVIGRÉS-LOCUS-BASE-59.2x59.2-SOFT GRIP-BONE
IFC.REVIGRÉS-Dados de desempenho-Wall Covering - Type: Basic Wall: REVIGRÉS-LOCUS-BASE-59.2x59.2-SOFT GRIP-BONE
IFC.REVIGRÉS-Dados de especificação-Wall Covering - Type: Basic Wall: REVIGRÉS-LOCUS-BASE-59.2x59.2-SOFT GRIP-BONE
IFC.REVIGRÉS-Dados geométricos-Wall Covering - Type: Basic Wall: REVIGRÉS-LOCUS-BASE-59.2x59.2-SOFT GRIP-BONE
IFC.REVIGRÉS-Dados de sustentabilidade-Wall Covering - Type: Basic Wall: REVIGRÉS-LOCUS-BASE-59.2x59.2-SOFT GRIP-BONE

# IfcWallStandardCase: Basic Wall:REVIGRÉS-LOCUS-BASE-59.2x59.2-SOFT GRIP-GRIS, Basic Wall:REVIGRÉS-LOCUS-BASE-59.2x59.2-SOFT GRIP-GRIS:37345
In: Level 1
Type - PredefinedType: STANDARD; Material: REVIGRÉS-LOCUS-BASE-60x60-SOFT GRIP-GRIS 8.5 mm
Type - Pset_ElementShading - Roughness: 304.8 mm
Type - Pset_ManufacturerTypeInformation - Manufacturer: REVIGRÉS
Type - Pset_ProductRequirements - Category: Walls
Type - Pset_QuantityTakeOff - Reference: 312F13V691
Type - Pset_ReinforcementBarPitchOfWall - Description: Stone effect in wall and floor full body porcelain tile; Reference: 312F13V691
Type - Pset_WallCommon - IsExternal: no; Reference: 312F13V691
Type - IFC.REVIGRÉS-Dados do fabricante-Wall Covering - FabricanteURL: https://www.revigres.pt/; ReferenciaModelo: Locus; NumeroGlobalDeItemComercial: 312F13V691; Acabamento: SOFT; Material: Grés porcelânico; IdentificadorDoOperadorEconomico: 501840856; UrlFabricanteArtigo: https://www.revigres.pt/colecoes/locus; PaisOrigem: Portugal
Type - IFC.REVIGRÉS-Dados de desempenho-Wall Covering - Rectilinearidade: ± 0.2% máx ± 1.0 mm; Ortogonalidade: ± 0.2% máx.± 1.5 mm; PlanaridadeDaSuperficie: ± 0.3% máx. ± 1.8 mm; QualidadeDaSuperficie: Cumpre; AbsorcaoDeAgua: < 0.05%; ModuloDeRuptura: > 45 N/mm²; ResistenciaAFlexao: > 2000 N; ResistenciaAAbrasaoProfunda: < 120 mm³; DilatacaoTermicaLinear: ≤ 8,0x10-6 °C-1; ResistenciaAoChoqueTermico: Resiste; DurabilidadeInterior: Cumpre; DurabilidadeResistenciaAoGeloDegelo: Resiste; ResistenciaAoEscorregamentoDIN51130: R11; ResistenciaAoEscorregamentoDIN51097: A; ResistenciaAoEscorregamentoENV51097: A; ResistenciaAoEscorregamentoENV12633: Class 2; ResistenciaAoEscorregamentoBS7976: > 36; ResistenciaAoEscorregamentoANSIA1371: ≥0,42; ResistenciaAoDeslizamentoENV12633: Class 2; ResistenciaAoDeslizamentoBS7976: > 36; ResistenciaAsManchas: Class 5; LibertacaoDeCadmio: 0; LibertacaoDeChumbo: 0
Type - IFC.REVIGRÉS-Dados de especificação-Wall Covering - VariacaoTonalidade: 3; NivelDeTrafego: 5; EPavimento: Sim; ERevestimento: Sim; EExterno: Sim
Type - IFC.REVIGRÉS-Dados geométricos-Wall Covering - AlturaNominal: 8.5 mm; ComprimentoNominal: 59.2 mm; LarguraNominal: 59.2 mm
Type - IFC.REVIGRÉS-Dados de sustentabilidade-Wall Covering - PotencialPrivacaoDeAguaConsumoDeAguaPonderado: 4.5; EnergiaTermicaExportada: 0; ItemENovo: Sim; ItemEParcialmenteReciclado: 0.23; ItemEReciclado: Sim; VidaÚtilEsperada: 50; SubstanciasPerigosas: Não; PotencialDeEsgotamentoAbioticoDosRecursosFosseis: 203; PotencialDeEsgotamentoAbioticoDosRecursosNaoFosseisMineraisEMetais: 0.000701; PotencialDeAquecimentoGlobalBiogenico: -0.48; CombustiveisFosseisComPotencialDeAquecimentoGlobal: 13.9; PotencialDeAquecimentoGlobalUsoDoSoloEMudancaDeUsoDoSolo: 0.0246; PotencialDeEutrofizacaoFraccaoDeNutrientesQueAtingemOCompartimentoFinalDeAguaDoce: 0.000189; PotencialDeEutrofizacaoFraccaoDeNutrientesQueAtingemOCompartimentoFinalMarinho: 0.0122; EnergiaRecuperada: 0.00739; ConsumoDeAguaDoce: 0.113; UtilizacaoLiquidaDeAguaDoce: 0.113; ResiduosPerigososEliminados: 0.00221; ResiduosNaoPerigososEliminados: 1.83; MassaTotalDeResiduosRadioactivosEliminados: 0.000394; EnergiaElectricaExportada: 1.55; MateriaisParaRecuperacaoDeEnergia: 0.00739; MateriaisParaReciclagem: 0.0253; UnidadeEPD: 1 m²
Type - IFC.REVIGRÉS-Dados gerais-Wall Covering - Nome: REVIGRÉS-LOCUS-BASE-59.2x59.2-SOFT GRIP-GRIS; TipoProduto: Prensado a seco: grupo BIa UGL | Grés porcelânico técnico; NumeroDeRegistoDAP: EPD-REV-20240006-CCC1-EN; ReferenciaDAP: -; UrlDOP: -
Classification: C3010 (Uniformat)
Pset_WallCommon - ExtendToStructure: no; LoadBearing: no
IFC.REVIGRÉS-Dados do fabricante-Wall Covering - Type: Basic Wall: REVIGRÉS-LOCUS-BASE-59.2x59.2-SOFT GRIP-GRIS
